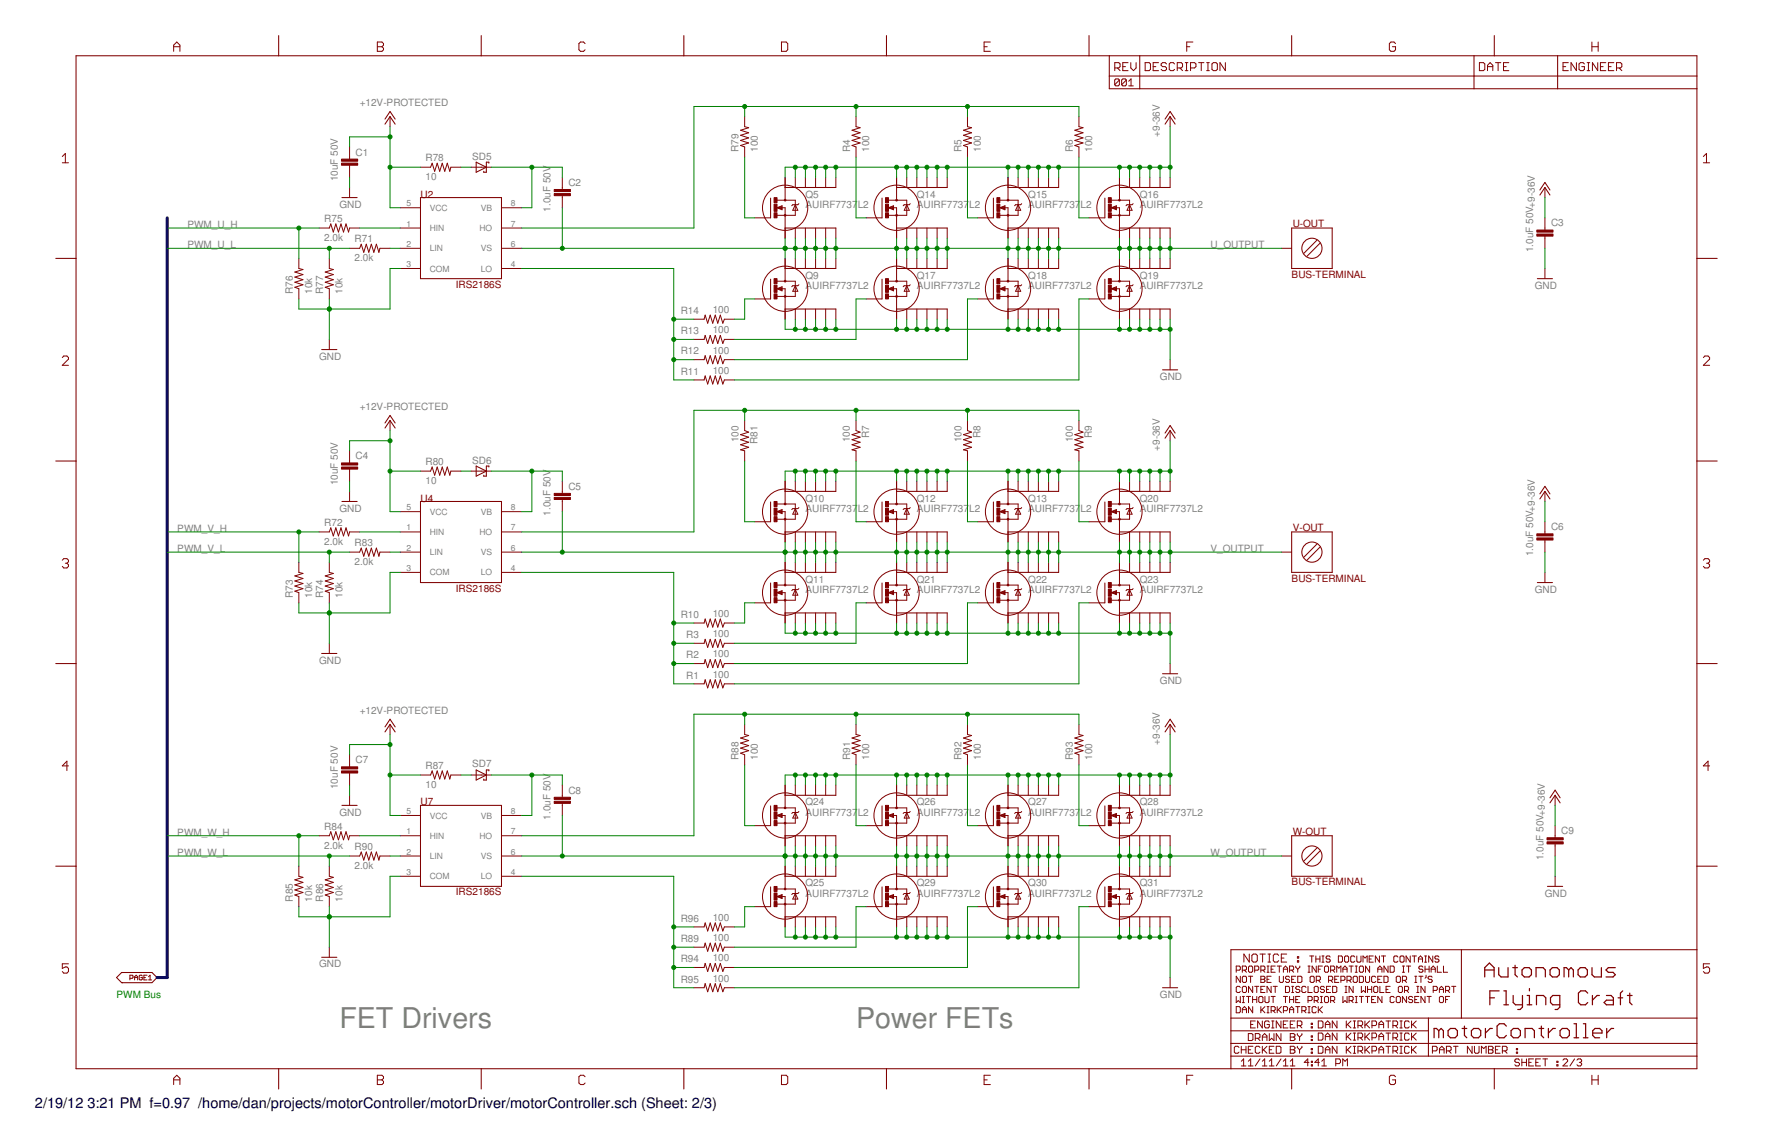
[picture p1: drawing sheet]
<svg xmlns="http://www.w3.org/2000/svg" width="431mm" height="279mm" viewBox="0 0 431 279" stroke-linecap="round" stroke-linejoin="round" font-family="sans-serif">
<defs><g id="words">
<g font-size="7" fill="#808080">
<text x="82.6" y="250.2">FET Drivers</text>
<text x="208.3" y="250.2">Power FETs</text>
</g>
<g font-size="3.5">
<text x="8.5" y="269.5">2/19/12</text>
<text x="21.3" y="269.5">3:21 PM f=0.97 /home/dan/projects/motorController/motorDriver/motorController.sch (Sheet: 2/3)</text>
</g>
<g font-size="2.4" fill="#808080">
<text x="87.5" y="25.9">+12V-PROTECTED</text>
<text x="282.2" y="33.3" transform="rotate(-90 282.2 33.3)">+9-36V</text>
<text x="86.5" y="37.9">C1</text>
<text x="103.5" y="39.2">R78</text>
<text x="114.9" y="38.8">SD5</text>
<text x="179.7" y="37" transform="rotate(-90 179.7 37)">R79</text>
<text x="184.4" y="37" transform="rotate(-90 184.4 37)">100</text>
<text x="206.8" y="37" transform="rotate(-90 206.8 37)">R4</text>
<text x="211.5" y="37" transform="rotate(-90 211.5 37)">100</text>
<text x="233.9" y="37" transform="rotate(-90 233.9 37)">R5</text>
<text x="238.6" y="37" transform="rotate(-90 238.6 37)">100</text>
<text x="261" y="37" transform="rotate(-90 261 37)">R6</text>
<text x="265.7" y="37" transform="rotate(-90 265.7 37)">100</text>
<text x="82.2" y="44.1" transform="rotate(-90 82.2 44.1)">10uF 50V</text>
<text x="103.5" y="43.9">10</text>
<text x="138.3" y="45.2">C2</text>
<text x="82.6" y="50.5">GND</text>
<text x="134" y="51.5" transform="rotate(-90 134 51.5)">1.0uF 50V</text>
<text x="195.9" y="50.5">AUIRF7737</text>
<text x="195.9" y="48.1">Q5</text>
<text x="208.7" y="50.5">L2</text>
<text x="223.1" y="50.5">AUIRF7737</text>
<text x="223.1" y="48.1">Q14</text>
<text x="235.8" y="50.5">L2</text>
<text x="250.2" y="50.5">AUIRF7737</text>
<text x="250.2" y="48.1">Q15</text>
<text x="262.9" y="50.5">L2</text>
<text x="277.3" y="50.5">AUIRF7737L2</text>
<text x="277.3" y="48.1">Q16</text>
<text x="45.6" y="55.5">PWM_U_H</text>
<text x="78.9" y="58.7">2.0k</text>
<text x="78.9" y="54">R75</text>
<text x="86.3" y="58.9">R71</text>
<text x="377.3" y="55.1">C3</text>
<text x="45.6" y="60.4">PWM_U_L</text>
<text x="86.3" y="63.6">2.0k</text>
<text x="294.5" y="60.4">U_OUTPUT</text>
<text x="373" y="61.4" transform="rotate(-90 373 61.4)">1.0uF 50V+9-36V</text>
<text x="71.3" y="71.5" transform="rotate(-90 71.3 71.5)">R76</text>
<text x="75.9" y="71.5" transform="rotate(-90 75.9 71.5)">10k</text>
<text x="78.7" y="71.5" transform="rotate(-90 78.7 71.5)">R77</text>
<text x="83.3" y="71.5" transform="rotate(-90 83.3 71.5)">10k</text>
<text x="195.9" y="70.3">AUIRF7737L2</text>
<text x="195.9" y="67.8">Q9</text>
<text x="223.1" y="70.3">AUIRF7737L2</text>
<text x="223.1" y="67.8">Q17</text>
<text x="250.2" y="70.3">AUIRF7737L2</text>
<text x="250.2" y="67.8">Q18</text>
<text x="277.3" y="70.3">AUIRF7737L2</text>
<text x="277.3" y="67.8">Q19</text>
<text x="373.4" y="70.3">GND</text>
<text x="165.6" y="76.4">R14</text>
<text x="173.4" y="76.2">100</text>
<text x="165.6" y="81.3">R13</text>
<text x="173.4" y="81.1">100</text>
<text x="77.6" y="87.5">GND</text>
<text x="165.6" y="86.2">R12</text>
<text x="173.4" y="86">100</text>
<text x="165.6" y="91.2">R11</text>
<text x="173.4" y="90.9">100</text>
<text x="282.2" y="92.4">GND</text>
<text x="87.5" y="99.8">+12V-PROTECTED</text>
<text x="179.7" y="107.6" transform="rotate(-90 179.7 107.6)">100</text>
<text x="184.3" y="108" transform="rotate(-90 184.3 108)">R81</text>
<text x="206.8" y="107.6" transform="rotate(-90 206.8 107.6)">100</text>
<text x="211.4" y="106.6" transform="rotate(-90 211.4 106.6)">R7</text>
<text x="233.9" y="107.6" transform="rotate(-90 233.9 107.6)">100</text>
<text x="238.5" y="106.6" transform="rotate(-90 238.5 106.6)">R8</text>
<text x="261" y="107.6" transform="rotate(-90 261 107.6)">100</text>
<text x="265.7" y="106.6" transform="rotate(-90 265.7 106.6)">R9</text>
<text x="86.5" y="111.8">C4</text>
<text x="103.5" y="113.2">R80</text>
<text x="114.9" y="112.8">SD6</text>
<text x="282.2" y="109.7" transform="rotate(-90 282.2 109.7)">+9-36V</text>
<text x="82.2" y="118.1" transform="rotate(-90 82.2 118.1)">10uF 50V</text>
<text x="103.5" y="117.8">10</text>
<text x="138.3" y="119.2">C5</text>
<text x="82.6" y="124.5">GND</text>
<text x="134" y="125.5" transform="rotate(-90 134 125.5)">1.0uF 50V</text>
<text x="195.9" y="124.5">AUIRF7737</text>
<text x="195.9" y="122">Q10</text>
<text x="208.7" y="124.5">L2</text>
<text x="223.1" y="124.5">AUIRF7737</text>
<text x="223.1" y="122">Q12</text>
<text x="235.8" y="124.5">L2</text>
<text x="250.2" y="124.5">AUIRF7737</text>
<text x="250.2" y="122">Q13</text>
<text x="262.9" y="124.5">L2</text>
<text x="277.3" y="124.5">AUIRF7737L2</text>
<text x="277.3" y="122">Q20</text>
<text x="43.1" y="129.4">PWM_V_H</text>
<text x="78.9" y="127.9">R72</text>
<text x="377.3" y="129">C6</text>
<text x="43.1" y="134.3">PWM_V_L</text>
<text x="78.9" y="132.6">2.0k</text>
<text x="86.3" y="137.5">2.0k</text>
<text x="86.3" y="132.9">R83</text>
<text x="294.5" y="134.3">V_OUTPUT</text>
<text x="373" y="135.3" transform="rotate(-90 373 135.3)">1.0uF 50V+9-36V</text>
<text x="195.9" y="141.7">Q11</text>
<text x="223.1" y="141.7">Q21</text>
<text x="250.2" y="141.7">Q22</text>
<text x="277.3" y="141.7">Q23</text>
<text x="71.3" y="145.4" transform="rotate(-90 71.3 145.4)">R73</text>
<text x="75.9" y="145.4" transform="rotate(-90 75.9 145.4)">10k</text>
<text x="78.7" y="145.4" transform="rotate(-90 78.7 145.4)">R74</text>
<text x="83.3" y="145.4" transform="rotate(-90 83.3 145.4)">10k</text>
<text x="195.9" y="144.2">AUIRF7737L2</text>
<text x="223.1" y="144.2">AUIRF7737L2</text>
<text x="250.2" y="144.2">AUIRF7737L2</text>
<text x="277.3" y="144.2">AUIRF7737L2</text>
<text x="373.4" y="144.2">GND</text>
<text x="165.6" y="150.3">R10</text>
<text x="167" y="155.2">R3</text>
<text x="173.4" y="155">100</text>
<text x="173.4" y="150.1">100</text>
<text x="77.6" y="161.4">GND</text>
<text x="167" y="160.2">R2</text>
<text x="173.4" y="159.9">100</text>
<text x="167" y="165.1">R1</text>
<text x="173.4" y="164.9">100</text>
<text x="282.2" y="166.4">GND</text>
<text x="87.5" y="173.8">+12V-PROTECTED</text>
<text x="86.5" y="185.7">C7</text>
<text x="179.7" y="184.8" transform="rotate(-90 179.7 184.8)">R88</text>
<text x="184.4" y="184.8" transform="rotate(-90 184.4 184.8)">100</text>
<text x="206.8" y="184.8" transform="rotate(-90 206.8 184.8)">R91</text>
<text x="211.5" y="184.8" transform="rotate(-90 211.5 184.8)">100</text>
<text x="233.9" y="184.8" transform="rotate(-90 233.9 184.8)">R92</text>
<text x="238.6" y="184.8" transform="rotate(-90 238.6 184.8)">100</text>
<text x="261" y="184.8" transform="rotate(-90 261 184.8)">R93</text>
<text x="265.7" y="184.8" transform="rotate(-90 265.7 184.8)">100</text>
<text x="282.2" y="181.2" transform="rotate(-90 282.2 181.2)">+9-36V</text>
<text x="82.2" y="192" transform="rotate(-90 82.2 192)">10uF 50V</text>
<text x="103.5" y="191.7">10</text>
<text x="103.5" y="187.1">R87</text>
<text x="114.9" y="186.7">SD7</text>
<text x="138.3" y="193.1">C8</text>
<text x="195.9" y="195.9">Q24</text>
<text x="223.1" y="195.9">Q26</text>
<text x="250.2" y="195.9">Q27</text>
<text x="277.3" y="195.9">Q28</text>
<text x="43.1" y="203.3">PWM_W_H</text>
<text x="78.9" y="201.9">R84</text>
<text x="82.6" y="198.4">GND</text>
<text x="134" y="199.4" transform="rotate(-90 134 199.4)">1.0uF 50V</text>
<text x="195.9" y="198.4">AUIRF7737</text>
<text x="208.7" y="198.4">L2</text>
<text x="223.1" y="198.4">AUIRF7737</text>
<text x="235.8" y="198.4">L2</text>
<text x="250.2" y="198.4">AUIRF7737</text>
<text x="262.9" y="198.4">L2</text>
<text x="277.3" y="198.4">AUIRF7737L2</text>
<text x="379.8" y="203">C9</text>
<text x="43.1" y="208.3">PWM_W_L</text>
<text x="78.9" y="206.5">2.0k</text>
<text x="86.3" y="206.8">R90</text>
<text x="294.5" y="208.3">W_OUTPUT</text>
<text x="375.5" y="209.2" transform="rotate(-90 375.5 209.2)">1.0uF 50V+9-36V</text>
<text x="86.3" y="211.5">2.0k</text>
<text x="195.9" y="215.7">Q25</text>
<text x="223.1" y="215.7">Q29</text>
<text x="250.2" y="215.7">Q30</text>
<text x="277.3" y="215.7">Q31</text>
<text x="71.3" y="219.3" transform="rotate(-90 71.3 219.3)">R85</text>
<text x="75.9" y="219.3" transform="rotate(-90 75.9 219.3)">10k</text>
<text x="78.7" y="219.3" transform="rotate(-90 78.7 219.3)">R86</text>
<text x="83.3" y="219.3" transform="rotate(-90 83.3 219.3)">10k</text>
<text x="195.9" y="218.1">AUIRF7737L2</text>
<text x="223.1" y="218.1">AUIRF7737L2</text>
<text x="250.2" y="218.1">AUIRF7737L2</text>
<text x="277.3" y="218.1">AUIRF7737L2</text>
<text x="375.9" y="218.1">GND</text>
<text x="165.6" y="224.2">R96</text>
<text x="173.4" y="224">100</text>
<text x="165.6" y="229.2">R89</text>
<text x="173.4" y="228.9">100</text>
<text x="173.4" y="233.9">100</text>
<text x="77.6" y="235.4">GND</text>
<text x="165.6" y="234.1">R94</text>
<text x="165.6" y="239">R95</text>
<text x="173.4" y="238.8">100</text>
<text x="282.2" y="242.8">GND</text>
</g>
<g font-size="2.4" fill="#800000">
<text x="102.3" y="48.1">U2</text>
<text x="314.5" y="55.2">U-OUT</text>
<text x="110.9" y="70">IRS2186S</text>
<text x="314.2" y="67.5">BUS-TERMINAL</text>
<text x="102.3" y="122">U4</text>
<text x="314.5" y="129.2">V-OUT</text>
<text x="110.9" y="143.9">IRS2186S</text>
<text x="314.2" y="141.5">BUS-TERMINAL</text>
<text x="102.3" y="195.9">U7</text>
<text x="314.5" y="203.1">W-OUT</text>
<text x="314.2" y="215.4">BUS-TERMINAL</text>
<text x="110.9" y="217.9">IRS2186S</text>
</g>
<text font-size="2.4" fill="#008000" x="28.4" y="242.8">PWM Bus</text>
<g font-size="2.1" fill="#808080">
<text x="98.9" y="50.2">5</text>
<text x="104.6" y="51.3">VCC</text>
<text x="117" y="51.3">VB</text>
<text x="124.3" y="50.2">8</text>
<text x="98.9" y="55.1">1</text>
<text x="104.6" y="56.2">HIN</text>
<text x="116.6" y="56.2">HO</text>
<text x="124.3" y="55.1">7</text>
<text x="98.9" y="60.1">2</text>
<text x="98.9" y="65">3</text>
<text x="104.6" y="61.1">LIN</text>
<text x="117" y="61.1">VS</text>
<text x="124.3" y="60.1">6</text>
<text x="124.3" y="65">4</text>
<text x="104.6" y="66.1">COM</text>
<text x="117" y="66.1">LO</text>
<text x="98.9" y="124.1">5</text>
<text x="104.6" y="125.2">VCC</text>
<text x="117" y="125.2">VB</text>
<text x="124.3" y="124.1">8</text>
<text x="98.9" y="129.1">1</text>
<text x="104.6" y="130.1">HIN</text>
<text x="116.6" y="130.1">HO</text>
<text x="124.3" y="129.1">7</text>
<text x="98.9" y="134">2</text>
<text x="104.6" y="135.1">LIN</text>
<text x="117" y="135.1">VS</text>
<text x="124.3" y="134">6</text>
<text x="98.9" y="138.9">3</text>
<text x="104.6" y="140">COM</text>
<text x="117" y="140">LO</text>
<text x="124.3" y="138.9">4</text>
<text x="98.9" y="198.1">5</text>
<text x="98.9" y="203">1</text>
<text x="104.6" y="199.1">VCC</text>
<text x="117" y="199.1">VB</text>
<text x="124.3" y="198.1">8</text>
<text x="124.3" y="203">7</text>
<text x="98.9" y="207.9">2</text>
<text x="104.6" y="204.1">HIN</text>
<text x="104.6" y="209">LIN</text>
<text x="116.6" y="204.1">HO</text>
<text x="117" y="209">VS</text>
<text x="124.3" y="207.9">6</text>
<text x="98.9" y="212.8">3</text>
<text x="104.6" y="213.9">COM</text>
<text x="117" y="213.9">LO</text>
<text x="124.3" y="212.8">4</text>
</g>
</g></defs>
<g fill="#800000" stroke="#800000" stroke-width=".24">
<path d="M142 261.6l.3 .4z"/>
<path d="M141.2 261.6h.8z"/>
<path d="M140.8 262l.4-.4z"/>
<path d="M140.8 262v1.5z"/>
<path d="M140.8 263.5l.4 .4z"/>
<path d="M141.2 263.9h.8z"/>
<path d="M142 263.9l.3-.4z"/>
<path d="M91.8 261.6v2.3z"/>
<path d="M91.8 261.6h1.1z"/>
<path d="M92.9 261.6l.4 .4z"/>
<path d="M93.3 262v.3z"/>
<path d="M93.3 262.3l-.4 .4z"/>
<path d="M92.9 262.7l.4 .4z"/>
<path d="M93.3 263.1v.4z"/>
<path d="M93.3 263.5l-.4 .4z"/>
<path d="M91.8 263.9h1.1z"/>
<path d="M91.8 262.7h1.1z"/>
<path d="M42.2 262.3v1.6z"/>
<path d="M42.2 262.3l.8-.7z"/>
<path d="M43 261.6l.8 .7z"/>
<path d="M43.8 262.3v1.6z"/>
<path d="M42.2 262.7h1.6z"/>
<path d="M190.1 261.6v2.3z"/>
<path d="M190.1 263.9h1.2z"/>
<path d="M191.3 263.9l.3-.4z"/>
<path d="M191.6 262v1.5z"/>
<path d="M191.3 261.6l.3 .4z"/>
<path d="M190.1 261.6h1.2z"/>
<path d="M239.4 261.6h1.5z"/>
<path d="M239.4 261.6v2.3z"/>
<path d="M239.4 263.9h1.5z"/>
<path d="M239.4 262.7h.8z"/>
<path d="M288.7 261.6v2.3z"/>
<path d="M288.7 261.6h1.5z"/>
<path d="M288.7 262.7h.8z"/>
<path d="M339.1 261.6l.4 .4z"/>
<path d="M338.4 261.6h.7z"/>
<path d="M338 262l.4-.4z"/>
<path d="M338 262v1.5z"/>
<path d="M338 263.5l.4 .4z"/>
<path d="M338.4 263.9h.7z"/>
<path d="M339.1 263.9l.4-.4z"/>
<path d="M339.5 262.7v.8z"/>
<path d="M338.7 262.7h.8z"/>
<path d="M387.3 261.6v2.3z"/>
<path d="M387.3 262.7h1.5z"/>
<path d="M388.8 261.6v2.3z"/>
<path d="M414.4 38.1l.8-.8z"/>
<path d="M415.2 37.3v2.3z"/>
<path d="M414.4 39.6h1.5z"/>
<path d="M414.4 88.9h1.5z"/>
<path d="M414.4 88.9l1.5-1.5z"/>
<path d="M415.9 87v.4z"/>
<path d="M415.5 86.6l.4 .4z"/>
<path d="M414.8 86.6h.7z"/>
<path d="M414.8 86.6l-.4 .4z"/>
<path d="M414.4 136.3l.4-.4z"/>
<path d="M414.8 135.9h.7z"/>
<path d="M415.5 135.9l.4 .4z"/>
<path d="M415.9 136.3v.4z"/>
<path d="M415.5 137l.4-.3z"/>
<path d="M415.2 137h.3z"/>
<path d="M415.5 137l.4 .4z"/>
<path d="M415.9 137.4v.4z"/>
<path d="M415.9 137.8l-.4 .4z"/>
<path d="M414.8 138.2h.7z"/>
<path d="M414.4 137.8l.4 .4z"/>
<path d="M415.5 185.2v2.3z"/>
<path d="M415.5 185.2l-1.1 1.1z"/>
<path d="M414.4 186.3h1.5z"/>
<path d="M414.4 234.5h1.5z"/>
<path d="M414.4 234.5v1.1z"/>
<path d="M414.4 235.6l.8-.4z"/>
<path d="M415.2 235.2h.3z"/>
<path d="M415.5 235.2l.4 .4z"/>
<path d="M415.9 235.6v.8z"/>
<path d="M415.9 236.4l-.4 .3z"/>
<path d="M414.8 236.7h.7z"/>
<path d="M414.4 236.4l.4 .3z"/>
<path d="M15.9 37.3l-.7 .8z"/>
<path d="M15.9 37.3v2.3z"/>
<path d="M15.2 39.6h1.5z"/>
<path d="M15.2 88.9h1.5z"/>
<path d="M15.2 88.9l1.5-1.5z"/>
<path d="M16.7 87v.4z"/>
<path d="M16.3 86.6l.4 .4z"/>
<path d="M15.5 86.6h.8z"/>
<path d="M15.5 86.6l-.3 .4z"/>
<path d="M15.5 135.9l-.3 .4z"/>
<path d="M15.5 135.9h.8z"/>
<path d="M16.3 135.9l.4 .4z"/>
<path d="M16.7 136.3v.4z"/>
<path d="M16.3 137l.4-.3z"/>
<path d="M15.9 137h.4z"/>
<path d="M16.3 137l.4 .4z"/>
<path d="M16.7 137.4v.4z"/>
<path d="M16.7 137.8l-.4 .4z"/>
<path d="M15.5 138.2h.8z"/>
<path d="M15.2 137.8l.3 .4z"/>
<path d="M16.3 185.2v2.3z"/>
<path d="M16.3 185.2l-1.1 1.1z"/>
<path d="M15.2 186.3h1.5z"/>
<path d="M15.2 234.5h1.5z"/>
<path d="M15.2 234.5v1.1z"/>
<path d="M15.2 235.6l.7-.4z"/>
<path d="M15.9 235.2h.4z"/>
<path d="M16.3 235.2l.4 .4z"/>
<path d="M16.7 235.6v.8z"/>
<path d="M16.7 236.4l-.4 .3z"/>
<path d="M15.5 236.7h.8z"/>
<path d="M15.2 236.4l.3 .3z"/>
<path d="M142 10.2l.3 .4z"/>
<path d="M141.2 10.2h.8z"/>
<path d="M141.2 10.2l-.4 .4z"/>
<path d="M140.8 10.6v1.5z"/>
<path d="M140.8 12.1l.4 .4z"/>
<path d="M141.2 12.5h.8z"/>
<path d="M142 12.5l.3-.4z"/>
<path d="M91.8 10.2v2.3z"/>
<path d="M91.8 10.2h1.1z"/>
<path d="M92.9 10.2l.4 .4z"/>
<path d="M93.3 10.6v.4z"/>
<path d="M93.3 11l-.4 .4z"/>
<path d="M92.9 11.4l.4 .3z"/>
<path d="M93.3 11.7v.4z"/>
<path d="M93.3 12.1l-.4 .4z"/>
<path d="M91.8 12.5h1.1z"/>
<path d="M91.8 11.4h1.1z"/>
<path d="M42.2 11v1.5z"/>
<path d="M42.2 11l.8-.8z"/>
<path d="M43 10.2l.8 .8z"/>
<path d="M43.8 11v1.5z"/>
<path d="M42.2 11.4h1.6z"/>
<path d="M190.1 10.2v2.3z"/>
<path d="M190.1 12.5h1.2z"/>
<path d="M191.3 12.5l.3-.4z"/>
<path d="M191.6 10.6v1.5z"/>
<path d="M191.3 10.2l.3 .4z"/>
<path d="M190.1 10.2h1.2z"/>
<path d="M239.4 10.2h1.5z"/>
<path d="M239.4 10.2v2.3z"/>
<path d="M239.4 12.5h1.5z"/>
<path d="M239.4 11.4h.8z"/>
<path d="M288.7 10.2v2.3z"/>
<path d="M288.7 10.2h1.5z"/>
<path d="M288.7 11.4h.8z"/>
<path d="M339.1 10.2l.4 .4z"/>
<path d="M338.4 10.2h.7z"/>
<path d="M338 10.6l.4-.4z"/>
<path d="M338 10.6v1.5z"/>
<path d="M338 12.1l.4 .4z"/>
<path d="M338.4 12.5h.7z"/>
<path d="M339.1 12.5l.4-.4z"/>
<path d="M339.5 11.4v.7z"/>
<path d="M338.7 11.4h.8z"/>
<path d="M387.3 10.2v2.3z"/>
<path d="M387.3 11.4h1.5z"/>
<path d="M388.8 10.2v2.3z"/>
<path d="M271.2 15.2v2z"/>
<path d="M271.2 15.2h1z"/>
<path d="M272.2 15.2l.3 .4z"/>
<path d="M272.5 15.6v.6z"/>
<path d="M272.5 16.2l-.3 .3z"/>
<path d="M271.2 16.5h1z"/>
<path d="M271.8 16.5l.7 .7z"/>
<path d="M273.2 15.2h1.2z"/>
<path d="M273.2 15.2v2z"/>
<path d="M273.2 17.2h1.2z"/>
<path d="M273.2 16.2h.6z"/>
<path d="M275.1 15.2v1.3z"/>
<path d="M275.1 16.5l.7 .7z"/>
<path d="M276.4 16.5l-.6 .7z"/>
<path d="M276.4 15.2v1.3z"/>
<path d="M278.6 15.2v2z"/>
<path d="M278.6 17.2h1z"/>
<path d="M279.9 16.9l-.3 .3z"/>
<path d="M279.9 15.6v1.3z"/>
<path d="M279.6 15.2l.3 .4z"/>
<path d="M278.6 15.2h1z"/>
<path d="M280.5 15.2h1.4z"/>
<path d="M280.5 15.2v2z"/>
<path d="M280.5 17.2h1.4z"/>
<path d="M280.5 16.2h.7z"/>
<path d="M283.5 15.2l.3 .4z"/>
<path d="M282.8 15.2h.7z"/>
<path d="M282.5 15.6l.3-.4z"/>
<path d="M282.5 15.6v.3z"/>
<path d="M282.5 15.9l.3 .3z"/>
<path d="M282.8 16.2h.7z"/>
<path d="M283.5 16.2l.3 .3z"/>
<path d="M283.8 16.5v.4z"/>
<path d="M283.5 17.2l.3-.3z"/>
<path d="M282.8 17.2h.7z"/>
<path d="M282.5 16.9l.3 .3z"/>
<path d="M285.4 15.2l.3 .4z"/>
<path d="M284.8 15.2h.6z"/>
<path d="M284.8 15.2l-.3 .4z"/>
<path d="M284.5 15.6v1.3z"/>
<path d="M284.5 16.9l.3 .3z"/>
<path d="M284.8 17.2h.6z"/>
<path d="M285.4 17.2l.3-.3z"/>
<path d="M286.4 15.2v2z"/>
<path d="M286.4 15.2h1z"/>
<path d="M287.4 15.2l.3 .4z"/>
<path d="M287.7 15.6v.6z"/>
<path d="M287.7 16.2l-.3 .3z"/>
<path d="M286.4 16.5h1z"/>
<path d="M287 16.5l.7 .7z"/>
<path d="M288.3 17.2h.7z"/>
<path d="M288.7 15.2v2z"/>
<path d="M288.3 15.2h.7z"/>
<path d="M289.6 15.2v2z"/>
<path d="M289.6 15.2h1z"/>
<path d="M290.6 15.2l.4 .4z"/>
<path d="M291 15.6v.6z"/>
<path d="M290.6 16.5l.4-.3z"/>
<path d="M289.6 16.5h1z"/>
<path d="M292.2 15.2v2z"/>
<path d="M291.6 15.2h1.3z"/>
<path d="M293.6 17.2h.6z"/>
<path d="M293.9 15.2v2z"/>
<path d="M293.6 15.2h.6z"/>
<path d="M295.2 15.2h.6z"/>
<path d="M294.8 15.6l.4-.4z"/>
<path d="M294.8 15.6v1.3z"/>
<path d="M294.8 16.9l.4 .3z"/>
<path d="M295.2 17.2h.6z"/>
<path d="M295.8 17.2l.4-.3z"/>
<path d="M296.2 15.6v1.3z"/>
<path d="M295.8 15.2l.4 .4z"/>
<path d="M296.8 15.2v2z"/>
<path d="M296.8 15.2l1.3 2z"/>
<path d="M298.1 15.2v2z"/>
<path d="M359.9 15.2v2z"/>
<path d="M359.9 17.2h1z"/>
<path d="M360.9 17.2l.3-.3z"/>
<path d="M361.2 15.6v1.3z"/>
<path d="M360.9 15.2l.3 .4z"/>
<path d="M359.9 15.2h1z"/>
<path d="M361.9 15.9v1.3z"/>
<path d="M362.5 15.2l-.6 .7z"/>
<path d="M362.5 15.2l.7 .7z"/>
<path d="M363.2 15.9v1.3z"/>
<path d="M361.9 16.2h1.3z"/>
<path d="M364.5 15.2v2z"/>
<path d="M363.8 15.2h1.3z"/>
<path d="M365.8 15.2h1.3z"/>
<path d="M365.8 15.2v2z"/>
<path d="M365.8 17.2h1.3z"/>
<path d="M365.8 16.2h.6z"/>
<path d="M380.3 15.2h1.2z"/>
<path d="M380.3 15.2v2z"/>
<path d="M380.3 17.2h1.2z"/>
<path d="M380.3 16.2h.6z"/>
<path d="M382.2 15.2v2z"/>
<path d="M382.2 15.2l1.3 2z"/>
<path d="M383.5 15.2v2z"/>
<path d="M385.1 15.2l.4 .4z"/>
<path d="M384.5 15.2h.6z"/>
<path d="M384.1 15.6l.4-.4z"/>
<path d="M384.1 15.6v1.3z"/>
<path d="M384.1 16.9l.4 .3z"/>
<path d="M384.5 17.2h.6z"/>
<path d="M385.1 17.2l.4-.3z"/>
<path d="M385.5 16.2v.7z"/>
<path d="M384.8 16.2h.7z"/>
<path d="M386.1 17.2h.7z"/>
<path d="M386.4 15.2v2z"/>
<path d="M386.1 15.2h.7z"/>
<path d="M387.4 15.2v2z"/>
<path d="M387.4 15.2l1.3 2z"/>
<path d="M388.7 15.2v2z"/>
<path d="M389.4 15.2h1.3z"/>
<path d="M389.4 15.2v2z"/>
<path d="M389.4 17.2h1.3z"/>
<path d="M389.4 16.2h.6z"/>
<path d="M391.3 15.2h1.3z"/>
<path d="M391.3 15.2v2z"/>
<path d="M391.3 17.2h1.3z"/>
<path d="M391.3 16.2h.7z"/>
<path d="M393.3 15.2v2z"/>
<path d="M393.3 15.2h.9z"/>
<path d="M394.2 15.2l.4 .4z"/>
<path d="M394.6 15.6v.6z"/>
<path d="M394.6 16.2l-.4 .3z"/>
<path d="M393.3 16.5h.9z"/>
<path d="M393.9 16.5l.7 .7z"/>
<path d="M303.7 251.5v1.6z"/>
<path d="M303.7 253.1h.8z"/>
<path d="M304.5 253.1l.3-.2z"/>
<path d="M304.8 251.7v1.2z"/>
<path d="M304.5 251.5l.3 .2z"/>
<path d="M303.7 251.5h.8z"/>
<path d="M305.4 251.5v1.6z"/>
<path d="M305.4 251.5h.8z"/>
<path d="M306.2 251.5l.3 .2z"/>
<path d="M306.5 251.7v.6z"/>
<path d="M306.5 252.3l-.3 .3z"/>
<path d="M305.4 252.6h.8z"/>
<path d="M306 252.6l.5 .5z"/>
<path d="M307.1 252v1.1z"/>
<path d="M307.7 251.5l-.6 .5z"/>
<path d="M307.7 251.5l.5 .5z"/>
<path d="M308.2 252v1.1z"/>
<path d="M307.1 252.3h1.1z"/>
<path d="M308.8 251.5v1.6z"/>
<path d="M308.8 253.1l.6-.5z"/>
<path d="M309.4 252.6l.5 .5z"/>
<path d="M309.9 251.5v1.6z"/>
<path d="M310.5 251.5v1.6z"/>
<path d="M310.5 251.5l1.1 1.6z"/>
<path d="M311.6 251.5v1.6z"/>
<path d="M313.9 251.5v1.6z"/>
<path d="M313.9 251.5h.8z"/>
<path d="M314.7 251.5l.3 .2z"/>
<path d="M315 251.7v.3z"/>
<path d="M314.7 252.3l.3-.3z"/>
<path d="M314.7 252.3l.3 .3z"/>
<path d="M315 252.6v.3z"/>
<path d="M314.7 253.1l.3-.2z"/>
<path d="M313.9 253.1h.8z"/>
<path d="M313.9 252.3h.8z"/>
<path d="M315.6 251.5v.2z"/>
<path d="M315.6 251.7l.6 .6z"/>
<path d="M316.2 252.3l.5-.6z"/>
<path d="M316.7 251.5v.2z"/>
<path d="M316.2 252.3v.8z"/>
<path d="M319 252h.3z"/>
<path d="M319.3 252v.3z"/>
<path d="M319 252.3h.3z"/>
<path d="M319 252v.3z"/>
<path d="M319 252.9h.3z"/>
<path d="M319.3 252.9v.2z"/>
<path d="M319 253.1h.3z"/>
<path d="M319 252.9v.2z"/>
<path d="M301.1 254.5l.3 .3z"/>
<path d="M300.6 254.5h.5z"/>
<path d="M300.6 254.5l-.3 .3z"/>
<path d="M300.3 254.8v1.2z"/>
<path d="M300.3 256l.3 .2z"/>
<path d="M300.6 256.2h.5z"/>
<path d="M301.1 256.2l.3-.2z"/>
<path d="M302 254.5v1.7z"/>
<path d="M302 255.4h1.1z"/>
<path d="M303.1 254.5v1.7z"/>
<path d="M303.7 254.5h1.1z"/>
<path d="M303.7 254.5v1.7z"/>
<path d="M303.7 256.2h1.1z"/>
<path d="M303.7 255.4h.6z"/>
<path d="M306.2 254.5l.3 .3z"/>
<path d="M305.7 254.5h.5z"/>
<path d="M305.4 254.8l.3-.3z"/>
<path d="M305.4 254.8v1.2z"/>
<path d="M305.4 256l.3 .2z"/>
<path d="M305.7 256.2h.5z"/>
<path d="M306.2 256.2l.3-.2z"/>
<path d="M307.1 254.5v1.7z"/>
<path d="M307.1 255.7l1.1-1.2z"/>
<path d="M307.4 255.4l.8 .8z"/>
<path d="M308.8 254.5h1.1z"/>
<path d="M308.8 254.5v1.7z"/>
<path d="M308.8 256.2h1.1z"/>
<path d="M308.8 255.4h.6z"/>
<path d="M310.5 254.5v1.7z"/>
<path d="M310.5 256.2h.9z"/>
<path d="M311.4 256.2l.2-.2z"/>
<path d="M311.6 254.8v1.2z"/>
<path d="M311.4 254.5l.2 .3z"/>
<path d="M310.5 254.5h.9z"/>
<path d="M313.9 254.5v1.7z"/>
<path d="M313.9 254.5h.8z"/>
<path d="M314.7 254.5l.3 .3z"/>
<path d="M315 254.8v.3z"/>
<path d="M315 255.1l-.3 .3z"/>
<path d="M314.7 255.4l.3 .3z"/>
<path d="M315 255.7v.3z"/>
<path d="M314.7 256.2l.3-.2z"/>
<path d="M313.9 256.2h.8z"/>
<path d="M313.9 255.4h.8z"/>
<path d="M315.6 254.5v.3z"/>
<path d="M315.6 254.8l.6 .6z"/>
<path d="M316.2 255.4l.5-.6z"/>
<path d="M316.7 254.5v.3z"/>
<path d="M316.2 255.4v.8z"/>
<path d="M319 255.1h.3z"/>
<path d="M319.3 255.1v.3z"/>
<path d="M319 255.4h.3z"/>
<path d="M319 255.1v.3z"/>
<path d="M319 256h.3z"/>
<path d="M319.3 256v.2z"/>
<path d="M319 256.2h.3z"/>
<path d="M319 256v.2z"/>
<path d="M304.3 248.4h1.1z"/>
<path d="M304.3 248.4v1.7z"/>
<path d="M304.3 250.1h1.1z"/>
<path d="M304.3 249.2h.5z"/>
<path d="M306 248.4v1.7z"/>
<path d="M306 248.4l1.1 1.7z"/>
<path d="M307.1 248.4v1.7z"/>
<path d="M308.5 248.4l.3 .3z"/>
<path d="M307.9 248.4h.6z"/>
<path d="M307.7 248.7l.2-.3z"/>
<path d="M307.7 248.7v1.1z"/>
<path d="M307.7 249.8l.2 .3z"/>
<path d="M307.9 250.1h.6z"/>
<path d="M308.5 250.1l.3-.3z"/>
<path d="M308.8 249.2v.6z"/>
<path d="M308.2 249.2h.6z"/>
<path d="M309.4 250.1h.5z"/>
<path d="M309.6 248.4v1.7z"/>
<path d="M309.4 248.4h.5z"/>
<path d="M310.5 248.4v1.7z"/>
<path d="M310.5 248.4l1.1 1.7z"/>
<path d="M311.6 248.4v1.7z"/>
<path d="M312.2 248.4h1.1z"/>
<path d="M312.2 248.4v1.7z"/>
<path d="M312.2 250.1h1.1z"/>
<path d="M312.2 249.2h.6z"/>
<path d="M313.9 248.4h1.1z"/>
<path d="M313.9 248.4v1.7z"/>
<path d="M313.9 250.1h1.1z"/>
<path d="M313.9 249.2h.6z"/>
<path d="M315.6 248.4v1.7z"/>
<path d="M315.6 248.4h.9z"/>
<path d="M316.5 248.4l.2 .3z"/>
<path d="M316.7 248.7v.5z"/>
<path d="M316.7 249.2l-.2 .3z"/>
<path d="M315.6 249.5h.9z"/>
<path d="M316.2 249.5l.5 .6z"/>
<path d="M319 248.9h.3z"/>
<path d="M319.3 248.9v.3z"/>
<path d="M319 249.2h.3z"/>
<path d="M319 248.9v.3z"/>
<path d="M319 249.8h.3z"/>
<path d="M319.3 249.8v.3z"/>
<path d="M319 250.1h.3z"/>
<path d="M319 249.8v.3z"/>
<path d="M348.5 254.5v1.7z"/>
<path d="M348.5 254.5h.9z"/>
<path d="M349.4 254.5l.2 .3z"/>
<path d="M349.6 254.8v.6z"/>
<path d="M349.4 255.7l.2-.3z"/>
<path d="M348.5 255.7h.9z"/>
<path d="M350.2 255.1v1.1z"/>
<path d="M350.2 255.1l.6-.6z"/>
<path d="M350.8 254.5l.5 .6z"/>
<path d="M351.3 255.1v1.1z"/>
<path d="M350.2 255.4h1.1z"/>
<path d="M351.9 254.5v1.7z"/>
<path d="M351.9 254.5h.8z"/>
<path d="M352.7 254.5l.3 .3z"/>
<path d="M353 254.8v.6z"/>
<path d="M352.7 255.7l.3-.3z"/>
<path d="M351.9 255.7h.8z"/>
<path d="M352.5 255.7l.5 .5z"/>
<path d="M354.2 254.5v1.7z"/>
<path d="M353.6 254.5h1.1z"/>
<path d="M357 254.5v1.7z"/>
<path d="M357 254.5l1.1 1.7z"/>
<path d="M358.1 254.5v1.7z"/>
<path d="M358.7 254.5v1.5z"/>
<path d="M358.7 256l.3 .2z"/>
<path d="M359 256.2h.6z"/>
<path d="M359.6 256.2l.2-.2z"/>
<path d="M359.8 254.5v1.5z"/>
<path d="M360.4 254.5v1.7z"/>
<path d="M360.4 254.5l.6 .6z"/>
<path d="M361 255.1l.5-.6z"/>
<path d="M361.5 254.5v1.7z"/>
<path d="M362.1 254.5v1.7z"/>
<path d="M362.1 254.5h.9z"/>
<path d="M363 254.5l.2 .3z"/>
<path d="M363.2 254.8v.3z"/>
<path d="M363.2 255.1l-.2 .3z"/>
<path d="M363 255.4l.2 .3z"/>
<path d="M363.2 255.7v.3z"/>
<path d="M363.2 256l-.2 .2z"/>
<path d="M362.1 256.2h.9z"/>
<path d="M362.1 255.4h.9z"/>
<path d="M363.8 254.5h1.1z"/>
<path d="M363.8 254.5v1.7z"/>
<path d="M363.8 256.2h1.1z"/>
<path d="M363.8 255.4h.6z"/>
<path d="M365.5 254.5v1.7z"/>
<path d="M365.5 254.5h.9z"/>
<path d="M366.4 254.5l.2 .3z"/>
<path d="M366.6 254.8v.6z"/>
<path d="M366.6 255.4l-.2 .3z"/>
<path d="M365.5 255.7h.9z"/>
<path d="M366.1 255.7l.5 .5z"/>
<path d="M368.9 255.1h.3z"/>
<path d="M369.2 255.1v.3z"/>
<path d="M368.9 255.4h.3z"/>
<path d="M368.9 255.1v.3z"/>
<path d="M368.9 256h.3z"/>
<path d="M369.2 256v.2z"/>
<path d="M368.9 256.2h.3z"/>
<path d="M368.9 256v.2z"/>
<path d="M302.6 232.1v2z"/>
<path d="M302.6 232.1l1.3 2z"/>
<path d="M303.9 232.1v2z"/>
<path d="M304.9 232.1h.6z"/>
<path d="M304.6 232.4l.3-.3z"/>
<path d="M304.6 232.4v1.3z"/>
<path d="M304.6 233.7l.3 .4z"/>
<path d="M304.9 234.1h.6z"/>
<path d="M305.5 234.1l.4-.4z"/>
<path d="M305.9 232.4v1.3z"/>
<path d="M305.5 232.1l.4 .3z"/>
<path d="M307.2 232.1v2z"/>
<path d="M306.5 232.1h1.3z"/>
<path d="M308.5 234.1h.6z"/>
<path d="M308.8 232.1v2z"/>
<path d="M308.5 232.1h.6z"/>
<path d="M310.7 232.1l.4 .3z"/>
<path d="M310.1 232.1h.6z"/>
<path d="M309.8 232.4l.3-.3z"/>
<path d="M309.8 232.4v1.3z"/>
<path d="M309.8 233.7l.3 .4z"/>
<path d="M310.1 234.1h.6z"/>
<path d="M310.7 234.1l.4-.4z"/>
<path d="M311.7 232.1h1.3z"/>
<path d="M311.7 232.1v2z"/>
<path d="M311.7 234.1h1.3z"/>
<path d="M311.7 233.1h.7z"/>
<path d="M315.6 232.7h.3z"/>
<path d="M315.9 232.7v.4z"/>
<path d="M315.6 233.1h.3z"/>
<path d="M315.6 232.7v.4z"/>
<path d="M315.6 233.7h.3z"/>
<path d="M315.9 233.7v.4z"/>
<path d="M315.6 234.1h.3z"/>
<path d="M315.6 233.7v.4z"/>
<path d="M302.6 257.6l-.6 .6z"/>
<path d="M302.6 257.6v1.7z"/>
<path d="M302 259.3h1.1z"/>
<path d="M303.7 258.2l.6-.6z"/>
<path d="M304.3 257.6v1.7z"/>
<path d="M303.7 259.3h1.1z"/>
<path d="M306.5 257.6l-1.1 1.7z"/>
<path d="M307.1 258.2l.6-.6z"/>
<path d="M307.7 257.6v1.7z"/>
<path d="M307.1 259.3h1.1z"/>
<path d="M308.8 258.2l.6-.6z"/>
<path d="M309.4 257.6v1.7z"/>
<path d="M308.8 259.3h1.1z"/>
<path d="M311.6 257.6l-1.1 1.7z"/>
<path d="M312.2 258.2l.6-.6z"/>
<path d="M312.8 257.6v1.7z"/>
<path d="M312.2 259.3h1.1z"/>
<path d="M314.5 257.6l-.6 .6z"/>
<path d="M314.5 257.6v1.7z"/>
<path d="M313.9 259.3h1.1z"/>
<path d="M318.2 257.6v1.7z"/>
<path d="M318.2 257.6l-.9 .9z"/>
<path d="M317.3 258.5h1.1z"/>
<path d="M319 258.2h.3z"/>
<path d="M319.3 258.2v.3z"/>
<path d="M319 258.5h.3z"/>
<path d="M319 258.2v.3z"/>
<path d="M319 259h.3z"/>
<path d="M319.3 259v.3z"/>
<path d="M319 259.3h.3z"/>
<path d="M319 259v.3z"/>
<path d="M320.7 257.6v1.7z"/>
<path d="M320.7 257.6l-.8 .9z"/>
<path d="M319.9 258.5h1.1z"/>
<path d="M321.6 258.2l.5-.6z"/>
<path d="M322.1 257.6v1.7z"/>
<path d="M321.6 259.3h1.1z"/>
<path d="M325 257.6v1.7z"/>
<path d="M325 257.6h.8z"/>
<path d="M325.8 257.6l.3 .3z"/>
<path d="M326.1 257.9v.6z"/>
<path d="M326.1 258.5l-.3 .3z"/>
<path d="M325 258.8h.8z"/>
<path d="M326.7 257.6v1.7z"/>
<path d="M326.7 257.6l.5 .6z"/>
<path d="M327.2 258.2l.6-.6z"/>
<path d="M327.8 257.6v1.7z"/>
<path d="M369.4 257.6l.3 .3z"/>
<path d="M368.8 257.6h.6z"/>
<path d="M368.8 257.6l-.3 .3z"/>
<path d="M368.5 257.9v.3z"/>
<path d="M368.5 258.2l.3 .3z"/>
<path d="M368.8 258.5h.6z"/>
<path d="M369.4 258.5l.3 .3z"/>
<path d="M369.7 258.8v.2z"/>
<path d="M369.7 259l-.3 .3z"/>
<path d="M368.8 259.3h.6z"/>
<path d="M368.5 259l.3 .3z"/>
<path d="M370.2 257.6v1.7z"/>
<path d="M370.2 258.5h1.2z"/>
<path d="M371.4 257.6v1.7z"/>
<path d="M371.9 257.6h1.2z"/>
<path d="M371.9 257.6v1.7z"/>
<path d="M371.9 259.3h1.2z"/>
<path d="M371.9 258.5h.6z"/>
<path d="M373.6 257.6h1.2z"/>
<path d="M373.6 257.6v1.7z"/>
<path d="M373.6 259.3h1.2z"/>
<path d="M373.6 258.5h.6z"/>
<path d="M375.9 257.6v1.7z"/>
<path d="M375.3 257.6h1.2z"/>
<path d="M378.8 258.2h.2z"/>
<path d="M379 258.2v.3z"/>
<path d="M378.8 258.5h.2z"/>
<path d="M378.8 258.2v.3z"/>
<path d="M378.8 259h.2z"/>
<path d="M379 259v.3z"/>
<path d="M378.8 259.3h.2z"/>
<path d="M378.8 259v.3z"/>
<path d="M380.2 259.3h1.2z"/>
<path d="M380.2 259.3l1.2-1.1z"/>
<path d="M381.4 257.9v.3z"/>
<path d="M381.1 257.6l.3 .3z"/>
<path d="M380.5 257.6h.6z"/>
<path d="M380.5 257.6l-.3 .3z"/>
<path d="M383.1 257.6l-1.2 1.7z"/>
<path d="M383.6 257.9l.3-.3z"/>
<path d="M383.9 257.6h.6z"/>
<path d="M384.5 257.6l.3 .3z"/>
<path d="M384.8 257.9v.3z"/>
<path d="M384.5 258.5l.3-.3z"/>
<path d="M384.2 258.5h.3z"/>
<path d="M384.5 258.5l.3 .3z"/>
<path d="M384.8 258.8v.2z"/>
<path d="M384.8 259l-.3 .3z"/>
<path d="M383.9 259.3h.6z"/>
<path d="M383.6 259l.3 .3z"/>
<path d="M319.1 232.6v1.5z"/>
<path d="M318.6 232.6h1z"/>
<path d="M320.1 232.6v1.5z"/>
<path d="M320.1 233.3h1z"/>
<path d="M321.1 232.6v1.5z"/>
<path d="M321.6 234.1h.5z"/>
<path d="M321.9 232.6v1.5z"/>
<path d="M321.6 232.6h.5z"/>
<path d="M323.4 232.6l.2 .2z"/>
<path d="M322.8 232.6h.6z"/>
<path d="M322.8 232.6l-.2 .2z"/>
<path d="M322.6 232.8v.3z"/>
<path d="M322.6 233.1l.2 .2z"/>
<path d="M322.8 233.3h.6z"/>
<path d="M323.4 233.3l.2 .3z"/>
<path d="M323.6 233.6v.2z"/>
<path d="M323.6 233.8l-.2 .3z"/>
<path d="M322.8 234.1h.6z"/>
<path d="M322.6 233.8l.2 .3z"/>
<path d="M325.6 232.6v1.5z"/>
<path d="M325.6 234.1h.8z"/>
<path d="M326.6 233.8l-.2 .3z"/>
<path d="M326.6 232.8v1z"/>
<path d="M326.4 232.6l.2 .2z"/>
<path d="M325.6 232.6h.8z"/>
<path d="M327.4 232.6h.4z"/>
<path d="M327.1 232.8l.3-.2z"/>
<path d="M327.1 232.8v1z"/>
<path d="M327.1 233.8l.3 .3z"/>
<path d="M327.4 234.1h.4z"/>
<path d="M328.1 233.8l-.3 .3z"/>
<path d="M328.1 232.8v1z"/>
<path d="M327.8 232.6l.3 .2z"/>
<path d="M329.3 232.6l.3 .2z"/>
<path d="M328.8 232.6h.5z"/>
<path d="M328.8 232.6l-.2 .2z"/>
<path d="M328.6 232.8v1z"/>
<path d="M328.6 233.8l.2 .3z"/>
<path d="M328.8 234.1h.5z"/>
<path d="M329.3 234.1l.3-.3z"/>
<path d="M330.1 232.6v1.2z"/>
<path d="M330.1 233.8l.2 .3z"/>
<path d="M330.3 234.1h.6z"/>
<path d="M330.9 234.1l.2-.3z"/>
<path d="M331.1 232.6v1.2z"/>
<path d="M331.6 232.6v1.5z"/>
<path d="M331.6 232.6l.5 .5z"/>
<path d="M332.1 233.1l.5-.5z"/>
<path d="M332.6 232.6v1.5z"/>
<path d="M333.1 232.6h1z"/>
<path d="M333.1 232.6v1.5z"/>
<path d="M333.1 234.1h1z"/>
<path d="M333.1 233.3h.5z"/>
<path d="M334.6 232.6v1.5z"/>
<path d="M334.6 232.6l1 1.5z"/>
<path d="M335.6 232.6v1.5z"/>
<path d="M336.6 232.6v1.5z"/>
<path d="M336.1 232.6h1z"/>
<path d="M339.8 232.6l.3 .2z"/>
<path d="M339.3 232.6h.5z"/>
<path d="M339.3 232.6l-.2 .2z"/>
<path d="M339.1 232.8v1z"/>
<path d="M339.1 233.8l.2 .3z"/>
<path d="M339.3 234.1h.5z"/>
<path d="M339.8 234.1l.3-.3z"/>
<path d="M340.8 232.6h.5z"/>
<path d="M340.8 232.6l-.2 .2z"/>
<path d="M340.6 232.8v1z"/>
<path d="M340.6 233.8l.2 .3z"/>
<path d="M340.8 234.1h.5z"/>
<path d="M341.3 234.1l.3-.3z"/>
<path d="M341.6 232.8v1z"/>
<path d="M341.3 232.6l.3 .2z"/>
<path d="M342.1 232.6v1.5z"/>
<path d="M342.1 232.6l1 1.5z"/>
<path d="M343.1 232.6v1.5z"/>
<path d="M344.1 232.6v1.5z"/>
<path d="M343.6 232.6h1z"/>
<path d="M345.1 233.1v1z"/>
<path d="M345.1 233.1l.5-.5z"/>
<path d="M345.6 232.6l.5 .5z"/>
<path d="M346.1 233.1v1z"/>
<path d="M345.1 233.3h1z"/>
<path d="M346.6 234.1h.5z"/>
<path d="M346.8 232.6v1.5z"/>
<path d="M346.6 232.6h.5z"/>
<path d="M347.6 232.6v1.5z"/>
<path d="M347.6 232.6l1 1.5z"/>
<path d="M348.6 232.6v1.5z"/>
<path d="M349.8 232.6l.3 .2z"/>
<path d="M349.3 232.6h.5z"/>
<path d="M349.3 232.6l-.2 .2z"/>
<path d="M349.1 232.8v.3z"/>
<path d="M349.1 233.1l.2 .2z"/>
<path d="M349.3 233.3h.5z"/>
<path d="M349.8 233.3l.3 .3z"/>
<path d="M350.1 233.6v.2z"/>
<path d="M350.1 233.8l-.3 .3z"/>
<path d="M349.3 234.1h.5z"/>
<path d="M349.1 233.8l.2 .3z"/>
<path d="M300.8 235v1.5z"/>
<path d="M300.8 235h.7z"/>
<path d="M301.5 235l.2 .3z"/>
<path d="M301.7 235.3v.5z"/>
<path d="M301.5 236l.2-.2z"/>
<path d="M300.8 236h.7z"/>
<path d="M302.2 235v1.5z"/>
<path d="M302.2 235h.8z"/>
<path d="M303 235l.2 .3z"/>
<path d="M303.2 235.3v.5z"/>
<path d="M303 236l.2-.2z"/>
<path d="M302.2 236h.8z"/>
<path d="M302.7 236l.5 .5z"/>
<path d="M304 235h.5z"/>
<path d="M304 235l-.3 .3z"/>
<path d="M303.7 235.3v1z"/>
<path d="M303.7 236.3l.3 .2z"/>
<path d="M304 236.5h.5z"/>
<path d="M304.5 236.5l.3-.2z"/>
<path d="M304.8 235.3v1z"/>
<path d="M304.5 235l.3 .3z"/>
<path d="M305.2 235v1.5z"/>
<path d="M305.2 235h.8z"/>
<path d="M306 235l.2 .3z"/>
<path d="M306.2 235.3v.5z"/>
<path d="M306.2 235.8l-.2 .2z"/>
<path d="M305.2 236h.8z"/>
<path d="M306.7 235v1.5z"/>
<path d="M306.7 235h.8z"/>
<path d="M307.5 235l.2 .3z"/>
<path d="M307.7 235.3v.5z"/>
<path d="M307.5 236l.2-.2z"/>
<path d="M306.7 236h.8z"/>
<path d="M307.2 236l.5 .5z"/>
<path d="M308.2 236.5h.5z"/>
<path d="M308.5 235v1.5z"/>
<path d="M308.2 235h.5z"/>
<path d="M309.2 235h1z"/>
<path d="M309.2 235v1.5z"/>
<path d="M309.2 236.5h1z"/>
<path d="M309.2 235.8h.5z"/>
<path d="M311.2 235v1.5z"/>
<path d="M310.7 235h1z"/>
<path d="M312.2 235.5v1z"/>
<path d="M312.2 235.5l.5-.5z"/>
<path d="M312.7 235l.5 .5z"/>
<path d="M313.2 235.5v1z"/>
<path d="M312.2 235.8h1z"/>
<path d="M313.7 235v1.5z"/>
<path d="M313.7 235h.8z"/>
<path d="M314.5 235l.2 .3z"/>
<path d="M314.7 235.3v.5z"/>
<path d="M314.7 235.8l-.2 .2z"/>
<path d="M313.7 236h.8z"/>
<path d="M314.2 236l.5 .5z"/>
<path d="M315.2 235v.3z"/>
<path d="M315.2 235.3l.5 .5z"/>
<path d="M315.7 235.8l.5-.5z"/>
<path d="M316.2 235v.3z"/>
<path d="M315.7 235.8v.7z"/>
<path d="M318.2 236.5h.5z"/>
<path d="M318.5 235v1.5z"/>
<path d="M318.2 235h.5z"/>
<path d="M319.2 235v1.5z"/>
<path d="M319.2 235l1 1.5z"/>
<path d="M320.2 235v1.5z"/>
<path d="M320.7 235v1.5z"/>
<path d="M320.7 235h1z"/>
<path d="M320.7 235.8h.5z"/>
<path d="M322.5 235h.5z"/>
<path d="M322.5 235l-.3 .3z"/>
<path d="M322.2 235.3v1z"/>
<path d="M322.2 236.3l.3 .2z"/>
<path d="M322.5 236.5h.5z"/>
<path d="M323 236.5l.2-.2z"/>
<path d="M323.2 235.3v1z"/>
<path d="M323 235l.2 .3z"/>
<path d="M323.7 235v1.5z"/>
<path d="M323.7 235h.8z"/>
<path d="M324.5 235l.2 .3z"/>
<path d="M324.7 235.3v.5z"/>
<path d="M324.5 236l.2-.2z"/>
<path d="M323.7 236h.8z"/>
<path d="M324.2 236l.5 .5z"/>
<path d="M325.2 235v1.5z"/>
<path d="M325.2 235l.5 .5z"/>
<path d="M325.7 235.5l.5-.5z"/>
<path d="M326.2 235v1.5z"/>
<path d="M326.7 235.5v1z"/>
<path d="M326.7 235.5l.5-.5z"/>
<path d="M327.2 235l.5 .5z"/>
<path d="M327.7 235.5v1z"/>
<path d="M326.7 235.8h1z"/>
<path d="M328.7 235v1.5z"/>
<path d="M328.2 235h1z"/>
<path d="M329.7 236.5h.5z"/>
<path d="M330 235v1.5z"/>
<path d="M329.7 235h.5z"/>
<path d="M331 235h.4z"/>
<path d="M331 235l-.3 .3z"/>
<path d="M330.7 235.3v1z"/>
<path d="M330.7 236.3l.3 .2z"/>
<path d="M331 236.5h.4z"/>
<path d="M331.4 236.5l.3-.2z"/>
<path d="M331.7 235.3v1z"/>
<path d="M331.4 235l.3 .3z"/>
<path d="M332.2 235v1.5z"/>
<path d="M332.2 235l1 1.5z"/>
<path d="M333.2 235v1.5z"/>
<path d="M335.2 235.5v1z"/>
<path d="M335.2 235.5l.5-.5z"/>
<path d="M335.7 235l.5 .5z"/>
<path d="M336.2 235.5v1z"/>
<path d="M335.2 235.8h1z"/>
<path d="M336.7 235v1.5z"/>
<path d="M336.7 235l1 1.5z"/>
<path d="M337.7 235v1.5z"/>
<path d="M338.2 235v1.5z"/>
<path d="M338.2 236.5h.7z"/>
<path d="M338.9 236.5l.3-.2z"/>
<path d="M339.2 235.3v1z"/>
<path d="M338.9 235l.3 .3z"/>
<path d="M338.2 235h.7z"/>
<path d="M341.2 236.5h.5z"/>
<path d="M341.4 235v1.5z"/>
<path d="M341.2 235h.5z"/>
<path d="M342.7 235v1.5z"/>
<path d="M342.2 235h1z"/>
<path d="M345.9 235l.3 .3z"/>
<path d="M345.4 235h.5z"/>
<path d="M345.4 235l-.2 .3z"/>
<path d="M345.2 235.3v.2z"/>
<path d="M345.2 235.5l.2 .3z"/>
<path d="M345.4 235.8h.5z"/>
<path d="M345.9 235.8l.3 .2z"/>
<path d="M346.2 236v.3z"/>
<path d="M346.2 236.3l-.3 .2z"/>
<path d="M345.4 236.5h.5z"/>
<path d="M345.2 236.3l.2 .2z"/>
<path d="M346.7 235v1.5z"/>
<path d="M346.7 235.8h1z"/>
<path d="M347.7 235v1.5z"/>
<path d="M348.2 235.5v1z"/>
<path d="M348.2 235.5l.5-.5z"/>
<path d="M348.7 235l.5 .5z"/>
<path d="M349.2 235.5v1z"/>
<path d="M348.2 235.8h1z"/>
<path d="M349.7 235v1.5z"/>
<path d="M349.7 236.5h1z"/>
<path d="M351.2 235v1.5z"/>
<path d="M351.2 236.5h1z"/>
<path d="M300.8 237.5v1.5z"/>
<path d="M300.8 237.5l.9 1.5z"/>
<path d="M301.7 237.5v1.5z"/>
<path d="M302.5 237.5h.5z"/>
<path d="M302.2 237.7l.3-.2z"/>
<path d="M302.2 237.7v1.1z"/>
<path d="M302.2 238.8l.3 .2z"/>
<path d="M302.5 239h.5z"/>
<path d="M303 239l.2-.2z"/>
<path d="M303.2 237.7v1.1z"/>
<path d="M303 237.5l.2 .2z"/>
<path d="M304.2 237.5v1.5z"/>
<path d="M303.7 237.5h1.1z"/>
<path d="M306.7 237.5v1.5z"/>
<path d="M306.7 237.5h.8z"/>
<path d="M307.5 237.5l.2 .2z"/>
<path d="M307.7 237.7v.3z"/>
<path d="M307.7 238l-.2 .2z"/>
<path d="M307.5 238.2l.2 .3z"/>
<path d="M307.7 238.5v.3z"/>
<path d="M307.7 238.8l-.2 .2z"/>
<path d="M306.7 239h.8z"/>
<path d="M306.7 238.2h.8z"/>
<path d="M308.2 237.5h1z"/>
<path d="M308.2 237.5v1.5z"/>
<path d="M308.2 239h1z"/>
<path d="M308.2 238.2h.5z"/>
<path d="M311.2 237.5v1.3z"/>
<path d="M311.2 238.8l.3 .2z"/>
<path d="M311.5 239h.5z"/>
<path d="M312.2 238.8l-.2 .2z"/>
<path d="M312.2 237.5v1.3z"/>
<path d="M313.5 237.5l.2 .2z"/>
<path d="M313 237.5h.5z"/>
<path d="M312.7 237.7l.3-.2z"/>
<path d="M312.7 237.7v.3z"/>
<path d="M312.7 238l.3 .2z"/>
<path d="M313 238.2h.5z"/>
<path d="M313.5 238.2l.2 .3z"/>
<path d="M313.7 238.5v.3z"/>
<path d="M313.7 238.8l-.2 .2z"/>
<path d="M313 239h.5z"/>
<path d="M312.7 238.8l.3 .2z"/>
<path d="M314.2 237.5h1z"/>
<path d="M314.2 237.5v1.5z"/>
<path d="M314.2 239h1z"/>
<path d="M314.2 238.2h.5z"/>
<path d="M315.7 237.5v1.5z"/>
<path d="M315.7 239h.8z"/>
<path d="M316.5 239l.2-.2z"/>
<path d="M316.7 237.7v1.1z"/>
<path d="M316.5 237.5l.2 .2z"/>
<path d="M315.7 237.5h.8z"/>
<path d="M319 237.5h.5z"/>
<path d="M318.7 237.7l.3-.2z"/>
<path d="M318.7 237.7v1.1z"/>
<path d="M318.7 238.8l.3 .2z"/>
<path d="M319 239h.5z"/>
<path d="M319.5 239l.2-.2z"/>
<path d="M319.7 237.7v1.1z"/>
<path d="M319.5 237.5l.2 .2z"/>
<path d="M320.2 237.5v1.5z"/>
<path d="M320.2 237.5h.8z"/>
<path d="M321 237.5l.2 .2z"/>
<path d="M321.2 237.7v.5z"/>
<path d="M321 238.5l.2-.3z"/>
<path d="M320.2 238.5h.8z"/>
<path d="M320.7 238.5l.5 .5z"/>
<path d="M323.2 237.5v1.5z"/>
<path d="M323.2 237.5h.8z"/>
<path d="M324 237.5l.2 .2z"/>
<path d="M324.2 237.7v.5z"/>
<path d="M324.2 238.2l-.2 .3z"/>
<path d="M323.2 238.5h.8z"/>
<path d="M323.7 238.5l.5 .5z"/>
<path d="M324.7 237.5h1z"/>
<path d="M324.7 237.5v1.5z"/>
<path d="M324.7 239h1z"/>
<path d="M324.7 238.2h.5z"/>
<path d="M326.2 237.5v1.5z"/>
<path d="M326.2 237.5h.8z"/>
<path d="M327 237.5l.2 .2z"/>
<path d="M327.2 237.7v.5z"/>
<path d="M327.2 238.2l-.2 .3z"/>
<path d="M326.2 238.5h.8z"/>
<path d="M327.7 237.5v1.5z"/>
<path d="M327.7 237.5h.8z"/>
<path d="M328.5 237.5l.2 .2z"/>
<path d="M328.7 237.7v.5z"/>
<path d="M328.7 238.2l-.2 .3z"/>
<path d="M327.7 238.5h.8z"/>
<path d="M328.2 238.5l.5 .5z"/>
<path d="M329.5 237.5h.5z"/>
<path d="M329.2 237.7l.3-.2z"/>
<path d="M329.2 237.7v1.1z"/>
<path d="M329.2 238.8l.3 .2z"/>
<path d="M329.5 239h.5z"/>
<path d="M330 239l.2-.2z"/>
<path d="M330.2 237.7v1.1z"/>
<path d="M330 237.5l.2 .2z"/>
<path d="M330.7 237.5v1.5z"/>
<path d="M330.7 239h.7z"/>
<path d="M331.4 239l.3-.2z"/>
<path d="M331.7 237.7v1.1z"/>
<path d="M331.4 237.5l.3 .2z"/>
<path d="M330.7 237.5h.7z"/>
<path d="M332.2 237.5v1.3z"/>
<path d="M332.2 238.8l.3 .2z"/>
<path d="M332.5 239h.4z"/>
<path d="M332.9 239l.3-.2z"/>
<path d="M333.2 237.5v1.3z"/>
<path d="M334.4 237.5l.3 .2z"/>
<path d="M333.9 237.5h.5z"/>
<path d="M333.7 237.7l.2-.2z"/>
<path d="M333.7 237.7v1.1z"/>
<path d="M333.7 238.8l.2 .2z"/>
<path d="M333.9 239h.5z"/>
<path d="M334.4 239l.3-.2z"/>
<path d="M335.2 237.5h1z"/>
<path d="M335.2 237.5v1.5z"/>
<path d="M335.2 239h1z"/>
<path d="M335.2 238.2h.5z"/>
<path d="M336.7 237.5v1.5z"/>
<path d="M336.7 239h.7z"/>
<path d="M337.4 239l.3-.2z"/>
<path d="M337.7 237.7v1.1z"/>
<path d="M337.4 237.5l.3 .2z"/>
<path d="M336.7 237.5h.7z"/>
<path d="M339.9 237.5h.5z"/>
<path d="M339.7 237.7l.2-.2z"/>
<path d="M339.7 237.7v1.1z"/>
<path d="M339.7 238.8l.2 .2z"/>
<path d="M339.9 239h.5z"/>
<path d="M340.4 239l.3-.2z"/>
<path d="M340.7 237.7v1.1z"/>
<path d="M340.4 237.5l.3 .2z"/>
<path d="M341.2 237.5v1.5z"/>
<path d="M341.2 237.5h.7z"/>
<path d="M341.9 237.5l.3 .2z"/>
<path d="M342.2 237.7v.5z"/>
<path d="M342.2 238.2l-.3 .3z"/>
<path d="M341.2 238.5h.7z"/>
<path d="M341.7 238.5l.5 .5z"/>
<path d="M344.2 239h.5z"/>
<path d="M344.4 237.5v1.5z"/>
<path d="M344.2 237.5h.5z"/>
<path d="M345.7 237.5v1.5z"/>
<path d="M345.2 237.5h1z"/>
<path d="M346.9 237.3v.4z"/>
<path d="M346.9 237.7l-.2 .3z"/>
<path d="M348.2 237.5l.2 .2z"/>
<path d="M347.7 237.5h.5z"/>
<path d="M347.4 237.7l.3-.2z"/>
<path d="M347.4 237.7v.3z"/>
<path d="M347.4 238l.3 .2z"/>
<path d="M347.7 238.2h.5z"/>
<path d="M348.2 238.2l.2 .3z"/>
<path d="M348.4 238.5v.3z"/>
<path d="M348.4 238.8l-.2 .2z"/>
<path d="M347.7 239h.5z"/>
<path d="M347.4 238.8l.3 .2z"/>
<path d="M301.5 240l.2 .2z"/>
<path d="M301 240h.5z"/>
<path d="M301 240l-.2 .2z"/>
<path d="M300.8 240.2v1z"/>
<path d="M300.8 241.2l.2 .3z"/>
<path d="M301 241.5h.5z"/>
<path d="M301.5 241.5l.2-.3z"/>
<path d="M302.5 240h.5z"/>
<path d="M302.5 240l-.3 .2z"/>
<path d="M302.2 240.2v1z"/>
<path d="M302.2 241.2l.3 .3z"/>
<path d="M302.5 241.5h.5z"/>
<path d="M303 241.5l.2-.3z"/>
<path d="M303.2 240.2v1z"/>
<path d="M303 240l.2 .2z"/>
<path d="M303.7 240v1.5z"/>
<path d="M303.7 240l1.1 1.5z"/>
<path d="M304.8 240v1.5z"/>
<path d="M305.7 240v1.5z"/>
<path d="M305.2 240h1z"/>
<path d="M306.7 240h1z"/>
<path d="M306.7 240v1.5z"/>
<path d="M306.7 241.5h1z"/>
<path d="M306.7 240.7h.5z"/>
<path d="M308.2 240v1.5z"/>
<path d="M308.2 240l1 1.5z"/>
<path d="M309.2 240v1.5z"/>
<path d="M310.2 240v1.5z"/>
<path d="M309.7 240h1z"/>
<path d="M312.7 240v1.5z"/>
<path d="M312.7 241.5h.8z"/>
<path d="M313.5 241.5l.2-.3z"/>
<path d="M313.7 240.2v1z"/>
<path d="M313.5 240l.2 .2z"/>
<path d="M312.7 240h.8z"/>
<path d="M314.2 241.5h.5z"/>
<path d="M314.5 240v1.5z"/>
<path d="M314.2 240h.5z"/>
<path d="M316 240l.2 .2z"/>
<path d="M315.5 240h.5z"/>
<path d="M315.5 240l-.3 .2z"/>
<path d="M315.2 240.2v.3z"/>
<path d="M315.2 240.5l.3 .2z"/>
<path d="M315.5 240.7h.5z"/>
<path d="M316 240.7l.2 .3z"/>
<path d="M316.2 241v.2z"/>
<path d="M316.2 241.2l-.2 .3z"/>
<path d="M315.5 241.5h.5z"/>
<path d="M315.2 241.2l.3 .3z"/>
<path d="M317.5 240l.2 .2z"/>
<path d="M317 240h.5z"/>
<path d="M317 240l-.3 .2z"/>
<path d="M316.7 240.2v1z"/>
<path d="M316.7 241.2l.3 .3z"/>
<path d="M317 241.5h.5z"/>
<path d="M317.5 241.5l.2-.3z"/>
<path d="M318.2 240v1.5z"/>
<path d="M318.2 241.5h1z"/>
<path d="M320 240h.5z"/>
<path d="M319.7 240.2l.3-.2z"/>
<path d="M319.7 240.2v1z"/>
<path d="M319.7 241.2l.3 .3z"/>
<path d="M320 241.5h.5z"/>
<path d="M320.7 241.2l-.2 .3z"/>
<path d="M320.7 240.2v1z"/>
<path d="M320.5 240l.2 .2z"/>
<path d="M322 240l.2 .2z"/>
<path d="M321.5 240h.5z"/>
<path d="M321.5 240l-.3 .2z"/>
<path d="M321.2 240.2v.3z"/>
<path d="M321.2 240.5l.3 .2z"/>
<path d="M321.5 240.7h.5z"/>
<path d="M322 240.7l.2 .3z"/>
<path d="M322.2 241v.2z"/>
<path d="M322.2 241.2l-.2 .3z"/>
<path d="M321.5 241.5h.5z"/>
<path d="M321.2 241.2l.3 .3z"/>
<path d="M322.7 240h1z"/>
<path d="M322.7 240v1.5z"/>
<path d="M322.7 241.5h1z"/>
<path d="M322.7 240.7h.5z"/>
<path d="M324.2 240v1.5z"/>
<path d="M324.2 241.5h.8z"/>
<path d="M325 241.5l.2-.3z"/>
<path d="M325.2 240.2v1z"/>
<path d="M325 240l.2 .2z"/>
<path d="M324.2 240h.8z"/>
<path d="M327.2 241.5h.5z"/>
<path d="M327.5 240v1.5z"/>
<path d="M327.2 240h.5z"/>
<path d="M328.2 240v1.5z"/>
<path d="M328.2 240l1 1.5z"/>
<path d="M329.2 240v1.5z"/>
<path d="M331.2 240v1.5z"/>
<path d="M331.2 241.5l.5-.5z"/>
<path d="M331.7 241l.5 .5z"/>
<path d="M332.2 240v1.5z"/>
<path d="M332.7 240v1.5z"/>
<path d="M332.7 240.7h1z"/>
<path d="M333.7 240v1.5z"/>
<path d="M334.4 240h.6z"/>
<path d="M334.4 240l-.2 .2z"/>
<path d="M334.2 240.2v1z"/>
<path d="M334.2 241.2l.2 .3z"/>
<path d="M334.4 241.5h.6z"/>
<path d="M335.2 241.2l-.2 .3z"/>
<path d="M335.2 240.2v1z"/>
<path d="M335 240l.2 .2z"/>
<path d="M335.7 240v1.5z"/>
<path d="M335.7 241.5h1z"/>
<path d="M337.2 240h1z"/>
<path d="M337.2 240v1.5z"/>
<path d="M337.2 241.5h1z"/>
<path d="M337.2 240.7h.5z"/>
<path d="M340.4 240h.5z"/>
<path d="M340.4 240l-.2 .2z"/>
<path d="M340.2 240.2v1z"/>
<path d="M340.2 241.2l.2 .3z"/>
<path d="M340.4 241.5h.5z"/>
<path d="M341.2 241.2l-.3 .3z"/>
<path d="M341.2 240.2v1z"/>
<path d="M340.9 240l.3 .2z"/>
<path d="M341.7 240v1.5z"/>
<path d="M341.7 240h.7z"/>
<path d="M342.4 240l.3 .2z"/>
<path d="M342.7 240.2v.5z"/>
<path d="M342.7 240.7l-.3 .3z"/>
<path d="M341.7 241h.7z"/>
<path d="M342.2 241l.5 .5z"/>
<path d="M344.7 241.5h.5z"/>
<path d="M344.9 240v1.5z"/>
<path d="M344.7 240h.5z"/>
<path d="M345.7 240v1.5z"/>
<path d="M345.7 240l1 1.5z"/>
<path d="M346.7 240v1.5z"/>
<path d="M348.7 240v1.5z"/>
<path d="M348.7 240h.7z"/>
<path d="M349.4 240l.3 .2z"/>
<path d="M349.7 240.2v.5z"/>
<path d="M349.7 240.7l-.3 .3z"/>
<path d="M348.7 241h.7z"/>
<path d="M350.2 240.5v1z"/>
<path d="M350.7 240l-.5 .5z"/>
<path d="M350.7 240l.5 .5z"/>
<path d="M351.2 240.5v1z"/>
<path d="M350.2 240.7h1z"/>
<path d="M351.7 240v1.5z"/>
<path d="M351.7 240h.7z"/>
<path d="M352.4 240l.3 .2z"/>
<path d="M352.7 240.2v.5z"/>
<path d="M352.7 240.7l-.3 .3z"/>
<path d="M351.7 241h.7z"/>
<path d="M352.2 241l.5 .5z"/>
<path d="M353.7 240v1.5z"/>
<path d="M353.2 240h1z"/>
<path d="M300.8 242.4v1.5z"/>
<path d="M300.8 243.9l.4-.5z"/>
<path d="M301.2 243.4l.5 .5z"/>
<path d="M301.7 242.4v1.5z"/>
<path d="M302.2 243.9h.5z"/>
<path d="M302.5 242.4v1.5z"/>
<path d="M302.2 242.4h.5z"/>
<path d="M303.7 242.4v1.5z"/>
<path d="M303.2 242.4h1z"/>
<path d="M304.7 242.4v1.5z"/>
<path d="M304.7 243.2h1z"/>
<path d="M305.7 242.4v1.5z"/>
<path d="M306.5 242.4h.5z"/>
<path d="M306.5 242.4l-.3 .3z"/>
<path d="M306.2 242.7v1z"/>
<path d="M306.2 243.7l.3 .2z"/>
<path d="M306.5 243.9h.5z"/>
<path d="M307 243.9l.3-.2z"/>
<path d="M307.3 242.7v1z"/>
<path d="M307 242.4l.3 .3z"/>
<path d="M307.7 242.4v1.3z"/>
<path d="M307.7 243.7l.3 .2z"/>
<path d="M308 243.9h.5z"/>
<path d="M308.5 243.9l.2-.2z"/>
<path d="M308.7 242.4v1.3z"/>
<path d="M309.7 242.4v1.5z"/>
<path d="M309.2 242.4h1z"/>
<path d="M312.7 242.4v1.5z"/>
<path d="M312.2 242.4h1z"/>
<path d="M313.7 242.4v1.5z"/>
<path d="M313.7 243.2h1z"/>
<path d="M314.7 242.4v1.5z"/>
<path d="M315.2 242.4h1z"/>
<path d="M315.2 242.4v1.5z"/>
<path d="M315.2 243.9h1z"/>
<path d="M315.2 243.2h.5z"/>
<path d="M318.2 242.4v1.5z"/>
<path d="M318.2 242.4h.8z"/>
<path d="M319 242.4l.2 .3z"/>
<path d="M319.2 242.7v.5z"/>
<path d="M319.2 243.2l-.2 .2z"/>
<path d="M318.2 243.4h.8z"/>
<path d="M319.7 242.4v1.5z"/>
<path d="M319.7 242.4h.8z"/>
<path d="M320.5 242.4l.2 .3z"/>
<path d="M320.7 242.7v.5z"/>
<path d="M320.7 243.2l-.2 .2z"/>
<path d="M319.7 243.4h.8z"/>
<path d="M320.2 243.4l.5 .5z"/>
<path d="M321.2 243.9h.5z"/>
<path d="M321.5 242.4v1.5z"/>
<path d="M321.2 242.4h.5z"/>
<path d="M322.5 242.4h.5z"/>
<path d="M322.5 242.4l-.3 .3z"/>
<path d="M322.2 242.7v1z"/>
<path d="M322.2 243.7l.3 .2z"/>
<path d="M322.5 243.9h.5z"/>
<path d="M323 243.9l.2-.2z"/>
<path d="M323.2 242.7v1z"/>
<path d="M323 242.4l.2 .3z"/>
<path d="M323.7 242.4v1.5z"/>
<path d="M323.7 242.4h.8z"/>
<path d="M324.5 242.4l.2 .3z"/>
<path d="M324.7 242.7v.5z"/>
<path d="M324.7 243.2l-.2 .2z"/>
<path d="M323.7 243.4h.8z"/>
<path d="M324.2 243.4l.5 .5z"/>
<path d="M326.7 242.4v1.5z"/>
<path d="M326.7 243.9l.5-.5z"/>
<path d="M327.2 243.4l.5 .5z"/>
<path d="M327.7 242.4v1.5z"/>
<path d="M328.2 242.4v1.5z"/>
<path d="M328.2 242.4h.8z"/>
<path d="M329 242.4l.2 .3z"/>
<path d="M329.2 242.7v.5z"/>
<path d="M329.2 243.2l-.2 .2z"/>
<path d="M328.2 243.4h.8z"/>
<path d="M328.7 243.4l.5 .5z"/>
<path d="M329.7 243.9h.5z"/>
<path d="M330 242.4v1.5z"/>
<path d="M329.7 242.4h.5z"/>
<path d="M331.2 242.4v1.5z"/>
<path d="M330.7 242.4h1z"/>
<path d="M332.7 242.4v1.5z"/>
<path d="M332.2 242.4h1z"/>
<path d="M333.7 242.4h1z"/>
<path d="M333.7 242.4v1.5z"/>
<path d="M333.7 243.9h1z"/>
<path d="M333.7 243.2h.5z"/>
<path d="M335.2 242.4v1.5z"/>
<path d="M335.2 242.4l1 1.5z"/>
<path d="M336.2 242.4v1.5z"/>
<path d="M338.9 242.4l.3 .3z"/>
<path d="M338.4 242.4h.5z"/>
<path d="M338.4 242.4l-.2 .3z"/>
<path d="M338.2 242.7v1z"/>
<path d="M338.2 243.7l.2 .2z"/>
<path d="M338.4 243.9h.5z"/>
<path d="M338.9 243.9l.3-.2z"/>
<path d="M339.9 242.4h.5z"/>
<path d="M339.9 242.4l-.2 .3z"/>
<path d="M339.7 242.7v1z"/>
<path d="M339.7 243.7l.2 .2z"/>
<path d="M339.9 243.9h.5z"/>
<path d="M340.4 243.9l.3-.2z"/>
<path d="M340.7 242.7v1z"/>
<path d="M340.4 242.4l.3 .3z"/>
<path d="M341.2 242.4v1.5z"/>
<path d="M341.2 242.4l1 1.5z"/>
<path d="M342.2 242.4v1.5z"/>
<path d="M343.4 242.4l.3 .3z"/>
<path d="M342.9 242.4h.5z"/>
<path d="M342.9 242.4l-.2 .3z"/>
<path d="M342.7 242.7v.2z"/>
<path d="M342.7 242.9l.2 .3z"/>
<path d="M342.9 243.2h.5z"/>
<path d="M343.4 243.2l.3 .2z"/>
<path d="M343.7 243.4v.3z"/>
<path d="M343.7 243.7l-.3 .2z"/>
<path d="M342.9 243.9h.5z"/>
<path d="M342.7 243.7l.2 .2z"/>
<path d="M344.2 242.4h1z"/>
<path d="M344.2 242.4v1.5z"/>
<path d="M344.2 243.9h1z"/>
<path d="M344.2 243.2h.5z"/>
<path d="M345.7 242.4v1.5z"/>
<path d="M345.7 242.4l1 1.5z"/>
<path d="M346.7 242.4v1.5z"/>
<path d="M347.7 242.4v1.5z"/>
<path d="M347.2 242.4h1z"/>
<path d="M350.4 242.4h.5z"/>
<path d="M350.4 242.4l-.2 .3z"/>
<path d="M350.2 242.7v1z"/>
<path d="M350.2 243.7l.2 .2z"/>
<path d="M350.4 243.9h.5z"/>
<path d="M350.9 243.9l.3-.2z"/>
<path d="M351.2 242.7v1z"/>
<path d="M350.9 242.4l.3 .3z"/>
<path d="M351.7 242.4v1.5z"/>
<path d="M351.7 242.4h1z"/>
<path d="M351.7 243.2h.5z"/>
<path d="M300.8 244.9v1.5z"/>
<path d="M300.8 246.4h.7z"/>
<path d="M301.5 246.4l.2-.3z"/>
<path d="M301.7 245.1v1z"/>
<path d="M301.5 244.9l.2 .2z"/>
<path d="M300.8 244.9h.7z"/>
<path d="M302.2 245.4v1z"/>
<path d="M302.7 244.9l-.5 .5z"/>
<path d="M302.7 244.9l.5 .5z"/>
<path d="M303.2 245.4v1z"/>
<path d="M302.2 245.6h1z"/>
<path d="M303.7 244.9v1.5z"/>
<path d="M303.7 244.9l1.1 1.5z"/>
<path d="M304.8 244.9v1.5z"/>
<path d="M306.7 244.9v1.5z"/>
<path d="M306.7 245.9l1-1z"/>
<path d="M307 245.6l.7 .8z"/>
<path d="M308.2 246.4h.5z"/>
<path d="M308.5 244.9v1.5z"/>
<path d="M308.2 244.9h.5z"/>
<path d="M309.2 244.9v1.5z"/>
<path d="M309.2 244.9h.8z"/>
<path d="M310 244.9l.2 .2z"/>
<path d="M310.2 245.1v.5z"/>
<path d="M310.2 245.6l-.2 .3z"/>
<path d="M309.2 245.9h.8z"/>
<path d="M309.7 245.9l.5 .5z"/>
<path d="M310.7 244.9v1.5z"/>
<path d="M310.7 245.9l1-1z"/>
<path d="M311 245.6l.7 .8z"/>
<path d="M312.2 244.9v1.5z"/>
<path d="M312.2 244.9h.8z"/>
<path d="M313 244.9l.2 .2z"/>
<path d="M313.2 245.1v.5z"/>
<path d="M313.2 245.6l-.2 .3z"/>
<path d="M312.2 245.9h.8z"/>
<path d="M313.7 245.4v1z"/>
<path d="M313.7 245.4l.5-.5z"/>
<path d="M314.2 244.9l.5 .5z"/>
<path d="M314.7 245.4v1z"/>
<path d="M313.7 245.6h1z"/>
<path d="M315.7 244.9v1.5z"/>
<path d="M315.2 244.9h1z"/>
<path d="M316.7 244.9v1.5z"/>
<path d="M316.7 244.9h.8z"/>
<path d="M317.5 244.9l.2 .2z"/>
<path d="M317.7 245.1v.5z"/>
<path d="M317.7 245.6l-.2 .3z"/>
<path d="M316.7 245.9h.8z"/>
<path d="M317.2 245.9l.5 .5z"/>
<path d="M318.2 246.4h.5z"/>
<path d="M318.5 244.9v1.5z"/>
<path d="M318.2 244.9h.5z"/>
<path d="M320 244.9l.2 .2z"/>
<path d="M319.5 244.9h.5z"/>
<path d="M319.5 244.9l-.3 .2z"/>
<path d="M319.2 245.1v1z"/>
<path d="M319.2 246.1l.3 .3z"/>
<path d="M319.5 246.4h.5z"/>
<path d="M320 246.4l.2-.3z"/>
<path d="M320.7 244.9v1.5z"/>
<path d="M320.7 245.9l1-1z"/>
<path d="M321 245.6l.7 .8z"/>
<path d="M271.2 19.5v1.1z"/>
<path d="M271.2 19.5l.3-.3z"/>
<path d="M271.5 19.2h.5z"/>
<path d="M272 19.2l.3 .3z"/>
<path d="M272.3 19.5v1.1z"/>
<path d="M272 20.9l.3-.3z"/>
<path d="M271.5 20.9h.5z"/>
<path d="M271.2 20.6l.3 .3z"/>
<path d="M271.2 20.6l1.1-1.1z"/>
<path d="M272.9 19.5v1.1z"/>
<path d="M272.9 19.5l.3-.3z"/>
<path d="M273.2 19.2h.5z"/>
<path d="M273.7 19.2l.3 .3z"/>
<path d="M274 19.5v1.1z"/>
<path d="M274 20.6l-.3 .3z"/>
<path d="M273.2 20.9h.5z"/>
<path d="M272.9 20.6l.3 .3z"/>
<path d="M272.9 20.6l1.1-1.1z"/>
<path d="M274.6 19.8l.6-.6z"/>
<path d="M275.2 19.2v1.7z"/>
<path d="M274.6 20.9h1.1z"/>
<path d="M320.7 248.4v1.7z"/>
<path d="M320.7 250.1h.9z"/>
<path d="M321.6 250.1l.3-.3z"/>
<path d="M321.9 248.7v1.1z"/>
<path d="M321.6 248.4l.3 .3z"/>
<path d="M320.7 248.4h.9z"/>
<path d="M322.4 248.9v1.2z"/>
<path d="M322.4 248.9l.6-.5z"/>
<path d="M323 248.4l.5 .5z"/>
<path d="M323.5 248.9v1.2z"/>
<path d="M322.4 249.2h1.1z"/>
<path d="M324.1 248.4v1.7z"/>
<path d="M324.1 248.4l1.2 1.7z"/>
<path d="M325.3 248.4v1.7z"/>
<path d="M327.5 248.4v1.7z"/>
<path d="M327.5 249.5l1.2-1.1z"/>
<path d="M327.8 249.2l.9 .9z"/>
<path d="M329.2 250.1h.6z"/>
<path d="M329.5 248.4v1.7z"/>
<path d="M329.2 248.4h.6z"/>
<path d="M330.4 248.4v1.7z"/>
<path d="M330.4 248.4h.8z"/>
<path d="M331.2 248.4l.3 .3z"/>
<path d="M331.5 248.7v.5z"/>
<path d="M331.2 249.5l.3-.3z"/>
<path d="M330.4 249.5h.8z"/>
<path d="M330.9 249.5l.6 .6z"/>
<path d="M332.1 248.4v1.7z"/>
<path d="M332.1 249.5l1.1-1.1z"/>
<path d="M332.4 249.2l.8 .9z"/>
<path d="M333.8 248.4v1.7z"/>
<path d="M333.8 248.4h.8z"/>
<path d="M334.6 248.4l.3 .3z"/>
<path d="M334.9 248.7v.5z"/>
<path d="M334.9 249.2l-.3 .3z"/>
<path d="M333.8 249.5h.8z"/>
<path d="M335.5 248.9v1.2z"/>
<path d="M335.5 248.9l.5-.5z"/>
<path d="M336 248.4l.6 .5z"/>
<path d="M336.6 248.9v1.2z"/>
<path d="M335.5 249.2h1.1z"/>
<path d="M337.7 248.4v1.7z"/>
<path d="M337.2 248.4h1.1z"/>
<path d="M338.9 248.4v1.7z"/>
<path d="M338.9 248.4h.8z"/>
<path d="M339.7 248.4l.3 .3z"/>
<path d="M340 248.7v.5z"/>
<path d="M339.7 249.5l.3-.3z"/>
<path d="M338.9 249.5h.8z"/>
<path d="M339.4 249.5l.6 .6z"/>
<path d="M340.6 250.1h.5z"/>
<path d="M340.9 248.4v1.7z"/>
<path d="M340.6 248.4h.5z"/>
<path d="M342.6 248.4l.3 .3z"/>
<path d="M342 248.4h.6z"/>
<path d="M342 248.4l-.3 .3z"/>
<path d="M341.7 248.7v1.1z"/>
<path d="M341.7 249.8l.3 .3z"/>
<path d="M342 250.1h.6z"/>
<path d="M342.6 250.1l.3-.3z"/>
<path d="M343.4 248.4v1.7z"/>
<path d="M343.4 249.5l1.1-1.1z"/>
<path d="M343.7 249.2l.8 .9z"/>
<path d="M320.7 251.3v1.7z"/>
<path d="M320.7 253h.9z"/>
<path d="M321.9 252.7l-.3 .3z"/>
<path d="M321.9 251.6v1.1z"/>
<path d="M321.6 251.3l.3 .3z"/>
<path d="M320.7 251.3h.9z"/>
<path d="M322.4 251.9v1.1z"/>
<path d="M323 251.3l-.6 .6z"/>
<path d="M323 251.3l.5 .6z"/>
<path d="M323.5 251.9v1.1z"/>
<path d="M322.4 252.2h1.1z"/>
<path d="M324.1 251.3v1.7z"/>
<path d="M324.1 251.3l1.2 1.7z"/>
<path d="M325.3 251.3v1.7z"/>
<path d="M327.5 251.3v1.7z"/>
<path d="M327.5 252.5l1.2-1.2z"/>
<path d="M327.8 252.2l.9 .8z"/>
<path d="M329.2 253h.6z"/>
<path d="M329.5 251.3v1.7z"/>
<path d="M329.2 251.3h.6z"/>
<path d="M330.4 251.3v1.7z"/>
<path d="M330.4 251.3h.8z"/>
<path d="M331.2 251.3l.3 .3z"/>
<path d="M331.5 251.6v.6z"/>
<path d="M331.5 252.2l-.3 .3z"/>
<path d="M330.4 252.5h.8z"/>
<path d="M330.9 252.5l.6 .5z"/>
<path d="M332.1 251.3v1.7z"/>
<path d="M333.2 251.3l-1.1 1.2z"/>
<path d="M332.4 252.2l.8 .8z"/>
<path d="M333.8 251.3v1.7z"/>
<path d="M333.8 251.3h.8z"/>
<path d="M334.6 251.3l.3 .3z"/>
<path d="M334.9 251.6v.6z"/>
<path d="M334.9 252.2l-.3 .3z"/>
<path d="M333.8 252.5h.8z"/>
<path d="M335.5 251.9v1.1z"/>
<path d="M335.5 251.9l.5-.6z"/>
<path d="M336 251.3l.6 .6z"/>
<path d="M336.6 251.9v1.1z"/>
<path d="M335.5 252.2h1.1z"/>
<path d="M337.7 251.3v1.7z"/>
<path d="M337.2 251.3h1.1z"/>
<path d="M338.9 251.3v1.7z"/>
<path d="M338.9 251.3h.8z"/>
<path d="M339.7 251.3l.3 .3z"/>
<path d="M340 251.6v.6z"/>
<path d="M340 252.2l-.3 .3z"/>
<path d="M338.9 252.5h.8z"/>
<path d="M339.4 252.5l.6 .5z"/>
<path d="M340.6 253h.5z"/>
<path d="M340.9 251.3v1.7z"/>
<path d="M340.6 251.3h.5z"/>
<path d="M342.6 251.3l.3 .3z"/>
<path d="M342 251.3h.6z"/>
<path d="M342 251.3l-.3 .3z"/>
<path d="M341.7 251.6v1.1z"/>
<path d="M341.7 252.7l.3 .3z"/>
<path d="M342 253h.6z"/>
<path d="M342.6 253l.3-.3z"/>
<path d="M343.4 251.3v1.7z"/>
<path d="M343.4 252.5l1.1-1.2z"/>
<path d="M343.7 252.2l.8 .8z"/>
<path d="M320.7 254.5v1.7z"/>
<path d="M320.7 256.2h.9z"/>
<path d="M321.6 256.2l.3-.2z"/>
<path d="M321.9 254.8v1.2z"/>
<path d="M321.6 254.5l.3 .3z"/>
<path d="M320.7 254.5h.9z"/>
<path d="M322.4 255.1v1.1z"/>
<path d="M322.4 255.1l.6-.6z"/>
<path d="M323 254.5l.5 .6z"/>
<path d="M323.5 255.1v1.1z"/>
<path d="M322.4 255.4h1.1z"/>
<path d="M324.1 254.5v1.7z"/>
<path d="M324.1 254.5l1.2 1.7z"/>
<path d="M325.3 254.5v1.7z"/>
<path d="M327.5 254.5v1.7z"/>
<path d="M327.5 255.7l1.2-1.2z"/>
<path d="M327.8 255.4l.9 .8z"/>
<path d="M329.2 256.2h.6z"/>
<path d="M329.5 254.5v1.7z"/>
<path d="M329.2 254.5h.6z"/>
<path d="M330.4 254.5v1.7z"/>
<path d="M330.4 254.5h.8z"/>
<path d="M331.2 254.5l.3 .3z"/>
<path d="M331.5 254.8v.6z"/>
<path d="M331.2 255.7l.3-.3z"/>
<path d="M330.4 255.7h.8z"/>
<path d="M330.9 255.7l.6 .5z"/>
<path d="M332.1 254.5v1.7z"/>
<path d="M332.1 255.7l1.1-1.2z"/>
<path d="M332.4 255.4l.8 .8z"/>
<path d="M333.8 254.5v1.7z"/>
<path d="M333.8 254.5h.8z"/>
<path d="M334.6 254.5l.3 .3z"/>
<path d="M334.9 254.8v.6z"/>
<path d="M334.9 255.4l-.3 .3z"/>
<path d="M333.8 255.7h.8z"/>
<path d="M335.5 255.1v1.1z"/>
<path d="M335.5 255.1l.5-.6z"/>
<path d="M336 254.5l.6 .6z"/>
<path d="M336.6 255.1v1.1z"/>
<path d="M335.5 255.4h1.1z"/>
<path d="M337.7 254.5v1.7z"/>
<path d="M337.2 254.5h1.1z"/>
<path d="M338.9 254.5v1.7z"/>
<path d="M338.9 254.5h.8z"/>
<path d="M339.7 254.5l.3 .3z"/>
<path d="M340 254.8v.6z"/>
<path d="M339.7 255.7l.3-.3z"/>
<path d="M338.9 255.7h.8z"/>
<path d="M339.4 255.7l.6 .5z"/>
<path d="M340.6 256.2h.5z"/>
<path d="M340.9 254.5v1.7z"/>
<path d="M340.6 254.5h.5z"/>
<path d="M342.6 254.5l.3 .3z"/>
<path d="M342 254.5h.6z"/>
<path d="M342 254.5l-.3 .3z"/>
<path d="M341.7 254.8v1.2z"/>
<path d="M341.7 256l.3 .2z"/>
<path d="M342 256.2h.6z"/>
<path d="M342.6 256.2l.3-.2z"/>
<path d="M343.4 254.5v1.7z"/>
<path d="M343.4 255.7l1.1-1.2z"/>
<path d="M343.7 255.4l.8 .8z"/>
<path d="M122 50.5h4.9z"/>
<path d="M122 55.5h4.9z"/>
<path d="M122 60.4h4.9z"/>
<path d="M122 65.3h4.9z"/>
<path d="M97.4 50.5h4.9z"/>
<path d="M97.4 55.5h4.9z"/>
<path d="M97.4 60.4h4.9z"/>
<path d="M97.4 65.3h4.9z"/>
<path d="M94.9 28.4v2.4z"/>
<path d="M85 45.6v2.5z"/>
<path d="M80.1 82.6v2.4z"/>
<path d="M284.7 87.5v2.5z"/>
<path d="M85 35.7v2.5z"/>
<path d="M85 40.7v2.5z"/>
<path d="M85 38.2v.5z"/>
<path d="M85 40.2v.5z"/>
<path d="M136.8 43.2v2.4z"/>
<path d="M136.8 48.1v2.4z"/>
<path d="M136.8 45.6v.5z"/>
<path d="M136.8 47.6v.5z"/>
<path d="M375.9 53v2.5z"/>
<path d="M375.9 57.9v2.5z"/>
<path d="M375.9 55.5v.5z"/>
<path d="M375.9 57.4v.5z"/>
<path d="M85 55.5h2.5z"/>
<path d="M77.6 55.5h2.5z"/>
<path d="M80.5 54.5l-.4 1z"/>
<path d="M80.5 54.5l.6 2z"/>
<path d="M81.7 54.5l-.6 2z"/>
<path d="M81.7 54.5l.6 2z"/>
<path d="M83 54.5l-.7 2z"/>
<path d="M83 54.5l.6 2z"/>
<path d="M84.2 54.5l-.6 2z"/>
<path d="M84.2 54.5l.6 2z"/>
<path d="M85 55.5l-.2 1z"/>
<path d="M72.7 62.9v2.4z"/>
<path d="M72.7 70.3v2.4z"/>
<path d="M71.7 69.9l1 .4z"/>
<path d="M71.7 69.9l2-.6z"/>
<path d="M71.7 68.7l2 .6z"/>
<path d="M71.7 68.7l2-.7z"/>
<path d="M71.7 67.4l2 .6z"/>
<path d="M71.7 67.4l2-.6z"/>
<path d="M71.7 66.2l2 .6z"/>
<path d="M71.7 66.2l2-.6z"/>
<path d="M72.7 65.3l1 .3z"/>
<path d="M80.1 62.9v2.4z"/>
<path d="M80.1 70.3v2.4z"/>
<path d="M79.1 69.9l1 .4z"/>
<path d="M79.1 69.9l2-.6z"/>
<path d="M79.1 68.7l2 .6z"/>
<path d="M79.1 68.7l2-.7z"/>
<path d="M79.1 67.4l2 .6z"/>
<path d="M79.1 67.4l2-.6z"/>
<path d="M79.1 66.2l2 .6z"/>
<path d="M79.1 66.2l2-.6z"/>
<path d="M80.1 65.3l1 .3z"/>
<path d="M109.7 40.7h2.4z"/>
<path d="M102.3 40.7h2.5z"/>
<path d="M105.1 39.7l-.3 1z"/>
<path d="M105.1 39.7l.6 2z"/>
<path d="M106.4 39.7l-.7 2z"/>
<path d="M106.4 39.7l.6 2z"/>
<path d="M107.6 39.7l-.6 2z"/>
<path d="M107.6 39.7l.6 2z"/>
<path d="M108.8 39.7l-.6 2z"/>
<path d="M108.8 39.7l.6 2z"/>
<path d="M109.7 40.7l-.3 1z"/>
<path d="M181.2 28.4v2.4z"/>
<path d="M181.2 35.7v2.5z"/>
<path d="M180.2 35.4l1 .3z"/>
<path d="M180.2 35.4l1.9-.6z"/>
<path d="M180.2 34.2l1.9 .6z"/>
<path d="M180.2 34.2l1.9-.7z"/>
<path d="M180.2 32.9l1.9 .6z"/>
<path d="M180.2 32.9l1.9-.6z"/>
<path d="M180.2 31.7l1.9 .6z"/>
<path d="M180.2 31.7l1.9-.6z"/>
<path d="M181.2 30.8l.9 .3z"/>
<path d="M114.6 40.7h2.5z"/>
<path d="M117.1 40.7h2.4z"/>
<path d="M92.4 60.4h2.5z"/>
<path d="M85 60.4h2.5z"/>
<path d="M87.9 59.4l-.4 1z"/>
<path d="M87.9 59.4l.6 2z"/>
<path d="M89.1 59.4l-.6 2z"/>
<path d="M89.1 59.4l.6 2z"/>
<path d="M90.3 59.4l-.6 2z"/>
<path d="M90.3 59.4l.7 2z"/>
<path d="M91.6 59.4l-.6 2z"/>
<path d="M91.6 59.4l.6 2z"/>
<path d="M92.4 60.4l-.2 1z"/>
<path d="M31.6 237.3v1.1z"/>
<path d="M31.6 237.3h.6z"/>
<path d="M32.2 237.3l.2 .1z"/>
<path d="M32.4 237.4v.4z"/>
<path d="M32.4 237.8l-.2 .2z"/>
<path d="M31.6 238h.6z"/>
<path d="M32.7 237.6v.8z"/>
<path d="M33.1 237.3l-.4 .3z"/>
<path d="M33.1 237.3l.4 .3z"/>
<path d="M33.5 237.6v.8z"/>
<path d="M32.7 237.8h.8z"/>
<path d="M34.4 237.3l.2 .1z"/>
<path d="M34.1 237.3h.3z"/>
<path d="M34.1 237.3l-.2 .1z"/>
<path d="M33.9 237.4v.8z"/>
<path d="M33.9 238.2l.2 .2z"/>
<path d="M34.1 238.4h.3z"/>
<path d="M34.4 238.4l.2-.2z"/>
<path d="M34.6 237.8v.4z"/>
<path d="M34.2 237.8h.4z"/>
<path d="M35 237.3h.8z"/>
<path d="M35 237.3v1.1z"/>
<path d="M35 238.4h.8z"/>
<path d="M35 237.8h.4z"/>
<path d="M36.1 237.6l.4-.3z"/>
<path d="M36.5 237.3v1.1z"/>
<path d="M36.1 238.4h.8z"/>
<path d="M122 124.5h4.9z"/>
<path d="M122 129.4h4.9z"/>
<path d="M122 134.3h4.9z"/>
<path d="M122 139.3h4.9z"/>
<path d="M97.4 124.5h4.9z"/>
<path d="M97.4 129.4h4.9z"/>
<path d="M97.4 134.3h4.9z"/>
<path d="M97.4 139.3h4.9z"/>
<path d="M94.9 102.3v2.5z"/>
<path d="M85 119.5v2.5z"/>
<path d="M80.1 156.5v2.5z"/>
<path d="M85 109.7v2.5z"/>
<path d="M85 114.6v2.5z"/>
<path d="M85 112.2v.4z"/>
<path d="M85 114.1v.5z"/>
<path d="M136.8 117.1v2.4z"/>
<path d="M136.8 122v2.5z"/>
<path d="M136.8 119.5v.5z"/>
<path d="M136.8 121.5v.5z"/>
<path d="M375.9 126.9v2.5z"/>
<path d="M375.9 131.9v2.4z"/>
<path d="M375.9 129.4v.5z"/>
<path d="M375.9 131.4v.5z"/>
<path d="M85 129.4h2.5z"/>
<path d="M77.6 129.4h2.5z"/>
<path d="M80.5 128.4l-.4 1z"/>
<path d="M80.5 128.4l.6 2z"/>
<path d="M81.7 128.4l-.6 2z"/>
<path d="M81.7 128.4l.6 2z"/>
<path d="M83 128.4l-.7 2z"/>
<path d="M83 128.4l.6 2z"/>
<path d="M84.2 128.4l-.6 2z"/>
<path d="M84.2 128.4l.6 2z"/>
<path d="M85 129.4l-.2 1z"/>
<path d="M72.7 136.8v2.5z"/>
<path d="M72.7 144.2v2.5z"/>
<path d="M71.7 143.8l1 .4z"/>
<path d="M71.7 143.8l2-.6z"/>
<path d="M71.7 142.6l2 .6z"/>
<path d="M71.7 142.6l2-.6z"/>
<path d="M71.7 141.3l2 .7z"/>
<path d="M71.7 141.3l2-.6z"/>
<path d="M71.7 140.1l2 .6z"/>
<path d="M71.7 140.1l2-.6z"/>
<path d="M72.7 139.3l1 .2z"/>
<path d="M80.1 136.8v2.5z"/>
<path d="M80.1 144.2v2.5z"/>
<path d="M79.1 143.8l1 .4z"/>
<path d="M79.1 143.8l2-.6z"/>
<path d="M79.1 142.6l2 .6z"/>
<path d="M79.1 142.6l2-.6z"/>
<path d="M79.1 141.3l2 .7z"/>
<path d="M79.1 141.3l2-.6z"/>
<path d="M79.1 140.1l2 .6z"/>
<path d="M79.1 140.1l2-.6z"/>
<path d="M80.1 139.3l1 .2z"/>
<path d="M109.7 114.6h2.4z"/>
<path d="M102.3 114.6h2.5z"/>
<path d="M105.1 113.6l-.3 1z"/>
<path d="M105.1 113.6l.6 2z"/>
<path d="M106.4 113.6l-.7 2z"/>
<path d="M106.4 113.6l.6 2z"/>
<path d="M107.6 113.6l-.6 2z"/>
<path d="M107.6 113.6l.6 2z"/>
<path d="M108.8 113.6l-.6 2z"/>
<path d="M108.8 113.6l.6 2z"/>
<path d="M109.7 114.6l-.3 1z"/>
<path d="M181.2 109.7v2.5z"/>
<path d="M181.2 102.3v2.5z"/>
<path d="M181.2 104.8l.9 .3z"/>
<path d="M180.2 105.7l1.9-.6z"/>
<path d="M180.2 105.7l1.9 .7z"/>
<path d="M180.2 107l1.9-.6z"/>
<path d="M180.2 107l1.9 .6z"/>
<path d="M180.2 108.2l1.9-.6z"/>
<path d="M180.2 108.2l1.9 .6z"/>
<path d="M180.2 109.4l1.9-.6z"/>
<path d="M180.2 109.4l1 .3z"/>
<path d="M114.6 114.6h2.5z"/>
<path d="M117.1 114.6h2.4z"/>
<path d="M92.4 134.3h2.5z"/>
<path d="M85 134.3h2.5z"/>
<path d="M87.9 133.3l-.4 1z"/>
<path d="M87.9 133.3l.6 2z"/>
<path d="M89.1 133.3l-.6 2z"/>
<path d="M89.1 133.3l.6 2z"/>
<path d="M90.3 133.3l-.6 2z"/>
<path d="M90.3 133.3l.7 2z"/>
<path d="M91.6 133.3l-.6 2z"/>
<path d="M91.6 133.3l.6 2z"/>
<path d="M92.4 134.3l-.2 1z"/>
<path d="M122 198.4h4.9z"/>
<path d="M122 203.3h4.9z"/>
<path d="M122 208.3h4.9z"/>
<path d="M122 213.2h4.9z"/>
<path d="M97.4 198.4h4.9z"/>
<path d="M97.4 203.3h4.9z"/>
<path d="M97.4 208.3h4.9z"/>
<path d="M97.4 213.2h4.9z"/>
<path d="M94.9 176.2v2.5z"/>
<path d="M85 193.5v2.4z"/>
<path d="M80.1 230.4v2.5z"/>
<path d="M85 183.6v2.5z"/>
<path d="M85 188.5v2.5z"/>
<path d="M85 186.1v.5z"/>
<path d="M85 188v.5z"/>
<path d="M136.8 191v2.5z"/>
<path d="M136.8 195.9v2.5z"/>
<path d="M136.8 193.5v.5z"/>
<path d="M136.8 195.4v.5z"/>
<path d="M378.3 200.9v2.4z"/>
<path d="M378.3 205.8v2.5z"/>
<path d="M378.3 203.3v.5z"/>
<path d="M378.3 205.3v.5z"/>
<path d="M85 203.3h2.5z"/>
<path d="M77.6 203.3h2.5z"/>
<path d="M80.5 202.3l-.4 1z"/>
<path d="M80.5 202.3l.6 2z"/>
<path d="M81.7 202.3l-.6 2z"/>
<path d="M81.7 202.3l.6 2z"/>
<path d="M83 202.3l-.7 2z"/>
<path d="M83 202.3l.6 2z"/>
<path d="M84.2 202.3l-.6 2z"/>
<path d="M84.2 202.3l.6 2z"/>
<path d="M85 203.3l-.2 1z"/>
<path d="M72.7 210.7v2.5z"/>
<path d="M72.7 218.1v2.5z"/>
<path d="M71.7 217.7l1 .4z"/>
<path d="M71.7 217.7l2-.6z"/>
<path d="M71.7 216.5l2 .6z"/>
<path d="M71.7 216.5l2-.6z"/>
<path d="M71.7 215.3l2 .6z"/>
<path d="M71.7 215.3l2-.6z"/>
<path d="M71.7 214.1l2 .6z"/>
<path d="M71.7 214.1l2-.7z"/>
<path d="M72.7 213.2l1 .2z"/>
<path d="M80.1 210.7v2.5z"/>
<path d="M80.1 218.1v2.5z"/>
<path d="M79.1 217.7l1 .4z"/>
<path d="M79.1 217.7l2-.6z"/>
<path d="M79.1 216.5l2 .6z"/>
<path d="M79.1 216.5l2-.6z"/>
<path d="M79.1 215.3l2 .6z"/>
<path d="M79.1 215.3l2-.6z"/>
<path d="M79.1 214.1l2 .6z"/>
<path d="M79.1 214.1l2-.7z"/>
<path d="M80.1 213.2l1 .2z"/>
<path d="M109.7 188.5h2.4z"/>
<path d="M102.3 188.5h2.5z"/>
<path d="M105.1 187.6l-.3 .9z"/>
<path d="M105.1 187.6l.6 1.9z"/>
<path d="M106.4 187.6l-.7 1.9z"/>
<path d="M106.4 187.6l.6 1.9z"/>
<path d="M107.6 187.6l-.6 1.9z"/>
<path d="M107.6 187.6l.6 1.9z"/>
<path d="M108.8 187.6l-.6 1.9z"/>
<path d="M108.8 187.6l.6 1.9z"/>
<path d="M109.7 188.5l-.3 1z"/>
<path d="M181.2 176.2v2.5z"/>
<path d="M181.2 183.6v2.5z"/>
<path d="M180.2 183.2l1 .4z"/>
<path d="M180.2 183.2l1.9-.6z"/>
<path d="M180.2 182l1.9 .6z"/>
<path d="M180.2 182l1.9-.6z"/>
<path d="M180.2 180.8l1.9 .6z"/>
<path d="M180.2 180.8l1.9-.6z"/>
<path d="M180.2 179.6l1.9 .6z"/>
<path d="M180.2 179.6l1.9-.7z"/>
<path d="M181.2 178.7l.9 .2z"/>
<path d="M114.6 188.5h2.5z"/>
<path d="M117.1 188.5h2.4z"/>
<path d="M168.8 230.4h2.5z"/>
<path d="M176.2 230.4h2.5z"/>
<path d="M176.2 230.4l-.4 1z"/>
<path d="M175.2 229.4l.6 2z"/>
<path d="M175.2 229.4l-.6 2z"/>
<path d="M174 229.4l.6 2z"/>
<path d="M174 229.4l-.6 2z"/>
<path d="M172.8 229.4l.6 2z"/>
<path d="M172.8 229.4l-.6 2z"/>
<path d="M171.6 229.4l.6 2z"/>
<path d="M171.6 229.4l-.3 1z"/>
<path d="M92.4 208.3h2.5z"/>
<path d="M85 208.3h2.5z"/>
<path d="M87.9 207.3l-.4 1z"/>
<path d="M87.9 207.3l.6 2z"/>
<path d="M89.1 207.3l-.6 2z"/>
<path d="M89.1 207.3l.6 2z"/>
<path d="M90.3 207.3l-.6 2z"/>
<path d="M90.3 207.3l.7 2z"/>
<path d="M91.6 207.3l-.6 2z"/>
<path d="M91.6 207.3l.6 2z"/>
<path d="M92.4 208.3l-.2 1z"/>
<path d="M183.6 53h2.5z"/>
<path d="M191 43.2v2.4z"/>
<path d="M186.1 53h1.4z"/>
<path d="M189.1 48.7h1.9z"/>
<path d="M191 50.5v1.9z"/>
<path d="M189 52.4h2z"/>
<path d="M191 48.7h2.5z"/>
<path d="M193.5 48.7v1.1z"/>
<path d="M193.5 49.8v2.6z"/>
<path d="M191 52.4h2.5z"/>
<path d="M193.5 49.8l-.6 1.4z"/>
<path d="M192.9 51.2h1.2z"/>
<path d="M193.5 49.8l.6 1.4z"/>
<path d="M192.9 49.8h.6z"/>
<path d="M193.5 49.8h.6z"/>
<path d="M194.1 49.8l.2-.2z"/>
<path d="M192.9 49.8l-.3 .3z"/>
<path d="M189 50.5l1.3 .5z"/>
<path d="M190.3 50.1v.9z"/>
<path d="M189 50.5l1.3-.4z"/>
<path d="M190.2 50.5h.8z"/>
<path d="M191 55.5v2.4z"/>
<path d="M191 52.4v3.1z"/>
<path d="M191 45.6v3.1z"/>
<path d="M200.9 43.2v2.4z"/>
<path d="M203.3 43.2v2.4z"/>
<path d="M193.5 43.2v2.4z"/>
<path d="M195.9 43.2v2.4z"/>
<path d="M198.4 43.2v2.4z"/>
<path d="M203.3 55.5v2.4z"/>
<path d="M193.5 55.5v2.4z"/>
<path d="M195.9 55.5v2.4z"/>
<path d="M198.4 55.5v2.4z"/>
<path d="M200.9 55.5v2.4z"/>
<path d="M183.6 72.7h2.5z"/>
<path d="M191 62.9v2.4z"/>
<path d="M186.1 72.7h1.4z"/>
<path d="M189.1 68.4h1.9z"/>
<path d="M191 70.3v1.8z"/>
<path d="M189 72.1h2z"/>
<path d="M191 68.4h2.5z"/>
<path d="M193.5 68.4v1.1z"/>
<path d="M193.5 69.5v2.6z"/>
<path d="M191 72.1h2.5z"/>
<path d="M193.5 69.5l-.6 1.4z"/>
<path d="M192.9 70.9h1.2z"/>
<path d="M193.5 69.5l.6 1.4z"/>
<path d="M192.9 69.5h.6z"/>
<path d="M193.5 69.5h.6z"/>
<path d="M194.1 69.5l.2-.2z"/>
<path d="M192.9 69.5l-.3 .3z"/>
<path d="M189 70.3l1.3 .5z"/>
<path d="M190.3 69.8v1z"/>
<path d="M189 70.3l1.3-.5z"/>
<path d="M190.2 70.3h.8z"/>
<path d="M191 75.2v2.5z"/>
<path d="M191 72.1v3.1z"/>
<path d="M191 65.3v3.1z"/>
<path d="M200.9 62.9v2.4z"/>
<path d="M203.3 62.9v2.4z"/>
<path d="M193.5 62.9v2.4z"/>
<path d="M195.9 62.9v2.4z"/>
<path d="M198.4 62.9v2.4z"/>
<path d="M203.3 75.2v2.5z"/>
<path d="M193.5 75.2v2.5z"/>
<path d="M195.9 75.2v2.5z"/>
<path d="M198.4 75.2v2.5z"/>
<path d="M200.9 75.2v2.5z"/>
<path d="M375.9 65.3v2.5z"/>
<path d="M210.7 53h2.5z"/>
<path d="M218.1 43.2v2.4z"/>
<path d="M213.2 53h1.4z"/>
<path d="M216.2 48.7h1.9z"/>
<path d="M218.1 50.5v1.9z"/>
<path d="M216.2 52.4h1.9z"/>
<path d="M218.1 48.7h2.5z"/>
<path d="M220.6 48.7v1.1z"/>
<path d="M220.6 49.8v2.6z"/>
<path d="M218.1 52.4h2.5z"/>
<path d="M220.6 49.8l-.6 1.4z"/>
<path d="M220 51.2h1.2z"/>
<path d="M220.6 49.8l.6 1.4z"/>
<path d="M220 49.8h.6z"/>
<path d="M220.6 49.8h.6z"/>
<path d="M221.4 49.6l-.2 .2z"/>
<path d="M220 49.8l-.3 .3z"/>
<path d="M216.2 50.5l1.2 .5z"/>
<path d="M217.4 50.1v.9z"/>
<path d="M216.2 50.5l1.2-.4z"/>
<path d="M217.3 50.5h.8z"/>
<path d="M218.1 55.5v2.4z"/>
<path d="M218.1 52.4v3.1z"/>
<path d="M218.1 45.6v3.1z"/>
<path d="M228 43.2v2.4z"/>
<path d="M230.4 43.2v2.4z"/>
<path d="M220.6 43.2v2.4z"/>
<path d="M223.1 43.2v2.4z"/>
<path d="M225.5 43.2v2.4z"/>
<path d="M230.4 55.5v2.4z"/>
<path d="M220.6 55.5v2.4z"/>
<path d="M223.1 55.5v2.4z"/>
<path d="M225.5 55.5v2.4z"/>
<path d="M228 55.5v2.4z"/>
<path d="M237.8 53h2.5z"/>
<path d="M245.2 43.2v2.4z"/>
<path d="M240.3 53h1.4z"/>
<path d="M243.3 48.7h1.9z"/>
<path d="M245.2 50.5v1.9z"/>
<path d="M243.3 52.4h1.9z"/>
<path d="M245.2 48.7h2.5z"/>
<path d="M247.7 48.7v1.1z"/>
<path d="M247.7 49.8v2.6z"/>
<path d="M245.2 52.4h2.5z"/>
<path d="M247.7 49.8l-.6 1.4z"/>
<path d="M247.1 51.2h1.2z"/>
<path d="M247.7 49.8l.6 1.4z"/>
<path d="M247.1 49.8h.6z"/>
<path d="M247.7 49.8h.6z"/>
<path d="M248.6 49.6l-.3 .2z"/>
<path d="M247.1 49.8l-.3 .3z"/>
<path d="M243.3 50.5l1.2 .5z"/>
<path d="M244.5 50.1v.9z"/>
<path d="M243.3 50.5l1.2-.4z"/>
<path d="M244.4 50.5h.8z"/>
<path d="M245.2 55.5v2.4z"/>
<path d="M245.2 52.4v3.1z"/>
<path d="M245.2 45.6v3.1z"/>
<path d="M255.1 43.2v2.4z"/>
<path d="M257.6 43.2v2.4z"/>
<path d="M247.7 43.2v2.4z"/>
<path d="M250.2 43.2v2.4z"/>
<path d="M252.6 43.2v2.4z"/>
<path d="M257.6 55.5v2.4z"/>
<path d="M247.7 55.5v2.4z"/>
<path d="M250.2 55.5v2.4z"/>
<path d="M252.6 55.5v2.4z"/>
<path d="M255.1 55.5v2.4z"/>
<path d="M264.9 53h2.5z"/>
<path d="M272.3 43.2v2.4z"/>
<path d="M267.4 53h1.4z"/>
<path d="M270.4 48.7h1.9z"/>
<path d="M272.3 50.5v1.9z"/>
<path d="M270.4 52.4h1.9z"/>
<path d="M272.3 48.7h2.5z"/>
<path d="M274.8 48.7v1.1z"/>
<path d="M274.8 49.8v2.6z"/>
<path d="M272.3 52.4h2.5z"/>
<path d="M274.8 49.8l-.6 1.4z"/>
<path d="M274.2 51.2h1.2z"/>
<path d="M274.8 49.8l.6 1.4z"/>
<path d="M274.2 49.8h.6z"/>
<path d="M274.8 49.8h.6z"/>
<path d="M275.4 49.8l.3-.2z"/>
<path d="M274.2 49.8l-.3 .3z"/>
<path d="M270.4 50.5l1.2 .5z"/>
<path d="M271.6 50.1v.9z"/>
<path d="M270.4 50.5l1.2-.4z"/>
<path d="M271.5 50.5h.8z"/>
<path d="M272.3 55.5v2.4z"/>
<path d="M272.3 52.4v3.1z"/>
<path d="M272.3 45.6v3.1z"/>
<path d="M282.2 43.2v2.4z"/>
<path d="M284.7 43.2v2.4z"/>
<path d="M274.8 43.2v2.4z"/>
<path d="M277.3 43.2v2.4z"/>
<path d="M279.7 43.2v2.4z"/>
<path d="M284.7 55.5v2.4z"/>
<path d="M274.8 55.5v2.4z"/>
<path d="M277.3 55.5v2.4z"/>
<path d="M279.7 55.5v2.4z"/>
<path d="M282.2 55.5v2.4z"/>
<path d="M210.7 72.7h2.5z"/>
<path d="M218.1 62.9v2.4z"/>
<path d="M213.2 72.7h1.4z"/>
<path d="M216.2 68.4h1.9z"/>
<path d="M218.1 70.3v1.8z"/>
<path d="M216.2 72.1h1.9z"/>
<path d="M218.1 68.4h2.5z"/>
<path d="M220.6 68.4v1.1z"/>
<path d="M220.6 69.5v2.6z"/>
<path d="M218.1 72.1h2.5z"/>
<path d="M220.6 69.5l-.6 1.4z"/>
<path d="M220 70.9h1.2z"/>
<path d="M220.6 69.5l.6 1.4z"/>
<path d="M220 69.5h.6z"/>
<path d="M220.6 69.5h.6z"/>
<path d="M221.2 69.5l.2-.2z"/>
<path d="M220 69.5l-.3 .3z"/>
<path d="M216.2 70.3l1.2 .5z"/>
<path d="M217.4 69.8v1z"/>
<path d="M216.2 70.3l1.2-.5z"/>
<path d="M217.3 70.3h.8z"/>
<path d="M218.1 75.2v2.5z"/>
<path d="M218.1 72.1v3.1z"/>
<path d="M218.1 65.3v3.1z"/>
<path d="M228 62.9v2.4z"/>
<path d="M230.4 62.9v2.4z"/>
<path d="M220.6 62.9v2.4z"/>
<path d="M223.1 62.9v2.4z"/>
<path d="M225.5 62.9v2.4z"/>
<path d="M230.4 75.2v2.5z"/>
<path d="M220.6 75.2v2.5z"/>
<path d="M223.1 75.2v2.5z"/>
<path d="M225.5 75.2v2.5z"/>
<path d="M228 75.2v2.5z"/>
<path d="M237.8 72.7h2.5z"/>
<path d="M245.2 62.9v2.4z"/>
<path d="M240.3 72.7h1.4z"/>
<path d="M243.3 68.4h1.9z"/>
<path d="M245.2 70.3v1.8z"/>
<path d="M243.3 72.1h1.9z"/>
<path d="M245.2 68.4h2.5z"/>
<path d="M247.7 68.4v1.1z"/>
<path d="M247.7 69.5v2.6z"/>
<path d="M245.2 72.1h2.5z"/>
<path d="M247.7 69.5l-.6 1.4z"/>
<path d="M247.1 70.9h1.2z"/>
<path d="M247.7 69.5l.6 1.4z"/>
<path d="M247.1 69.5h.6z"/>
<path d="M247.7 69.5h.6z"/>
<path d="M248.3 69.5l.3-.2z"/>
<path d="M247.1 69.5l-.3 .3z"/>
<path d="M243.3 70.3l1.2 .5z"/>
<path d="M244.5 69.8v1z"/>
<path d="M243.3 70.3l1.2-.5z"/>
<path d="M244.4 70.3h.8z"/>
<path d="M245.2 75.2v2.5z"/>
<path d="M245.2 72.1v3.1z"/>
<path d="M245.2 65.3v3.1z"/>
<path d="M255.1 62.9v2.4z"/>
<path d="M257.6 62.9v2.4z"/>
<path d="M247.7 62.9v2.4z"/>
<path d="M250.2 62.9v2.4z"/>
<path d="M252.6 62.9v2.4z"/>
<path d="M257.6 75.2v2.5z"/>
<path d="M247.7 75.2v2.5z"/>
<path d="M250.2 75.2v2.5z"/>
<path d="M252.6 75.2v2.5z"/>
<path d="M255.1 75.2v2.5z"/>
<path d="M264.9 72.7h2.5z"/>
<path d="M272.3 62.9v2.4z"/>
<path d="M267.4 72.7h1.4z"/>
<path d="M270.4 68.4h1.9z"/>
<path d="M272.3 70.3v1.8z"/>
<path d="M270.4 72.1h1.9z"/>
<path d="M272.3 68.4h2.5z"/>
<path d="M274.8 68.4v1.1z"/>
<path d="M274.8 69.5v2.6z"/>
<path d="M272.3 72.1h2.5z"/>
<path d="M274.8 69.5l-.6 1.4z"/>
<path d="M274.2 70.9h1.2z"/>
<path d="M274.8 69.5l.6 1.4z"/>
<path d="M274.2 69.5h.6z"/>
<path d="M274.8 69.5h.6z"/>
<path d="M275.4 69.5l.3-.2z"/>
<path d="M273.9 69.8l.3-.3z"/>
<path d="M270.4 70.3l1.2 .5z"/>
<path d="M271.6 69.8v1z"/>
<path d="M270.4 70.3l1.2-.5z"/>
<path d="M271.5 70.3h.8z"/>
<path d="M272.3 75.2v2.5z"/>
<path d="M272.3 72.1v3.1z"/>
<path d="M272.3 65.3v3.1z"/>
<path d="M282.2 62.9v2.4z"/>
<path d="M284.7 62.9v2.4z"/>
<path d="M274.8 62.9v2.4z"/>
<path d="M277.3 62.9v2.4z"/>
<path d="M279.7 62.9v2.4z"/>
<path d="M284.7 75.2v2.5z"/>
<path d="M274.8 75.2v2.5z"/>
<path d="M277.3 75.2v2.5z"/>
<path d="M279.7 75.2v2.5z"/>
<path d="M282.2 75.2v2.5z"/>
<path d="M284.7 161.4v2.5z"/>
<path d="M183.6 126.9h2.5z"/>
<path d="M191 117.1v2.4z"/>
<path d="M186.1 126.9h1.4z"/>
<path d="M189.1 122.6h1.9z"/>
<path d="M191 124.5v1.8z"/>
<path d="M189 126.3h2z"/>
<path d="M191 122.6h2.5z"/>
<path d="M193.5 122.6v1.1z"/>
<path d="M193.5 123.7v2.6z"/>
<path d="M191 126.3h2.5z"/>
<path d="M193.5 123.7l-.6 1.4z"/>
<path d="M192.9 125.1h1.2z"/>
<path d="M193.5 123.7l.6 1.4z"/>
<path d="M192.9 123.7h.6z"/>
<path d="M193.5 123.7h.6z"/>
<path d="M194.1 123.7l.2-.2z"/>
<path d="M192.6 124l.3-.3z"/>
<path d="M189 124.5l1.3 .5z"/>
<path d="M190.3 124v1z"/>
<path d="M189 124.5l1.3-.5z"/>
<path d="M190.2 124.5h.8z"/>
<path d="M191 129.4v2.5z"/>
<path d="M191 126.3v3.1z"/>
<path d="M191 119.5v3.1z"/>
<path d="M200.9 117.1v2.4z"/>
<path d="M203.3 117.1v2.4z"/>
<path d="M193.5 117.1v2.4z"/>
<path d="M195.9 117.1v2.4z"/>
<path d="M198.4 117.1v2.4z"/>
<path d="M203.3 129.4v2.5z"/>
<path d="M193.5 129.4v2.5z"/>
<path d="M195.9 129.4v2.5z"/>
<path d="M198.4 129.4v2.5z"/>
<path d="M200.9 129.4v2.5z"/>
<path d="M183.6 146.7h2.5z"/>
<path d="M191 136.8v2.5z"/>
<path d="M186.1 146.7h1.4z"/>
<path d="M189.1 142.3h1.9z"/>
<path d="M191 144.2v1.8z"/>
<path d="M189 146h2z"/>
<path d="M191 142.3h2.5z"/>
<path d="M193.5 142.3v1.1z"/>
<path d="M193.5 143.4v2.6z"/>
<path d="M191 146h2.5z"/>
<path d="M193.5 143.4l-.6 1.4z"/>
<path d="M192.9 144.8h1.2z"/>
<path d="M193.5 143.4l.6 1.4z"/>
<path d="M192.9 143.4h.6z"/>
<path d="M193.5 143.4h.6z"/>
<path d="M194.1 143.4l.2-.2z"/>
<path d="M192.9 143.4l-.3 .3z"/>
<path d="M189 144.2l1.3 .5z"/>
<path d="M190.3 143.7v1z"/>
<path d="M189 144.2l1.3-.5z"/>
<path d="M190.2 144.2h.8z"/>
<path d="M191 149.1v2.5z"/>
<path d="M191 146v3.1z"/>
<path d="M191 139.3v3z"/>
<path d="M200.9 136.8v2.5z"/>
<path d="M203.3 136.8v2.5z"/>
<path d="M193.5 136.8v2.5z"/>
<path d="M195.9 136.8v2.5z"/>
<path d="M198.4 136.8v2.5z"/>
<path d="M203.3 149.1v2.5z"/>
<path d="M193.5 149.1v2.5z"/>
<path d="M195.9 149.1v2.5z"/>
<path d="M198.4 149.1v2.5z"/>
<path d="M200.9 149.1v2.5z"/>
<path d="M210.7 126.9h2.5z"/>
<path d="M218.1 117.1v2.4z"/>
<path d="M213.2 126.9h1.4z"/>
<path d="M216.2 122.6h1.9z"/>
<path d="M218.1 124.5v1.8z"/>
<path d="M216.2 126.3h1.9z"/>
<path d="M218.1 122.6h2.5z"/>
<path d="M220.6 122.6v1.1z"/>
<path d="M220.6 123.7v2.6z"/>
<path d="M218.1 126.3h2.5z"/>
<path d="M220.6 123.7l-.6 1.4z"/>
<path d="M220 125.1h1.2z"/>
<path d="M220.6 123.7l.6 1.4z"/>
<path d="M220 123.7h.6z"/>
<path d="M220.6 123.7h.6z"/>
<path d="M221.4 123.5l-.2 .2z"/>
<path d="M219.7 124l.3-.3z"/>
<path d="M216.2 124.5l1.2 .5z"/>
<path d="M217.4 124v1z"/>
<path d="M216.2 124.5l1.2-.5z"/>
<path d="M217.3 124.5h.8z"/>
<path d="M218.1 129.4v2.5z"/>
<path d="M218.1 126.3v3.1z"/>
<path d="M218.1 119.5v3.1z"/>
<path d="M228 117.1v2.4z"/>
<path d="M230.4 117.1v2.4z"/>
<path d="M220.6 117.1v2.4z"/>
<path d="M223.1 117.1v2.4z"/>
<path d="M225.5 117.1v2.4z"/>
<path d="M230.4 129.4v2.5z"/>
<path d="M220.6 129.4v2.5z"/>
<path d="M223.1 129.4v2.5z"/>
<path d="M225.5 129.4v2.5z"/>
<path d="M228 129.4v2.5z"/>
<path d="M237.8 126.9h2.5z"/>
<path d="M245.2 117.1v2.4z"/>
<path d="M240.3 126.9h1.4z"/>
<path d="M243.3 122.6h1.9z"/>
<path d="M245.2 124.5v1.8z"/>
<path d="M243.3 126.3h1.9z"/>
<path d="M245.2 122.6h2.5z"/>
<path d="M247.7 122.6v1.1z"/>
<path d="M247.7 123.7v2.6z"/>
<path d="M245.2 126.3h2.5z"/>
<path d="M247.7 123.7l-.6 1.4z"/>
<path d="M247.1 125.1h1.2z"/>
<path d="M247.7 123.7l.6 1.4z"/>
<path d="M247.1 123.7h.6z"/>
<path d="M247.7 123.7h.6z"/>
<path d="M248.6 123.5l-.3 .2z"/>
<path d="M247.1 123.7l-.3 .3z"/>
<path d="M243.3 124.5l1.2 .5z"/>
<path d="M244.5 124v1z"/>
<path d="M243.3 124.5l1.2-.5z"/>
<path d="M244.4 124.5h.8z"/>
<path d="M245.2 129.4v2.5z"/>
<path d="M245.2 126.3v3.1z"/>
<path d="M245.2 119.5v3.1z"/>
<path d="M255.1 117.1v2.4z"/>
<path d="M257.6 117.1v2.4z"/>
<path d="M247.7 117.1v2.4z"/>
<path d="M250.2 117.1v2.4z"/>
<path d="M252.6 117.1v2.4z"/>
<path d="M257.6 129.4v2.5z"/>
<path d="M247.7 129.4v2.5z"/>
<path d="M250.2 129.4v2.5z"/>
<path d="M252.6 129.4v2.5z"/>
<path d="M255.1 129.4v2.5z"/>
<path d="M264.9 126.9h2.5z"/>
<path d="M272.3 117.1v2.4z"/>
<path d="M267.4 126.9h1.4z"/>
<path d="M270.4 122.6h1.9z"/>
<path d="M272.3 124.5v1.8z"/>
<path d="M270.4 126.3h1.9z"/>
<path d="M272.3 122.6h2.5z"/>
<path d="M274.8 122.6v1.1z"/>
<path d="M274.8 123.7v2.6z"/>
<path d="M272.3 126.3h2.5z"/>
<path d="M274.8 123.7l-.6 1.4z"/>
<path d="M274.2 125.1h1.2z"/>
<path d="M274.8 123.7l.6 1.4z"/>
<path d="M274.2 123.7h.6z"/>
<path d="M274.8 123.7h.6z"/>
<path d="M275.4 123.7l.3-.2z"/>
<path d="M273.9 124l.3-.3z"/>
<path d="M270.4 124.5l1.2 .5z"/>
<path d="M271.6 124v1z"/>
<path d="M270.4 124.5l1.2-.5z"/>
<path d="M271.5 124.5h.8z"/>
<path d="M272.3 129.4v2.5z"/>
<path d="M272.3 126.3v3.1z"/>
<path d="M272.3 119.5v3.1z"/>
<path d="M282.2 117.1v2.4z"/>
<path d="M284.7 117.1v2.4z"/>
<path d="M274.8 117.1v2.4z"/>
<path d="M277.3 117.1v2.4z"/>
<path d="M279.7 117.1v2.4z"/>
<path d="M284.7 129.4v2.5z"/>
<path d="M274.8 129.4v2.5z"/>
<path d="M277.3 129.4v2.5z"/>
<path d="M279.7 129.4v2.5z"/>
<path d="M282.2 129.4v2.5z"/>
<path d="M210.7 146.7h2.5z"/>
<path d="M218.1 136.8v2.5z"/>
<path d="M213.2 146.7h1.4z"/>
<path d="M216.2 142.3h1.9z"/>
<path d="M218.1 144.2v1.8z"/>
<path d="M216.2 146h1.9z"/>
<path d="M218.1 142.3h2.5z"/>
<path d="M220.6 142.3v1.1z"/>
<path d="M220.6 143.4v2.6z"/>
<path d="M218.1 146h2.5z"/>
<path d="M220.6 143.4l-.6 1.4z"/>
<path d="M220 144.8h1.2z"/>
<path d="M220.6 143.4l.6 1.4z"/>
<path d="M220 143.4h.6z"/>
<path d="M220.6 143.4h.6z"/>
<path d="M221.2 143.4l.2-.2z"/>
<path d="M220 143.4l-.3 .3z"/>
<path d="M216.2 144.2l1.2 .5z"/>
<path d="M217.4 143.7v1z"/>
<path d="M216.2 144.2l1.2-.5z"/>
<path d="M217.3 144.2h.8z"/>
<path d="M218.1 149.1v2.5z"/>
<path d="M218.1 146v3.1z"/>
<path d="M218.1 139.3v3z"/>
<path d="M228 136.8v2.5z"/>
<path d="M230.4 136.8v2.5z"/>
<path d="M220.6 136.8v2.5z"/>
<path d="M223.1 136.8v2.5z"/>
<path d="M225.5 136.8v2.5z"/>
<path d="M230.4 149.1v2.5z"/>
<path d="M220.6 149.1v2.5z"/>
<path d="M223.1 149.1v2.5z"/>
<path d="M225.5 149.1v2.5z"/>
<path d="M228 149.1v2.5z"/>
<path d="M237.8 146.7h2.5z"/>
<path d="M245.2 136.8v2.5z"/>
<path d="M240.3 146.7h1.4z"/>
<path d="M243.3 142.3h1.9z"/>
<path d="M245.2 144.2v1.8z"/>
<path d="M243.3 146h1.9z"/>
<path d="M245.2 142.3h2.5z"/>
<path d="M247.7 142.3v1.1z"/>
<path d="M247.7 143.4v2.6z"/>
<path d="M245.2 146h2.5z"/>
<path d="M247.7 143.4l-.6 1.4z"/>
<path d="M247.1 144.8h1.2z"/>
<path d="M247.7 143.4l.6 1.4z"/>
<path d="M247.1 143.4h.6z"/>
<path d="M247.7 143.4h.6z"/>
<path d="M248.3 143.4l.3-.2z"/>
<path d="M247.1 143.4l-.3 .3z"/>
<path d="M243.3 144.2l1.2 .5z"/>
<path d="M244.5 143.7v1z"/>
<path d="M243.3 144.2l1.2-.5z"/>
<path d="M244.4 144.2h.8z"/>
<path d="M245.2 149.1v2.5z"/>
<path d="M245.2 146v3.1z"/>
<path d="M245.2 139.3v3z"/>
<path d="M255.1 136.8v2.5z"/>
<path d="M257.6 136.8v2.5z"/>
<path d="M247.7 136.8v2.5z"/>
<path d="M250.2 136.8v2.5z"/>
<path d="M252.6 136.8v2.5z"/>
<path d="M257.6 149.1v2.5z"/>
<path d="M247.7 149.1v2.5z"/>
<path d="M250.2 149.1v2.5z"/>
<path d="M252.6 149.1v2.5z"/>
<path d="M255.1 149.1v2.5z"/>
<path d="M264.9 146.7h2.5z"/>
<path d="M272.3 136.8v2.5z"/>
<path d="M267.4 146.7h1.4z"/>
<path d="M270.4 142.3h1.9z"/>
<path d="M272.3 144.2v1.8z"/>
<path d="M270.4 146h1.9z"/>
<path d="M272.3 142.3h2.5z"/>
<path d="M274.8 142.3v1.1z"/>
<path d="M274.8 143.4v2.6z"/>
<path d="M272.3 146h2.5z"/>
<path d="M274.8 143.4l-.6 1.4z"/>
<path d="M274.2 144.8h1.2z"/>
<path d="M274.8 143.4l.6 1.4z"/>
<path d="M274.2 143.4h.6z"/>
<path d="M274.8 143.4h.6z"/>
<path d="M275.4 143.4l.3-.2z"/>
<path d="M273.9 143.7l.3-.3z"/>
<path d="M270.4 144.2l1.2 .5z"/>
<path d="M271.6 143.7v1z"/>
<path d="M270.4 144.2l1.2-.5z"/>
<path d="M271.5 144.2h.8z"/>
<path d="M272.3 149.1v2.5z"/>
<path d="M272.3 146v3.1z"/>
<path d="M272.3 139.3v3z"/>
<path d="M282.2 136.8v2.5z"/>
<path d="M284.7 136.8v2.5z"/>
<path d="M274.8 136.8v2.5z"/>
<path d="M277.3 136.8v2.5z"/>
<path d="M279.7 136.8v2.5z"/>
<path d="M284.7 149.1v2.5z"/>
<path d="M274.8 149.1v2.5z"/>
<path d="M277.3 149.1v2.5z"/>
<path d="M279.7 149.1v2.5z"/>
<path d="M282.2 149.1v2.5z"/>
<path d="M284.7 237.8v2.5z"/>
<path d="M183.6 200.9h2.5z"/>
<path d="M191 191v2.5z"/>
<path d="M186.1 200.9h1.4z"/>
<path d="M189.1 196.6h1.9z"/>
<path d="M191 198.4v1.9z"/>
<path d="M189 200.3h2z"/>
<path d="M191 196.6h2.5z"/>
<path d="M193.5 196.6v1.1z"/>
<path d="M193.5 197.7v2.6z"/>
<path d="M191 200.3h2.5z"/>
<path d="M193.5 197.7l-.6 1.3z"/>
<path d="M192.9 199h1.2z"/>
<path d="M193.5 197.7l.6 1.3z"/>
<path d="M192.9 197.7h.6z"/>
<path d="M193.5 197.7h.6z"/>
<path d="M194.1 197.7l.2-.3z"/>
<path d="M192.6 197.9l.3-.2z"/>
<path d="M189 198.4l1.3 .5z"/>
<path d="M190.3 197.9v1z"/>
<path d="M189 198.4l1.3-.5z"/>
<path d="M190.2 198.4h.8z"/>
<path d="M191 203.3v2.5z"/>
<path d="M191 200.3v3z"/>
<path d="M191 193.5v3.1z"/>
<path d="M200.9 191v2.5z"/>
<path d="M203.3 191v2.5z"/>
<path d="M193.5 191v2.5z"/>
<path d="M195.9 191v2.5z"/>
<path d="M198.4 191v2.5z"/>
<path d="M203.3 203.3v2.5z"/>
<path d="M193.5 203.3v2.5z"/>
<path d="M195.9 203.3v2.5z"/>
<path d="M198.4 203.3v2.5z"/>
<path d="M200.9 203.3v2.5z"/>
<path d="M183.6 220.6h2.5z"/>
<path d="M191 210.7v2.5z"/>
<path d="M186.1 220.6h1.4z"/>
<path d="M189.1 216.3h1.9z"/>
<path d="M191 218.1v1.9z"/>
<path d="M189 220h2z"/>
<path d="M191 216.3h2.5z"/>
<path d="M193.5 216.3v1.1z"/>
<path d="M193.5 217.4v2.6z"/>
<path d="M191 220h2.5z"/>
<path d="M193.5 217.4l-.6 1.3z"/>
<path d="M192.9 218.7h1.2z"/>
<path d="M193.5 217.4l.6 1.3z"/>
<path d="M192.9 217.4h.6z"/>
<path d="M193.5 217.4h.6z"/>
<path d="M194.1 217.4l.2-.3z"/>
<path d="M192.9 217.4l-.3 .2z"/>
<path d="M189 218.1l1.3 .5z"/>
<path d="M190.3 217.6v1z"/>
<path d="M189 218.1l1.3-.5z"/>
<path d="M190.2 218.1h.8z"/>
<path d="M191 223.1v2.4z"/>
<path d="M191 220v3.1z"/>
<path d="M191 213.2v3.1z"/>
<path d="M200.9 210.7v2.5z"/>
<path d="M203.3 210.7v2.5z"/>
<path d="M193.5 210.7v2.5z"/>
<path d="M195.9 210.7v2.5z"/>
<path d="M198.4 210.7v2.5z"/>
<path d="M203.3 223.1v2.4z"/>
<path d="M193.5 223.1v2.4z"/>
<path d="M195.9 223.1v2.4z"/>
<path d="M198.4 223.1v2.4z"/>
<path d="M200.9 223.1v2.4z"/>
<path d="M210.7 200.9h2.5z"/>
<path d="M218.1 191v2.5z"/>
<path d="M213.2 200.9h1.4z"/>
<path d="M216.2 196.6h1.9z"/>
<path d="M218.1 198.4v1.9z"/>
<path d="M216.2 200.3h1.9z"/>
<path d="M218.1 196.6h2.5z"/>
<path d="M220.6 196.6v1.1z"/>
<path d="M220.6 197.7v2.6z"/>
<path d="M218.1 200.3h2.5z"/>
<path d="M220.6 197.7l-.6 1.3z"/>
<path d="M220 199h1.2z"/>
<path d="M220.6 197.7l.6 1.3z"/>
<path d="M220 197.7h.6z"/>
<path d="M220.6 197.7h.6z"/>
<path d="M221.4 197.4l-.2 .3z"/>
<path d="M219.7 197.9l.3-.2z"/>
<path d="M216.2 198.4l1.2 .5z"/>
<path d="M217.4 197.9v1z"/>
<path d="M216.2 198.4l1.2-.5z"/>
<path d="M217.3 198.4h.8z"/>
<path d="M218.1 203.3v2.5z"/>
<path d="M218.1 200.3v3z"/>
<path d="M218.1 193.5v3.1z"/>
<path d="M228 191v2.5z"/>
<path d="M230.4 191v2.5z"/>
<path d="M220.6 191v2.5z"/>
<path d="M223.1 191v2.5z"/>
<path d="M225.5 191v2.5z"/>
<path d="M230.4 203.3v2.5z"/>
<path d="M220.6 203.3v2.5z"/>
<path d="M223.1 203.3v2.5z"/>
<path d="M225.5 203.3v2.5z"/>
<path d="M228 203.3v2.5z"/>
<path d="M237.8 200.9h2.5z"/>
<path d="M245.2 191v2.5z"/>
<path d="M240.3 200.9h1.4z"/>
<path d="M243.3 196.6h1.9z"/>
<path d="M245.2 198.4v1.9z"/>
<path d="M243.3 200.3h1.9z"/>
<path d="M245.2 196.6h2.5z"/>
<path d="M247.7 196.6v1.1z"/>
<path d="M247.7 197.7v2.6z"/>
<path d="M245.2 200.3h2.5z"/>
<path d="M247.7 197.7l-.6 1.3z"/>
<path d="M247.1 199h1.2z"/>
<path d="M247.7 197.7l.6 1.3z"/>
<path d="M247.1 197.7h.6z"/>
<path d="M247.7 197.7h.6z"/>
<path d="M248.6 197.4l-.3 .3z"/>
<path d="M247.1 197.7l-.3 .2z"/>
<path d="M243.3 198.4l1.2 .5z"/>
<path d="M244.5 197.9v1z"/>
<path d="M243.3 198.4l1.2-.5z"/>
<path d="M244.4 198.4h.8z"/>
<path d="M245.2 203.3v2.5z"/>
<path d="M245.2 200.3v3z"/>
<path d="M245.2 193.5v3.1z"/>
<path d="M255.1 191v2.5z"/>
<path d="M257.6 191v2.5z"/>
<path d="M247.7 191v2.5z"/>
<path d="M250.2 191v2.5z"/>
<path d="M252.6 191v2.5z"/>
<path d="M257.6 203.3v2.5z"/>
<path d="M247.7 203.3v2.5z"/>
<path d="M250.2 203.3v2.5z"/>
<path d="M252.6 203.3v2.5z"/>
<path d="M255.1 203.3v2.5z"/>
<path d="M264.9 200.9h2.5z"/>
<path d="M272.3 191v2.5z"/>
<path d="M267.4 200.9h1.4z"/>
<path d="M270.4 196.6h1.9z"/>
<path d="M272.3 198.4v1.9z"/>
<path d="M270.4 200.3h1.9z"/>
<path d="M272.3 196.6h2.5z"/>
<path d="M274.8 196.6v1.1z"/>
<path d="M274.8 197.7v2.6z"/>
<path d="M272.3 200.3h2.5z"/>
<path d="M274.8 197.7l-.6 1.3z"/>
<path d="M274.2 199h1.2z"/>
<path d="M274.8 197.7l.6 1.3z"/>
<path d="M274.2 197.7h.6z"/>
<path d="M274.8 197.7h.6z"/>
<path d="M275.4 197.7l.3-.3z"/>
<path d="M273.9 197.9l.3-.2z"/>
<path d="M270.4 198.4l1.2 .5z"/>
<path d="M271.6 197.9v1z"/>
<path d="M270.4 198.4l1.2-.5z"/>
<path d="M271.5 198.4h.8z"/>
<path d="M272.3 203.3v2.5z"/>
<path d="M272.3 200.3v3z"/>
<path d="M272.3 193.5v3.1z"/>
<path d="M282.2 191v2.5z"/>
<path d="M284.7 191v2.5z"/>
<path d="M274.8 191v2.5z"/>
<path d="M277.3 191v2.5z"/>
<path d="M279.7 191v2.5z"/>
<path d="M284.7 203.3v2.5z"/>
<path d="M274.8 203.3v2.5z"/>
<path d="M277.3 203.3v2.5z"/>
<path d="M279.7 203.3v2.5z"/>
<path d="M282.2 203.3v2.5z"/>
<path d="M210.7 220.6h2.5z"/>
<path d="M218.1 210.7v2.5z"/>
<path d="M213.2 220.6h1.4z"/>
<path d="M216.2 216.3h1.9z"/>
<path d="M218.1 218.1v1.9z"/>
<path d="M216.2 220h1.9z"/>
<path d="M218.1 216.3h2.5z"/>
<path d="M220.6 216.3v1.1z"/>
<path d="M220.6 217.4v2.6z"/>
<path d="M218.1 220h2.5z"/>
<path d="M220.6 217.4l-.6 1.3z"/>
<path d="M220 218.7h1.2z"/>
<path d="M220.6 217.4l.6 1.3z"/>
<path d="M220 217.4h.6z"/>
<path d="M220.6 217.4h.6z"/>
<path d="M221.4 217.1l-.2 .3z"/>
<path d="M220 217.4l-.3 .2z"/>
<path d="M216.2 218.1l1.2 .5z"/>
<path d="M217.4 217.6v1z"/>
<path d="M216.2 218.1l1.2-.5z"/>
<path d="M217.3 218.1h.8z"/>
<path d="M218.1 223.1v2.4z"/>
<path d="M218.1 220v3.1z"/>
<path d="M218.1 213.2v3.1z"/>
<path d="M228 210.7v2.5z"/>
<path d="M230.4 210.7v2.5z"/>
<path d="M220.6 210.7v2.5z"/>
<path d="M223.1 210.7v2.5z"/>
<path d="M225.5 210.7v2.5z"/>
<path d="M230.4 223.1v2.4z"/>
<path d="M220.6 223.1v2.4z"/>
<path d="M223.1 223.1v2.4z"/>
<path d="M225.5 223.1v2.4z"/>
<path d="M228 223.1v2.4z"/>
<path d="M237.8 220.6h2.5z"/>
<path d="M245.2 210.7v2.5z"/>
<path d="M240.3 220.6h1.4z"/>
<path d="M243.3 216.3h1.9z"/>
<path d="M245.2 218.1v1.9z"/>
<path d="M243.3 220h1.9z"/>
<path d="M245.2 216.3h2.5z"/>
<path d="M247.7 216.3v1.1z"/>
<path d="M247.7 217.4v2.6z"/>
<path d="M245.2 220h2.5z"/>
<path d="M247.7 217.4l-.6 1.3z"/>
<path d="M247.1 218.7h1.2z"/>
<path d="M247.7 217.4l.6 1.3z"/>
<path d="M247.1 217.4h.6z"/>
<path d="M247.7 217.4h.6z"/>
<path d="M248.6 217.1l-.3 .3z"/>
<path d="M247.1 217.4l-.3 .2z"/>
<path d="M243.3 218.1l1.2 .5z"/>
<path d="M244.5 217.6v1z"/>
<path d="M243.3 218.1l1.2-.5z"/>
<path d="M244.4 218.1h.8z"/>
<path d="M245.2 223.1v2.4z"/>
<path d="M245.2 220v3.1z"/>
<path d="M245.2 213.2v3.1z"/>
<path d="M255.1 210.7v2.5z"/>
<path d="M257.6 210.7v2.5z"/>
<path d="M247.7 210.7v2.5z"/>
<path d="M250.2 210.7v2.5z"/>
<path d="M252.6 210.7v2.5z"/>
<path d="M257.6 223.1v2.4z"/>
<path d="M247.7 223.1v2.4z"/>
<path d="M250.2 223.1v2.4z"/>
<path d="M252.6 223.1v2.4z"/>
<path d="M255.1 223.1v2.4z"/>
<path d="M264.9 220.6h2.5z"/>
<path d="M272.3 210.7v2.5z"/>
<path d="M267.4 220.6h1.4z"/>
<path d="M270.4 216.3h1.9z"/>
<path d="M272.3 218.1v1.9z"/>
<path d="M270.4 220h1.9z"/>
<path d="M272.3 216.3h2.5z"/>
<path d="M274.8 216.3v1.1z"/>
<path d="M274.8 217.4v2.6z"/>
<path d="M272.3 220h2.5z"/>
<path d="M274.8 217.4l-.6 1.3z"/>
<path d="M274.2 218.7h1.2z"/>
<path d="M274.8 217.4l.6 1.3z"/>
<path d="M274.2 217.4h.6z"/>
<path d="M274.8 217.4h.6z"/>
<path d="M275.7 217.1l-.3 .3z"/>
<path d="M273.9 217.6l.3-.2z"/>
<path d="M270.4 218.1l1.2 .5z"/>
<path d="M271.6 217.6v1z"/>
<path d="M270.4 218.1l1.2-.5z"/>
<path d="M271.5 218.1h.8z"/>
<path d="M272.3 223.1v2.4z"/>
<path d="M272.3 220v3.1z"/>
<path d="M272.3 213.2v3.1z"/>
<path d="M282.2 210.7v2.5z"/>
<path d="M284.7 210.7v2.5z"/>
<path d="M274.8 210.7v2.5z"/>
<path d="M277.3 210.7v2.5z"/>
<path d="M279.7 210.7v2.5z"/>
<path d="M284.7 223.1v2.4z"/>
<path d="M274.8 223.1v2.4z"/>
<path d="M277.3 223.1v2.4z"/>
<path d="M279.7 223.1v2.4z"/>
<path d="M282.2 223.1v2.4z"/>
<path d="M375.9 139.3v2.4z"/>
<path d="M378.3 213.2v2.4z"/>
<path d="M208.3 176.2v2.5z"/>
<path d="M208.3 183.6v2.5z"/>
<path d="M207.3 183.2l1 .4z"/>
<path d="M207.3 183.2l2-.6z"/>
<path d="M207.3 182l2 .6z"/>
<path d="M207.3 182l2-.6z"/>
<path d="M207.3 180.8l2 .6z"/>
<path d="M207.3 180.8l2-.6z"/>
<path d="M207.3 179.6l2 .6z"/>
<path d="M207.3 179.6l2-.7z"/>
<path d="M208.3 178.7l1 .2z"/>
<path d="M235.4 176.2v2.5z"/>
<path d="M235.4 183.6v2.5z"/>
<path d="M234.4 183.2l1 .4z"/>
<path d="M234.4 183.2l2-.6z"/>
<path d="M234.4 182l2 .6z"/>
<path d="M234.4 182l2-.6z"/>
<path d="M234.4 180.8l2 .6z"/>
<path d="M234.4 180.8l2-.6z"/>
<path d="M234.4 179.6l2 .6z"/>
<path d="M234.4 179.6l2-.7z"/>
<path d="M235.4 178.7l1 .2z"/>
<path d="M262.5 176.2v2.5z"/>
<path d="M262.5 183.6v2.5z"/>
<path d="M261.5 183.2l1 .4z"/>
<path d="M261.5 183.2l2-.6z"/>
<path d="M261.5 182l2 .6z"/>
<path d="M261.5 182l2-.6z"/>
<path d="M261.5 180.8l2 .6z"/>
<path d="M261.5 180.8l2-.6z"/>
<path d="M261.5 179.6l2 .6z"/>
<path d="M261.5 179.6l2-.7z"/>
<path d="M262.5 178.7l1 .2z"/>
<path d="M168.8 235.4h2.5z"/>
<path d="M176.2 235.4h2.5z"/>
<path d="M176.2 235.4l-.4 .9z"/>
<path d="M175.2 234.4l.6 1.9z"/>
<path d="M175.2 234.4l-.6 1.9z"/>
<path d="M174 234.4l.6 1.9z"/>
<path d="M174 234.4l-.6 1.9z"/>
<path d="M172.8 234.4l.6 1.9z"/>
<path d="M172.8 234.4l-.6 1.9z"/>
<path d="M171.6 234.4l.6 1.9z"/>
<path d="M171.6 234.4l-.3 1z"/>
<path d="M168.8 240.3h2.5z"/>
<path d="M176.2 240.3h2.5z"/>
<path d="M176.2 240.3l-.4 1z"/>
<path d="M175.2 239.3l.6 2z"/>
<path d="M175.2 239.3l-.6 2z"/>
<path d="M174 239.3l.6 2z"/>
<path d="M174 239.3l-.6 2z"/>
<path d="M172.8 239.3l.6 2z"/>
<path d="M172.8 239.3l-.6 2z"/>
<path d="M171.6 239.3l.6 2z"/>
<path d="M171.6 239.3l-.3 1z"/>
<path d="M168.8 225.5h2.5z"/>
<path d="M176.2 225.5h2.5z"/>
<path d="M176.2 225.5l-.4 1z"/>
<path d="M175.2 224.5l.6 2z"/>
<path d="M175.2 224.5l-.6 2z"/>
<path d="M174 224.5l.6 2z"/>
<path d="M174 224.5l-.6 2z"/>
<path d="M172.8 224.5l.6 2z"/>
<path d="M172.8 224.5l-.6 2z"/>
<path d="M171.6 224.5l.6 2z"/>
<path d="M171.6 224.5l-.3 1z"/>
<path d="M208.3 28.4v2.4z"/>
<path d="M208.3 35.7v2.5z"/>
<path d="M207.3 35.4l1 .3z"/>
<path d="M207.3 35.4l2-.6z"/>
<path d="M207.3 34.2l2 .6z"/>
<path d="M207.3 34.2l2-.7z"/>
<path d="M207.3 32.9l2 .6z"/>
<path d="M207.3 32.9l2-.6z"/>
<path d="M207.3 31.7l2 .6z"/>
<path d="M207.3 31.7l2-.6z"/>
<path d="M208.3 30.8l1 .3z"/>
<path d="M235.4 28.4v2.4z"/>
<path d="M235.4 35.7v2.5z"/>
<path d="M234.4 35.4l1 .3z"/>
<path d="M234.4 35.4l2-.6z"/>
<path d="M234.4 34.2l2 .6z"/>
<path d="M234.4 34.2l2-.7z"/>
<path d="M234.4 32.9l2 .6z"/>
<path d="M234.4 32.9l2-.6z"/>
<path d="M234.4 31.7l2 .6z"/>
<path d="M234.4 31.7l2-.6z"/>
<path d="M235.4 30.8l1 .3z"/>
<path d="M262.5 28.4v2.4z"/>
<path d="M262.5 35.7v2.5z"/>
<path d="M261.5 35.4l1 .3z"/>
<path d="M261.5 35.4l2-.6z"/>
<path d="M261.5 34.2l2 .6z"/>
<path d="M261.5 34.2l2-.7z"/>
<path d="M261.5 32.9l2 .6z"/>
<path d="M261.5 32.9l2-.6z"/>
<path d="M261.5 31.7l2 .6z"/>
<path d="M261.5 31.7l2-.6z"/>
<path d="M262.5 30.8l1 .3z"/>
<path d="M208.3 109.7v2.5z"/>
<path d="M208.3 102.3v2.5z"/>
<path d="M208.3 104.8l1 .3z"/>
<path d="M207.3 105.7l2-.6z"/>
<path d="M207.3 105.7l2 .7z"/>
<path d="M207.3 107l2-.6z"/>
<path d="M207.3 107l2 .6z"/>
<path d="M207.3 108.2l2-.6z"/>
<path d="M207.3 108.2l2 .6z"/>
<path d="M207.3 109.4l2-.6z"/>
<path d="M207.3 109.4l1 .3z"/>
<path d="M262.5 109.7v2.5z"/>
<path d="M262.5 102.3v2.5z"/>
<path d="M262.5 104.8l1 .3z"/>
<path d="M261.5 105.7l2-.6z"/>
<path d="M261.5 105.7l2 .7z"/>
<path d="M261.5 107l2-.6z"/>
<path d="M261.5 107l2 .6z"/>
<path d="M261.5 108.2l2-.6z"/>
<path d="M261.5 108.2l2 .6z"/>
<path d="M261.5 109.4l2-.6z"/>
<path d="M261.5 109.4l1 .3z"/>
<path d="M168.8 166.4h2.5z"/>
<path d="M176.2 166.4h2.5z"/>
<path d="M176.2 166.4l-.4 1z"/>
<path d="M175.2 165.4l.6 2z"/>
<path d="M175.2 165.4l-.6 2z"/>
<path d="M174 165.4l.6 2z"/>
<path d="M174 165.4l-.6 2z"/>
<path d="M172.8 165.4l.6 2z"/>
<path d="M172.8 165.4l-.6 2z"/>
<path d="M171.6 165.4l.6 2z"/>
<path d="M171.6 165.4l-.3 1z"/>
<path d="M168.8 161.4h2.5z"/>
<path d="M176.2 161.4h2.5z"/>
<path d="M176.2 161.4l-.4 1z"/>
<path d="M175.2 160.5l.6 1.9z"/>
<path d="M175.2 160.5l-.6 1.9z"/>
<path d="M174 160.5l.6 1.9z"/>
<path d="M174 160.5l-.6 1.9z"/>
<path d="M172.8 160.5l.6 1.9z"/>
<path d="M172.8 160.5l-.6 1.9z"/>
<path d="M171.6 160.5l.6 1.9z"/>
<path d="M171.6 160.5l-.3 .9z"/>
<path d="M168.8 156.5h2.5z"/>
<path d="M176.2 156.5h2.5z"/>
<path d="M176.2 156.5l-.4 1z"/>
<path d="M175.2 155.5l.6 2z"/>
<path d="M175.2 155.5l-.6 2z"/>
<path d="M174 155.5l.6 2z"/>
<path d="M174 155.5l-.6 2z"/>
<path d="M172.8 155.5l.6 2z"/>
<path d="M172.8 155.5l-.6 2z"/>
<path d="M171.6 155.5l.6 2z"/>
<path d="M171.6 155.5l-.3 1z"/>
<path d="M168.8 151.6h2.5z"/>
<path d="M176.2 151.6h2.5z"/>
<path d="M176.2 151.6l-.4 1z"/>
<path d="M175.2 150.6l.6 2z"/>
<path d="M175.2 150.6l-.6 2z"/>
<path d="M174 150.6l.6 2z"/>
<path d="M174 150.6l-.6 2z"/>
<path d="M172.8 150.6l.6 2z"/>
<path d="M172.8 150.6l-.6 2z"/>
<path d="M171.6 150.6l.6 2z"/>
<path d="M171.6 150.6l-.3 1z"/>
<path d="M168.8 92.4h2.5z"/>
<path d="M176.2 92.4h2.5z"/>
<path d="M176.2 92.4l-.4 1z"/>
<path d="M175.2 91.5l.6 1.9z"/>
<path d="M175.2 91.5l-.6 1.9z"/>
<path d="M174 91.5l.6 1.9z"/>
<path d="M174 91.5l-.6 1.9z"/>
<path d="M172.8 91.5l.6 1.9z"/>
<path d="M172.8 91.5l-.6 1.9z"/>
<path d="M171.6 91.5l.6 1.9z"/>
<path d="M171.6 91.5l-.3 .9z"/>
<path d="M168.8 87.5h2.5z"/>
<path d="M176.2 87.5h2.5z"/>
<path d="M176.2 87.5l-.4 1z"/>
<path d="M175.2 86.5l.6 2z"/>
<path d="M175.2 86.5l-.6 2z"/>
<path d="M174 86.5l.6 2z"/>
<path d="M174 86.5l-.6 2z"/>
<path d="M172.8 86.5l.6 2z"/>
<path d="M172.8 86.5l-.6 2z"/>
<path d="M171.6 86.5l.6 2z"/>
<path d="M171.6 86.5l-.3 1z"/>
<path d="M168.8 82.6h2.5z"/>
<path d="M176.2 82.6h2.5z"/>
<path d="M176.2 82.6l-.4 1z"/>
<path d="M175.2 81.6l.6 2z"/>
<path d="M175.2 81.6l-.6 2z"/>
<path d="M174 81.6l.6 2z"/>
<path d="M174 81.6l-.6 2z"/>
<path d="M172.8 81.6l.6 2z"/>
<path d="M172.8 81.6l-.6 2z"/>
<path d="M171.6 81.6l.6 2z"/>
<path d="M171.6 81.6l-.3 1z"/>
<path d="M168.8 77.7h2.5z"/>
<path d="M176.2 77.7h2.5z"/>
<path d="M176.2 77.7l-.4 .9z"/>
<path d="M175.2 76.7l.6 1.9z"/>
<path d="M175.2 76.7l-.6 1.9z"/>
<path d="M174 76.7l.6 1.9z"/>
<path d="M174 76.7l-.6 1.9z"/>
<path d="M172.8 76.7l.6 1.9z"/>
<path d="M172.8 76.7l-.6 1.9z"/>
<path d="M171.6 76.7l.6 1.9z"/>
<path d="M171.6 76.7l-.3 1z"/>
<path d="M284.7 28.4v2.4z"/>
<path d="M284.7 104.8v2.4z"/>
<path d="M284.7 176.2v2.5z"/>
<path d="M378.3 193.5v2.4z"/>
<path d="M375.9 119.5v2.5z"/>
<path d="M375.9 45.6v2.5z"/>
<path d="M235.4 109.7v2.5z"/>
<path d="M235.4 102.3v2.5z"/>
<path d="M235.4 104.8l1 .3z"/>
<path d="M234.4 105.7l2-.6z"/>
<path d="M234.4 105.7l2 .7z"/>
<path d="M234.4 107l2-.6z"/>
<path d="M234.4 107l2 .6z"/>
<path d="M234.4 108.2l2-.6z"/>
<path d="M234.4 108.2l2 .6z"/>
<path d="M234.4 109.4l2-.6z"/>
<path d="M234.4 109.4l1 .3z"/>
<path d="M311.8 60.4h2.4z"/>
<path d="M311.8 134.3h2.4z"/>
<path d="M311.8 208.3h2.4z"/>
</g>
<g fill="#800000" stroke="#800000" stroke-width=".25">
<path d="M18.5 260h49.3z"/>
<path d="M67.8 260h49.3z"/>
<path d="M117.1 260h49.3z"/>
<path d="M166.4 260h49.3z"/>
<path d="M215.7 260h49.2z"/>
<path d="M264.9 260h34.6z"/>
<path d="M314.2 260h49.3z"/>
<path d="M363.5 260h49.3z"/>
<path d="M412.8 210.7v20.4z"/>
<path d="M412.8 161.4v49.3z"/>
<path d="M412.8 112.2v49.2z"/>
<path d="M412.8 62.9v49.3z"/>
<path d="M412.8 21.6v41.3z"/>
<path d="M412.8 18.5v3.1z"/>
<path d="M412.8 13.6v4.9z"/>
<path d="M67.8 260v4.9z"/>
<path d="M117.1 260v4.9z"/>
<path d="M166.4 260v4.9z"/>
<path d="M215.7 260v4.9z"/>
<path d="M264.9 260v4.9z"/>
<path d="M314.2 260v4.9z"/>
<path d="M363.5 260v4.9z"/>
<path d="M412.8 210.7h5z"/>
<path d="M412.8 161.4h5z"/>
<path d="M412.8 112.2h5z"/>
<path d="M412.8 62.9h5z"/>
<path d="M18.5 210.7v49.3z"/>
<path d="M18.5 161.4v49.3z"/>
<path d="M18.5 112.2v49.2z"/>
<path d="M18.5 62.9v49.3z"/>
<path d="M18.5 13.6v49.3z"/>
<path d="M13.6 210.7h4.9z"/>
<path d="M13.6 161.4h4.9z"/>
<path d="M13.6 112.2h4.9z"/>
<path d="M13.6 62.9h4.9z"/>
<path d="M18.5 13.6h49.3z"/>
<path d="M67.8 13.6h49.3z"/>
<path d="M117.1 13.6h49.3z"/>
<path d="M166.4 13.6h49.3z"/>
<path d="M215.7 13.6h49.2z"/>
<path d="M264.9 13.6h5z"/>
<path d="M269.9 13.6h7.4z"/>
<path d="M277.3 13.6h36.9z"/>
<path d="M314.2 13.6h44.4z"/>
<path d="M358.6 13.6h4.9z"/>
<path d="M363.5 13.6h15.4z"/>
<path d="M378.9 13.6h33.9z"/>
<path d="M67.8 8.7v4.9z"/>
<path d="M117.1 8.7v4.9z"/>
<path d="M166.4 8.7v4.9z"/>
<path d="M215.7 8.7v4.9z"/>
<path d="M264.9 8.7v4.9z"/>
<path d="M314.2 8.7v4.9z"/>
<path d="M363.5 8.7v4.9z"/>
<path d="M378.9 13.6v4.9z"/>
<path d="M378.9 18.5h33.9z"/>
<path d="M358.6 18.5h20.3z"/>
<path d="M277.3 18.5h81.3z"/>
<path d="M269.9 18.5h7.4z"/>
<path d="M269.9 18.5v3.1z"/>
<path d="M269.9 21.6h7.4z"/>
<path d="M277.3 21.6h81.3z"/>
<path d="M358.6 21.6h20.3z"/>
<path d="M378.9 21.6h33.9z"/>
<path d="M277.3 18.5v3.1z"/>
<path d="M358.6 18.5v3.1z"/>
<path d="M378.9 18.5v3.1z"/>
<path d="M269.9 13.6v4.9z"/>
<path d="M277.3 13.6v4.9z"/>
<path d="M358.6 13.6v4.9z"/>
<path d="M299.5 231.1v16.6z"/>
<path d="M299.5 247.7h48z"/>
<path d="M355.5 231.1v16.6z"/>
<path d="M299.5 231.1h56z"/>
<path d="M355.5 231.1h57.3z"/>
<path d="M412.8 231.1v16.6z"/>
<path d="M355.5 247.7h57.3z"/>
<path d="M347.5 247.7h8z"/>
<path d="M299.5 247.7v3.1z"/>
<path d="M299.5 250.8h48z"/>
<path d="M347.5 247.7v3.1z"/>
<path d="M299.5 250.8v3z"/>
<path d="M299.5 253.8h48z"/>
<path d="M347.5 250.8v3z"/>
<path d="M299.5 253.8v3.1z"/>
<path d="M299.5 256.9h48z"/>
<path d="M347.5 253.8v3.1z"/>
<path d="M412.8 247.7v6.1z"/>
<path d="M347.5 253.8h65.3z"/>
<path d="M347.5 256.9h65.3z"/>
<path d="M412.8 253.8v3.1z"/>
<path d="M299.5 256.9v3.1z"/>
<path d="M299.5 260h14.7z"/>
<path d="M412.8 256.9v3.1z"/>
<path d="M102.3 48.1h19.7z"/>
<path d="M122 48.1v19.7z"/>
<path d="M102.3 67.8h19.7z"/>
<path d="M102.3 48.1v19.7z"/>
<path d="M94.9 28.4l1.2 1.8z"/>
<path d="M94.9 28.4l-1.2 1.8z"/>
<path d="M94.9 27.1l1.2 1.9z"/>
<path d="M94.9 27.1l-1.2 1.9z"/>
<path d="M83.2 48.1h3.7z"/>
<path d="M78.3 85h3.7z"/>
<path d="M282.8 90h3.7z"/>
<path d="M115.8 41.9l2.5-1.2z"/>
<path d="M115.8 39.5l2.5 1.2z"/>
<path d="M118.3 39.5h.6z"/>
<path d="M118.3 39.5v1.2z"/>
<path d="M115.8 39.5v2.4z"/>
<path d="M118.3 40.7v1.2z"/>
<path d="M118.9 39.5v.2z"/>
<path d="M117.7 41.9h.6z"/>
<path d="M117.7 41.7v.2z"/>
<path d="M38.2 237.8l-1.2 1.3z"/>
<path d="M29.8 239.1h7.2z"/>
<path d="M29.8 236.6h7.2z"/>
<path d="M37 236.6l1.2 1.2z"/>
<path d="M28.4 237.8l1.2 1.3z"/>
<path d="M28.4 237.8l1.2-1.2z"/>
<path d="M29.6 239.1h.2z"/>
<path d="M29.6 236.6h.2z"/>
<path d="M102.3 122h19.7z"/>
<path d="M122 122v19.7z"/>
<path d="M102.3 141.7h19.7z"/>
<path d="M102.3 122v19.7z"/>
<path d="M94.9 102.3l1.2 1.8z"/>
<path d="M94.9 102.3l-1.2 1.8z"/>
<path d="M94.9 101.1l1.2 1.8z"/>
<path d="M94.9 101.1l-1.2 1.8z"/>
<path d="M83.2 122h3.7z"/>
<path d="M78.3 159h3.7z"/>
<path d="M115.8 115.8l2.5-1.2z"/>
<path d="M115.8 113.4l2.5 1.2z"/>
<path d="M118.3 113.4h.6z"/>
<path d="M118.3 113.4v1.2z"/>
<path d="M115.8 113.4v2.4z"/>
<path d="M118.3 114.6v1.2z"/>
<path d="M118.9 113.4v.2z"/>
<path d="M117.7 115.8h.6z"/>
<path d="M117.7 115.6v.2z"/>
<path d="M102.3 195.9h19.7z"/>
<path d="M122 195.9v19.7z"/>
<path d="M102.3 215.6h19.7z"/>
<path d="M102.3 195.9v19.7z"/>
<path d="M94.9 176.2l1.2 1.9z"/>
<path d="M94.9 176.2l-1.2 1.9z"/>
<path d="M94.9 175l1.2 1.8z"/>
<path d="M94.9 175l-1.2 1.8z"/>
<path d="M83.2 195.9h3.7z"/>
<path d="M78.3 232.9h3.7z"/>
<path d="M115.8 189.8l2.5-1.3z"/>
<path d="M115.8 187.3l2.5 1.2z"/>
<path d="M118.3 187.3h.6z"/>
<path d="M118.3 187.3v1.2z"/>
<path d="M115.8 187.3v2.5z"/>
<path d="M118.3 188.5v1.3z"/>
<path d="M118.9 187.3v.3z"/>
<path d="M117.7 189.8h.6z"/>
<path d="M117.7 189.5v.3z"/>
<path d="M187.5 48.2v4.8z"/>
<path d="M191 55.5h12.3z"/>
<path d="M191 45.6h12.3z"/>
<path d="M187.5 67.9v4.8z"/>
<path d="M191 75.2h12.3z"/>
<path d="M191 65.3h12.3z"/>
<path d="M374 67.8h3.7z"/>
<path d="M214.6 48.2v4.8z"/>
<path d="M218.1 55.5h12.3z"/>
<path d="M218.1 45.6h12.3z"/>
<path d="M241.7 48.2v4.8z"/>
<path d="M245.2 55.5h12.4z"/>
<path d="M245.2 45.6h12.4z"/>
<path d="M268.8 48.2v4.8z"/>
<path d="M272.3 55.5h12.4z"/>
<path d="M272.3 45.6h12.4z"/>
<path d="M214.6 67.9v4.8z"/>
<path d="M218.1 75.2h12.3z"/>
<path d="M218.1 65.3h12.3z"/>
<path d="M241.7 67.9v4.8z"/>
<path d="M245.2 75.2h12.4z"/>
<path d="M245.2 65.3h12.4z"/>
<path d="M268.8 67.9v4.8z"/>
<path d="M272.3 75.2h12.4z"/>
<path d="M272.3 65.3h12.4z"/>
<path d="M282.8 163.9h3.7z"/>
<path d="M187.5 122.1v4.8z"/>
<path d="M191 129.4h12.3z"/>
<path d="M191 119.5h12.3z"/>
<path d="M187.5 141.8v4.9z"/>
<path d="M191 149.1h12.3z"/>
<path d="M191 139.3h12.3z"/>
<path d="M214.6 122.1v4.8z"/>
<path d="M218.1 129.4h12.3z"/>
<path d="M218.1 119.5h12.3z"/>
<path d="M241.7 122.1v4.8z"/>
<path d="M245.2 129.4h12.4z"/>
<path d="M245.2 119.5h12.4z"/>
<path d="M268.8 122.1v4.8z"/>
<path d="M272.3 129.4h12.4z"/>
<path d="M272.3 119.5h12.4z"/>
<path d="M214.6 141.8v4.9z"/>
<path d="M218.1 149.1h12.3z"/>
<path d="M218.1 139.3h12.3z"/>
<path d="M241.7 141.8v4.9z"/>
<path d="M245.2 149.1h12.4z"/>
<path d="M245.2 139.3h12.4z"/>
<path d="M268.8 141.8v4.9z"/>
<path d="M272.3 149.1h12.4z"/>
<path d="M272.3 139.3h12.4z"/>
<path d="M282.8 240.3h3.7z"/>
<path d="M187.5 196.1v4.8z"/>
<path d="M191 203.3h12.3z"/>
<path d="M191 193.5h12.3z"/>
<path d="M187.5 215.8v4.8z"/>
<path d="M191 223.1h12.3z"/>
<path d="M191 213.2h12.3z"/>
<path d="M214.6 196.1v4.8z"/>
<path d="M218.1 203.3h12.3z"/>
<path d="M218.1 193.5h12.3z"/>
<path d="M241.7 196.1v4.8z"/>
<path d="M245.2 203.3h12.4z"/>
<path d="M245.2 193.5h12.4z"/>
<path d="M268.8 196.1v4.8z"/>
<path d="M272.3 203.3h12.4z"/>
<path d="M272.3 193.5h12.4z"/>
<path d="M214.6 215.8v4.8z"/>
<path d="M218.1 223.1h12.3z"/>
<path d="M218.1 213.2h12.3z"/>
<path d="M241.7 215.8v4.8z"/>
<path d="M245.2 223.1h12.4z"/>
<path d="M245.2 213.2h12.4z"/>
<path d="M268.8 215.8v4.8z"/>
<path d="M272.3 223.1h12.4z"/>
<path d="M272.3 213.2h12.4z"/>
<path d="M374 141.7h3.7z"/>
<path d="M376.5 215.6h3.7z"/>
<path d="M284.7 28.4l1.2 1.8z"/>
<path d="M284.7 28.4l-1.3 1.8z"/>
<path d="M284.7 27.1l1.2 1.9z"/>
<path d="M284.7 27.1l-1.3 1.9z"/>
<path d="M284.7 104.8l1.2 1.8z"/>
<path d="M284.7 104.8l-1.3 1.8z"/>
<path d="M284.7 103.5l1.2 1.9z"/>
<path d="M284.7 103.5l-1.3 1.9z"/>
<path d="M284.7 176.2l1.2 1.9z"/>
<path d="M284.7 176.2l-1.3 1.9z"/>
<path d="M284.7 175l1.2 1.8z"/>
<path d="M284.7 175l-1.3 1.8z"/>
<path d="M378.3 193.5l1.3 1.8z"/>
<path d="M378.3 193.5l-1.2 1.8z"/>
<path d="M378.3 192.2l1.3 1.9z"/>
<path d="M378.3 192.2l-1.2 1.9z"/>
<path d="M375.9 119.5l1.2 1.9z"/>
<path d="M375.9 119.5l-1.3 1.9z"/>
<path d="M375.9 118.3l1.2 1.9z"/>
<path d="M375.9 118.3l-1.3 1.9z"/>
<path d="M375.9 45.6l1.2 1.9z"/>
<path d="M375.9 45.6l-1.3 1.9z"/>
<path d="M375.9 44.4l1.2 1.8z"/>
<path d="M375.9 44.4l-1.3 1.8z"/>
<path d="M314.2 55.5h9.9z"/>
<path d="M324.1 55.5v9.8z"/>
<path d="M314.2 65.3h9.9z"/>
<path d="M314.2 55.5v9.8z"/>
<path d="M320.4 58.4l-3.2 3.2z"/>
<path d="M321.1 59.2l-3.2 3.2z"/>
<path d="M314.2 129.4h9.9z"/>
<path d="M324.1 129.4v9.9z"/>
<path d="M314.2 139.3h9.9z"/>
<path d="M314.2 129.4v9.9z"/>
<path d="M320.4 132.4l-3.2 3.2z"/>
<path d="M321.1 133.1l-3.2 3.2z"/>
<path d="M314.2 203.3h9.9z"/>
<path d="M324.1 203.3v9.9z"/>
<path d="M314.2 213.2h9.9z"/>
<path d="M314.2 203.3v9.9z"/>
<path d="M317.2 209.5l3.2-3.2z"/>
<path d="M321.1 207l-3.2 3.2z"/>
</g>
<g fill="#800000" stroke="#800000" stroke-width=".3">
<path d="M348.9 250.2v2.3z"/>
<path d="M348.9 250.2h.6z"/>
<path d="M349.5 250.2l.5 .6z"/>
<path d="M350 250.8v1.7z"/>
<path d="M350 250.8l.6-.6z"/>
<path d="M350.6 250.2l.5 .6z"/>
<path d="M351.1 250.8v1.7z"/>
<path d="M352.9 252.5h1.1z"/>
<path d="M354.6 251.9l-.6 .6z"/>
<path d="M354.6 250.8v1.1z"/>
<path d="M354 250.2l.6 .6z"/>
<path d="M352.9 250.2h1.1z"/>
<path d="M352.3 250.8l.6-.6z"/>
<path d="M352.3 250.8v1.1z"/>
<path d="M352.3 251.9l.6 .6z"/>
<path d="M356.3 249.6v2.3z"/>
<path d="M356.3 251.9l.5 .6z"/>
<path d="M355.7 250.2h1.1z"/>
<path d="M358.5 252.5h1.2z"/>
<path d="M360.2 251.9l-.5 .6z"/>
<path d="M360.2 250.8v1.1z"/>
<path d="M359.7 250.2l.5 .6z"/>
<path d="M358.5 250.2h1.2z"/>
<path d="M358 250.8l.5-.6z"/>
<path d="M358 250.8v1.1z"/>
<path d="M358 251.9l.5 .6z"/>
<path d="M361.4 250.2v2.3z"/>
<path d="M361.4 251.3l1.1-1.1z"/>
<path d="M362.5 250.2h.6z"/>
<path d="M365.9 249.1l.6 .5z"/>
<path d="M364.8 249.1h1.1z"/>
<path d="M364.8 249.1l-.6 .5z"/>
<path d="M364.2 249.6v2.3z"/>
<path d="M364.2 251.9l.6 .6z"/>
<path d="M364.8 252.5h1.1z"/>
<path d="M365.9 252.5l.6-.6z"/>
<path d="M368.2 252.5h1.1z"/>
<path d="M369.3 252.5l.6-.6z"/>
<path d="M369.9 250.8v1.1z"/>
<path d="M369.3 250.2l.6 .6z"/>
<path d="M368.2 250.2h1.1z"/>
<path d="M367.6 250.8l.6-.6z"/>
<path d="M367.6 250.8v1.1z"/>
<path d="M367.6 251.9l.6 .6z"/>
<path d="M371 250.2v2.3z"/>
<path d="M371 250.2h1.7z"/>
<path d="M372.7 250.2l.6 .6z"/>
<path d="M373.3 250.8v1.7z"/>
<path d="M375 249.6v2.3z"/>
<path d="M375 251.9l.6 .6z"/>
<path d="M374.4 250.2h1.2z"/>
<path d="M376.7 250.2v2.3z"/>
<path d="M376.7 251.3l1.1-1.1z"/>
<path d="M377.8 250.2h.6z"/>
<path d="M380.1 252.5h1.1z"/>
<path d="M381.2 252.5l.6-.6z"/>
<path d="M381.8 250.8v1.1z"/>
<path d="M381.2 250.2l.6 .6z"/>
<path d="M380.1 250.2h1.1z"/>
<path d="M380.1 250.2l-.6 .6z"/>
<path d="M379.5 250.8v1.1z"/>
<path d="M379.5 251.9l.6 .6z"/>
<path d="M382.9 249.1h.6z"/>
<path d="M383.5 249.1v3.4z"/>
<path d="M382.9 252.5h1.2z"/>
<path d="M385.2 249.1h.6z"/>
<path d="M385.8 249.1v3.4z"/>
<path d="M385.2 252.5h1.1z"/>
<path d="M388 252.5h1.2z"/>
<path d="M387.5 251.9l.5 .6z"/>
<path d="M387.5 250.8v1.1z"/>
<path d="M387.5 250.8l.5-.6z"/>
<path d="M388 250.2h1.2z"/>
<path d="M389.2 250.2l.5 .6z"/>
<path d="M389.7 250.8v.5z"/>
<path d="M387.5 251.3h2.2z"/>
<path d="M390.9 250.2v2.3z"/>
<path d="M392 250.2l-1.1 1.1z"/>
<path d="M392 250.2h.6z"/>
<path d="M361.2 235.4v2.3z"/>
<path d="M361.2 235.4l1.1-1.1z"/>
<path d="M362.3 234.3l1.2 1.1z"/>
<path d="M363.5 235.4v2.3z"/>
<path d="M361.2 236h2.3z"/>
<path d="M364.6 235.4v1.7z"/>
<path d="M364.6 237.1l.6 .6z"/>
<path d="M365.2 237.7h1.7z"/>
<path d="M366.9 235.4v2.3z"/>
<path d="M368.6 234.8v2.3z"/>
<path d="M368.6 237.1l.6 .6z"/>
<path d="M368 235.4h1.2z"/>
<path d="M370.9 237.7h1.1z"/>
<path d="M372 237.7l.6-.6z"/>
<path d="M372.6 236v1.1z"/>
<path d="M372 235.4l.6 .6z"/>
<path d="M370.9 235.4h1.1z"/>
<path d="M370.9 235.4l-.6 .6z"/>
<path d="M370.3 236v1.1z"/>
<path d="M370.3 237.1l.6 .6z"/>
<path d="M373.7 235.4v2.3z"/>
<path d="M373.7 235.4h1.7z"/>
<path d="M375.4 235.4l.6 .6z"/>
<path d="M376 236v1.7z"/>
<path d="M377.7 237.7h1.1z"/>
<path d="M378.8 237.7l.6-.6z"/>
<path d="M379.4 236v1.1z"/>
<path d="M378.8 235.4l.6 .6z"/>
<path d="M377.7 235.4h1.1z"/>
<path d="M377.7 235.4l-.6 .6z"/>
<path d="M377.1 236v1.1z"/>
<path d="M377.1 237.1l.6 .6z"/>
<path d="M380.5 235.4v2.3z"/>
<path d="M380.5 235.4h.6z"/>
<path d="M381.1 235.4l.5 .6z"/>
<path d="M381.6 236v1.7z"/>
<path d="M381.6 236l.6-.6z"/>
<path d="M382.2 235.4l.6 .6z"/>
<path d="M382.8 236v1.7z"/>
<path d="M384.5 237.7h1.1z"/>
<path d="M385.6 237.7l.6-.6z"/>
<path d="M386.2 236v1.1z"/>
<path d="M385.6 235.4l.6 .6z"/>
<path d="M384.5 235.4h1.1z"/>
<path d="M384.5 235.4l-.6 .6z"/>
<path d="M383.9 236v1.1z"/>
<path d="M383.9 237.1l.6 .6z"/>
<path d="M387.3 235.4v1.7z"/>
<path d="M387.3 237.1l.6 .6z"/>
<path d="M387.9 237.7h1.7z"/>
<path d="M389.6 235.4v2.3z"/>
<path d="M390.7 237.7h1.7z"/>
<path d="M392.4 237.7l.6-.6z"/>
<path d="M392.4 236.6l.6 .5z"/>
<path d="M391.3 236.6h1.1z"/>
<path d="M390.7 236l.6 .6z"/>
<path d="M391.3 235.4l-.6 .6z"/>
<path d="M391.3 235.4h1.7z"/>
<path d="M362.5 241.1v3.3z"/>
<path d="M362.5 241.1h2.2z"/>
<path d="M362.5 242.8h1.1z"/>
<path d="M365.9 241.1h.5z"/>
<path d="M366.4 241.1v3.3z"/>
<path d="M365.9 244.4h1.1z"/>
<path d="M368.1 242.2v1.7z"/>
<path d="M368.1 243.9l.6 .5z"/>
<path d="M368.7 244.4h1.7z"/>
<path d="M370.4 242.2v2.8z"/>
<path d="M370.4 245l-.6 .6z"/>
<path d="M369.2 245.6h.6z"/>
<path d="M371.5 242.2h.6z"/>
<path d="M372.1 242.2v2.2z"/>
<path d="M371.5 244.4h1.2z"/>
<path d="M372.1 240.5v.6z"/>
<path d="M373.8 242.2v2.2z"/>
<path d="M373.8 242.2h1.7z"/>
<path d="M375.5 242.2l.6 .6z"/>
<path d="M376.1 242.8v1.6z"/>
<path d="M378.3 245.6h.6z"/>
<path d="M378.9 245.6l.6-.6z"/>
<path d="M379.5 242.2v2.8z"/>
<path d="M377.8 242.2h1.7z"/>
<path d="M377.8 242.2l-.6 .6z"/>
<path d="M377.2 242.8v1.1z"/>
<path d="M377.2 243.9l.6 .5z"/>
<path d="M377.8 244.4h1.7z"/>
<path d="M385.7 241.1l.6 .5z"/>
<path d="M384.6 241.1h1.1z"/>
<path d="M384 241.6l.6-.5z"/>
<path d="M384 241.6v2.3z"/>
<path d="M384 243.9l.6 .5z"/>
<path d="M384.6 244.4h1.1z"/>
<path d="M385.7 244.4l.6-.5z"/>
<path d="M387.4 242.2v2.2z"/>
<path d="M387.4 243.3l1.2-1.1z"/>
<path d="M388.6 242.2h.5z"/>
<path d="M390.8 242.2h1.1z"/>
<path d="M391.9 242.2l.6 .6z"/>
<path d="M392.5 242.8v1.6z"/>
<path d="M390.8 244.4h1.7z"/>
<path d="M390.2 243.9l.6 .5z"/>
<path d="M390.2 243.9l.6-.6z"/>
<path d="M390.8 243.3h1.7z"/>
<path d="M394.2 241.6v2.8z"/>
<path d="M394.2 241.6l.6-.5z"/>
<path d="M393.7 242.8h1.1z"/>
<path d="M396.5 241.6v2.3z"/>
<path d="M396.5 243.9l.6 .5z"/>
<path d="M395.9 242.2h1.2z"/>
<path d="M189.3 50.5l.9-.2z"/>
<path d="M189.3 50.5l.9 .3z"/>
<path d="M190.2 50.5v.3z"/>
<path d="M189.9 50.5h.3z"/>
<path d="M189.3 70.3l.9-.3z"/>
<path d="M189.3 70.3l.9 .2z"/>
<path d="M190.2 70.3v.2z"/>
<path d="M189.9 70.3h.3z"/>
<path d="M216.4 50.5l.9-.2z"/>
<path d="M216.4 50.5l.9 .3z"/>
<path d="M217.3 50.5v.3z"/>
<path d="M217 50.5h.3z"/>
<path d="M243.5 50.5l.9-.2z"/>
<path d="M243.5 50.5l.9 .3z"/>
<path d="M244.4 50.5v.3z"/>
<path d="M244.1 50.5h.3z"/>
<path d="M270.6 50.5l.9-.2z"/>
<path d="M270.6 50.5l.9 .3z"/>
<path d="M271.5 50.5v.3z"/>
<path d="M271.2 50.5h.3z"/>
<path d="M216.4 70.3l.9-.3z"/>
<path d="M216.4 70.3l.9 .2z"/>
<path d="M217.3 70.3v.2z"/>
<path d="M217 70.3h.3z"/>
<path d="M243.5 70.3l.9-.3z"/>
<path d="M243.5 70.3l.9 .2z"/>
<path d="M244.4 70.3v.2z"/>
<path d="M244.1 70.3h.3z"/>
<path d="M270.6 70.3l.9-.3z"/>
<path d="M270.6 70.3l.9 .2z"/>
<path d="M271.5 70.3v.2z"/>
<path d="M271.2 70.3h.3z"/>
<path d="M189.3 124.5l.9-.3z"/>
<path d="M189.3 124.5l.9 .2z"/>
<path d="M190.2 124.5v.2z"/>
<path d="M189.9 124.5h.3z"/>
<path d="M189.3 144.2l.9-.3z"/>
<path d="M189.3 144.2l.9 .2z"/>
<path d="M190.2 144.2v.2z"/>
<path d="M189.9 144.2h.3z"/>
<path d="M216.4 124.5l.9-.3z"/>
<path d="M216.4 124.5l.9 .2z"/>
<path d="M217.3 124.5v.2z"/>
<path d="M217 124.5h.3z"/>
<path d="M243.5 124.5l.9-.3z"/>
<path d="M243.5 124.5l.9 .2z"/>
<path d="M244.4 124.5v.2z"/>
<path d="M244.1 124.5h.3z"/>
<path d="M270.6 124.5l.9-.3z"/>
<path d="M270.6 124.5l.9 .2z"/>
<path d="M271.5 124.5v.2z"/>
<path d="M271.2 124.5h.3z"/>
<path d="M216.4 144.2l.9-.3z"/>
<path d="M216.4 144.2l.9 .2z"/>
<path d="M217.3 144.2v.2z"/>
<path d="M217 144.2h.3z"/>
<path d="M243.5 144.2l.9-.3z"/>
<path d="M243.5 144.2l.9 .2z"/>
<path d="M244.4 144.2v.2z"/>
<path d="M244.1 144.2h.3z"/>
<path d="M270.6 144.2l.9-.3z"/>
<path d="M270.6 144.2l.9 .2z"/>
<path d="M271.5 144.2v.2z"/>
<path d="M271.2 144.2h.3z"/>
<path d="M189.3 198.4l.9-.2z"/>
<path d="M189.3 198.4l.9 .2z"/>
<path d="M190.2 198.4v.2z"/>
<path d="M189.9 198.4h.3z"/>
<path d="M189.3 218.1l.9-.2z"/>
<path d="M189.3 218.1l.9 .3z"/>
<path d="M190.2 218.1v.3z"/>
<path d="M189.9 218.1h.3z"/>
<path d="M216.4 198.4l.9-.2z"/>
<path d="M216.4 198.4l.9 .2z"/>
<path d="M217.3 198.4v.2z"/>
<path d="M217 198.4h.3z"/>
<path d="M243.5 198.4l.9-.2z"/>
<path d="M243.5 198.4l.9 .2z"/>
<path d="M244.4 198.4v.2z"/>
<path d="M244.1 198.4h.3z"/>
<path d="M270.6 198.4l.9-.2z"/>
<path d="M270.6 198.4l.9 .2z"/>
<path d="M271.5 198.4v.2z"/>
<path d="M271.2 198.4h.3z"/>
<path d="M216.4 218.1l.9-.2z"/>
<path d="M216.4 218.1l.9 .3z"/>
<path d="M217.3 218.1v.3z"/>
<path d="M217 218.1h.3z"/>
<path d="M243.5 218.1l.9-.2z"/>
<path d="M243.5 218.1l.9 .3z"/>
<path d="M244.4 218.1v.3z"/>
<path d="M244.1 218.1h.3z"/>
<path d="M270.6 218.1l.9-.2z"/>
<path d="M270.6 218.1l.9 .3z"/>
<path d="M271.5 218.1v.3z"/>
<path d="M271.2 218.1h.3z"/>
</g>
<g fill="#800000" stroke="#800000" stroke-width=".24">
<path d="M83.1 39.7h3.9v.5h-3.9z"/>
<path d="M83.1 38.7h3.9v.5h-3.9z"/>
<path d="M134.8 47.1h4v.5h-4z"/>
<path d="M134.8 46.1h4v.5h-4z"/>
<path d="M373.9 56.9h3.9v.5h-3.9z"/>
<path d="M373.9 56h3.9v.5h-3.9z"/>
<path d="M83.1 113.6h3.9v.5h-3.9z"/>
<path d="M83.1 112.6h3.9v.5h-3.9z"/>
<path d="M134.8 121h4v.5h-4z"/>
<path d="M134.8 120h4v.5h-4z"/>
<path d="M373.9 130.9h3.9v.5h-3.9z"/>
<path d="M373.9 129.9h3.9v.5h-3.9z"/>
<path d="M83.1 187.6h3.9v.5h-3.9z"/>
<path d="M83.1 186.6h3.9v.5h-3.9z"/>
<path d="M134.8 194.9h4v.5h-4z"/>
<path d="M134.8 194h4v.5h-4z"/>
<path d="M376.4 204.8h3.9v.5h-3.9z"/>
<path d="M376.4 203.8h3.9v.5h-3.9z"/>
<path d="M188.3 51.8h.7v1.2h-.7z"/>
<path d="M188.3 48.1h.7v1.2h-.7z"/>
<path d="M188.3 49.7h.7v1.7h-.7z"/>
<path d="M188.3 71.5h.7v1.2h-.7z"/>
<path d="M188.3 67.8h.7v1.2h-.7z"/>
<path d="M188.3 69.4h.7v1.7h-.7z"/>
<path d="M215.4 51.8h.8v1.2h-.8z"/>
<path d="M215.4 48.1h.8v1.2h-.8z"/>
<path d="M215.4 49.7h.8v1.7h-.8z"/>
<path d="M242.5 51.8h.7v1.2h-.7z"/>
<path d="M242.5 48.1h.7v1.2h-.7z"/>
<path d="M242.5 49.7h.7v1.7h-.7z"/>
<path d="M269.6 51.8h.8v1.2h-.8z"/>
<path d="M269.6 48.1h.8v1.2h-.8z"/>
<path d="M269.6 49.7h.8v1.7h-.8z"/>
<path d="M215.4 71.5h.8v1.2h-.8z"/>
<path d="M215.4 67.8h.8v1.2h-.8z"/>
<path d="M215.4 69.4h.8v1.7h-.8z"/>
<path d="M242.5 71.5h.7v1.2h-.7z"/>
<path d="M242.5 67.8h.7v1.2h-.7z"/>
<path d="M242.5 69.4h.7v1.7h-.7z"/>
<path d="M269.6 71.5h.8v1.2h-.8z"/>
<path d="M269.6 67.8h.8v1.2h-.8z"/>
<path d="M269.6 69.4h.8v1.7h-.8z"/>
<path d="M188.3 125.7h.7v1.2h-.7z"/>
<path d="M188.3 122h.7v1.2h-.7z"/>
<path d="M188.3 123.6h.7v1.7h-.7z"/>
<path d="M188.3 145.4h.7v1.2h-.7z"/>
<path d="M188.3 141.7h.7v1.3h-.7z"/>
<path d="M188.3 143.3h.7v1.8h-.7z"/>
<path d="M215.4 125.7h.8v1.2h-.8z"/>
<path d="M215.4 122h.8v1.2h-.8z"/>
<path d="M215.4 123.6h.8v1.7h-.8z"/>
<path d="M242.5 125.7h.7v1.2h-.7z"/>
<path d="M242.5 122h.7v1.2h-.7z"/>
<path d="M242.5 123.6h.7v1.7h-.7z"/>
<path d="M269.6 125.7h.8v1.2h-.8z"/>
<path d="M269.6 122h.8v1.2h-.8z"/>
<path d="M269.6 123.6h.8v1.7h-.8z"/>
<path d="M215.4 145.4h.8v1.2h-.8z"/>
<path d="M215.4 141.7h.8v1.3h-.8z"/>
<path d="M215.4 143.3h.8v1.8h-.8z"/>
<path d="M242.5 145.4h.7v1.2h-.7z"/>
<path d="M242.5 141.7h.7v1.3h-.7z"/>
<path d="M242.5 143.3h.7v1.8h-.7z"/>
<path d="M269.6 145.4h.8v1.2h-.8z"/>
<path d="M269.6 141.7h.8v1.3h-.8z"/>
<path d="M269.6 143.3h.8v1.8h-.8z"/>
<path d="M188.3 199.6h.7v1.3h-.7z"/>
<path d="M188.3 195.9h.7v1.3h-.7z"/>
<path d="M188.3 197.5h.7v1.8h-.7z"/>
<path d="M188.3 219.3h.7v1.3h-.7z"/>
<path d="M188.3 215.7h.7v1.2h-.7z"/>
<path d="M188.3 217.3h.7v1.7h-.7z"/>
<path d="M215.4 199.6h.8v1.3h-.8z"/>
<path d="M215.4 195.9h.8v1.3h-.8z"/>
<path d="M215.4 197.5h.8v1.8h-.8z"/>
<path d="M242.5 199.6h.7v1.3h-.7z"/>
<path d="M242.5 195.9h.7v1.3h-.7z"/>
<path d="M242.5 197.5h.7v1.8h-.7z"/>
<path d="M269.6 199.6h.8v1.3h-.8z"/>
<path d="M269.6 195.9h.8v1.3h-.8z"/>
<path d="M269.6 197.5h.8v1.8h-.8z"/>
<path d="M215.4 219.3h.8v1.3h-.8z"/>
<path d="M215.4 215.7h.8v1.2h-.8z"/>
<path d="M215.4 217.3h.8v1.7h-.8z"/>
<path d="M242.5 219.3h.7v1.3h-.7z"/>
<path d="M242.5 215.7h.7v1.2h-.7z"/>
<path d="M242.5 217.3h.7v1.7h-.7z"/>
<path d="M269.6 219.3h.8v1.3h-.8z"/>
<path d="M269.6 215.7h.8v1.2h-.8z"/>
<path d="M269.6 217.3h.8v1.7h-.8z"/>
</g>
<g fill="none" stroke="#800000" stroke-width=".4">
<circle cx="191" cy="52.4" r=".13"/>
<circle cx="191" cy="48.7" r=".13"/>
<circle cx="218.1" cy="52.4" r=".13"/>
<circle cx="218.1" cy="48.7" r=".13"/>
<circle cx="245.2" cy="52.4" r=".13"/>
<circle cx="245.2" cy="48.7" r=".13"/>
<circle cx="272.3" cy="48.7" r=".13"/>
<circle cx="272.3" cy="52.4" r=".13"/>
<circle cx="191" cy="68.4" r=".13"/>
<circle cx="191" cy="72.1" r=".13"/>
<circle cx="218.1" cy="72.1" r=".13"/>
<circle cx="218.1" cy="68.4" r=".13"/>
<circle cx="245.2" cy="72.1" r=".13"/>
<circle cx="245.2" cy="68.4" r=".13"/>
<circle cx="272.3" cy="68.4" r=".13"/>
<circle cx="272.3" cy="72.1" r=".13"/>
<circle cx="191" cy="126.3" r=".13"/>
<circle cx="191" cy="122.6" r=".13"/>
<circle cx="218.1" cy="126.3" r=".13"/>
<circle cx="218.1" cy="122.6" r=".13"/>
<circle cx="245.2" cy="126.3" r=".13"/>
<circle cx="245.2" cy="122.6" r=".13"/>
<circle cx="272.3" cy="126.3" r=".13"/>
<circle cx="272.3" cy="122.6" r=".13"/>
<circle cx="191" cy="142.3" r=".13"/>
<circle cx="191" cy="146" r=".13"/>
<circle cx="218.1" cy="146" r=".13"/>
<circle cx="218.1" cy="142.3" r=".13"/>
<circle cx="245.2" cy="146" r=".13"/>
<circle cx="245.2" cy="142.3" r=".13"/>
<circle cx="272.3" cy="146" r=".13"/>
<circle cx="272.3" cy="142.3" r=".13"/>
<circle cx="191" cy="196.6" r=".13"/>
<circle cx="218.1" cy="196.6" r=".13"/>
<circle cx="245.2" cy="196.6" r=".13"/>
<circle cx="272.3" cy="196.6" r=".13"/>
<circle cx="191" cy="220" r=".13"/>
<circle cx="191" cy="216.3" r=".13"/>
<circle cx="191" cy="200.3" r=".13"/>
<circle cx="218.1" cy="216.3" r=".13"/>
<circle cx="218.1" cy="220" r=".13"/>
<circle cx="218.1" cy="200.3" r=".13"/>
<circle cx="245.2" cy="220" r=".13"/>
<circle cx="245.2" cy="216.3" r=".13"/>
<circle cx="245.2" cy="200.3" r=".13"/>
<circle cx="272.3" cy="220" r=".13"/>
<circle cx="272.3" cy="216.3" r=".13"/>
<circle cx="272.3" cy="200.3" r=".13"/>
</g>
<g fill="none" stroke="#800000" stroke-width=".24">
<circle cx="191" cy="50.5" r="5.5"/>
<circle cx="218.1" cy="50.5" r="5.5"/>
<circle cx="245.2" cy="50.5" r="5.5"/>
<circle cx="272.3" cy="50.5" r="5.5"/>
<circle cx="191" cy="70.3" r="5.5"/>
<circle cx="218.1" cy="70.3" r="5.5"/>
<circle cx="245.2" cy="70.3" r="5.5"/>
<circle cx="272.3" cy="70.3" r="5.5"/>
<circle cx="191" cy="124.5" r="5.5"/>
<circle cx="218.1" cy="124.5" r="5.5"/>
<circle cx="245.2" cy="124.5" r="5.5"/>
<circle cx="272.3" cy="124.5" r="5.5"/>
<circle cx="191" cy="144.2" r="5.5"/>
<circle cx="218.1" cy="144.2" r="5.5"/>
<circle cx="245.2" cy="144.2" r="5.5"/>
<circle cx="272.3" cy="144.2" r="5.5"/>
<circle cx="191" cy="198.4" r="5.5"/>
<circle cx="218.1" cy="198.4" r="5.5"/>
<circle cx="245.2" cy="198.4" r="5.5"/>
<circle cx="272.3" cy="198.4" r="5.5"/>
<circle cx="191" cy="218.1" r="5.5"/>
<circle cx="218.1" cy="218.1" r="5.5"/>
<circle cx="245.2" cy="218.1" r="5.5"/>
<circle cx="272.3" cy="218.1" r="5.5"/>
</g>
<g fill="none" stroke="#800000" stroke-width=".25">
<circle cx="319.2" cy="60.4" r="2.46"/>
<circle cx="319.2" cy="134.3" r="2.46"/>
<circle cx="319.2" cy="208.3" r="2.46"/>
</g>
<g fill="#000080" stroke="#000080" stroke-width=".74">
<path d="M40.7 53v184.8z"/>
<path d="M38.2 237.8h2.5z"/>
</g>
<g fill="#008000" stroke="#008000" stroke-width=".24">
<path d="M94.9 60.4h2.5z"/>
<path d="M191 57.9v2.5z"/>
<path d="M126.9 60.4h9.9z"/>
<path d="M136.8 60.4h54.2z"/>
<path d="M136.8 50.5v9.9z"/>
<path d="M191 60.4h2.5z"/>
<path d="M193.5 60.4h2.4z"/>
<path d="M195.9 60.4h2.5z"/>
<path d="M198.4 60.4h2.5z"/>
<path d="M200.9 60.4h2.4z"/>
<path d="M203.3 60.4h14.8z"/>
<path d="M218.1 60.4h2.5z"/>
<path d="M220.6 60.4h2.5z"/>
<path d="M223.1 60.4h2.4z"/>
<path d="M225.5 60.4h2.5z"/>
<path d="M228 60.4h2.4z"/>
<path d="M230.4 60.4h14.8z"/>
<path d="M245.2 60.4h2.5z"/>
<path d="M247.7 60.4h2.5z"/>
<path d="M250.2 60.4h2.4z"/>
<path d="M252.6 60.4h2.5z"/>
<path d="M255.1 60.4h2.5z"/>
<path d="M257.6 60.4h14.7z"/>
<path d="M272.3 60.4h2.5z"/>
<path d="M274.8 60.4h2.5z"/>
<path d="M277.3 60.4h2.4z"/>
<path d="M279.7 60.4h2.5z"/>
<path d="M282.2 60.4h2.5z"/>
<path d="M191 60.4v2.5z"/>
<path d="M193.5 60.4v2.5z"/>
<path d="M195.9 60.4v2.5z"/>
<path d="M198.4 60.4v2.5z"/>
<path d="M200.9 60.4v2.5z"/>
<path d="M203.3 60.4v2.5z"/>
<path d="M203.3 57.9v2.5z"/>
<path d="M200.9 57.9v2.5z"/>
<path d="M198.4 57.9v2.5z"/>
<path d="M195.9 57.9v2.5z"/>
<path d="M193.5 57.9v2.5z"/>
<path d="M284.7 57.9v2.5z"/>
<path d="M284.7 60.4v2.5z"/>
<path d="M257.6 57.9v2.5z"/>
<path d="M257.6 60.4v2.5z"/>
<path d="M230.4 57.9v2.5z"/>
<path d="M230.4 60.4v2.5z"/>
<path d="M282.2 57.9v2.5z"/>
<path d="M282.2 60.4v2.5z"/>
<path d="M279.7 60.4v2.5z"/>
<path d="M279.7 57.9v2.5z"/>
<path d="M277.3 57.9v2.5z"/>
<path d="M277.3 60.4v2.5z"/>
<path d="M274.8 60.4v2.5z"/>
<path d="M274.8 57.9v2.5z"/>
<path d="M272.3 57.9v2.5z"/>
<path d="M272.3 60.4v2.5z"/>
<path d="M218.1 60.4v2.5z"/>
<path d="M218.1 57.9v2.5z"/>
<path d="M220.6 57.9v2.5z"/>
<path d="M220.6 60.4v2.5z"/>
<path d="M223.1 57.9v2.5z"/>
<path d="M223.1 60.4v2.5z"/>
<path d="M225.5 57.9v2.5z"/>
<path d="M225.5 60.4v2.5z"/>
<path d="M228 57.9v2.5z"/>
<path d="M228 60.4v2.5z"/>
<path d="M245.2 57.9v2.5z"/>
<path d="M245.2 60.4v2.5z"/>
<path d="M247.7 57.9v2.5z"/>
<path d="M247.7 60.4v2.5z"/>
<path d="M250.2 57.9v2.5z"/>
<path d="M250.2 60.4v2.5z"/>
<path d="M252.6 57.9v2.5z"/>
<path d="M252.6 60.4v2.5z"/>
<path d="M255.1 57.9v2.5z"/>
<path d="M255.1 60.4v2.5z"/>
<path d="M284.7 60.4h27.1z"/>
<path d="M136.8 40.7v2.5z"/>
<path d="M129.4 40.7h7.4z"/>
<path d="M129.4 40.7v9.8z"/>
<path d="M126.9 50.5h2.5z"/>
<path d="M119.5 40.7h9.9z"/>
<path d="M112.1 40.7h2.5z"/>
<path d="M87.5 55.5h9.9z"/>
<path d="M94.9 50.5h2.5z"/>
<path d="M94.9 40.7v9.8z"/>
<path d="M94.9 33.3v7.4z"/>
<path d="M94.9 40.7h7.4z"/>
<path d="M85 33.3v2.4z"/>
<path d="M85 33.3h9.9z"/>
<path d="M94.9 30.8v2.5z"/>
<path d="M94.9 124.5h2.5z"/>
<path d="M94.9 114.6v9.9z"/>
<path d="M94.9 107.2v7.4z"/>
<path d="M94.9 114.6h7.4z"/>
<path d="M85 107.2v2.5z"/>
<path d="M85 107.2h9.9z"/>
<path d="M94.9 104.8v2.4z"/>
<path d="M94.9 198.4h2.5z"/>
<path d="M94.9 188.5v9.9z"/>
<path d="M94.9 181.1v7.4z"/>
<path d="M94.9 188.5h7.4z"/>
<path d="M85 181.1v2.5z"/>
<path d="M85 181.1h9.9z"/>
<path d="M94.9 178.7v2.4z"/>
<path d="M284.7 40.7v2.5z"/>
<path d="M284.7 30.8v9.9z"/>
<path d="M282.2 40.7h2.5z"/>
<path d="M282.2 40.7v2.5z"/>
<path d="M279.7 40.7h2.5z"/>
<path d="M279.7 40.7v2.5z"/>
<path d="M277.3 40.7h2.4z"/>
<path d="M277.3 40.7v2.5z"/>
<path d="M274.8 40.7h2.5z"/>
<path d="M274.8 40.7v2.5z"/>
<path d="M272.3 40.7h2.5z"/>
<path d="M272.3 40.7v2.5z"/>
<path d="M257.6 40.7h14.7z"/>
<path d="M257.6 40.7v2.5z"/>
<path d="M255.1 40.7h2.5z"/>
<path d="M255.1 40.7v2.5z"/>
<path d="M252.6 40.7h2.5z"/>
<path d="M252.6 40.7v2.5z"/>
<path d="M250.2 40.7h2.4z"/>
<path d="M250.2 40.7v2.5z"/>
<path d="M247.7 40.7h2.5z"/>
<path d="M247.7 40.7v2.5z"/>
<path d="M245.2 40.7h2.5z"/>
<path d="M245.2 40.7v2.5z"/>
<path d="M230.4 40.7h14.8z"/>
<path d="M230.4 40.7v2.5z"/>
<path d="M228 40.7h2.4z"/>
<path d="M228 40.7v2.5z"/>
<path d="M225.5 40.7h2.5z"/>
<path d="M225.5 40.7v2.5z"/>
<path d="M223.1 40.7h2.4z"/>
<path d="M223.1 40.7v2.5z"/>
<path d="M220.6 40.7h2.5z"/>
<path d="M220.6 40.7v2.5z"/>
<path d="M218.1 40.7h2.5z"/>
<path d="M218.1 40.7v2.5z"/>
<path d="M203.3 40.7v2.5z"/>
<path d="M203.3 40.7h14.8z"/>
<path d="M200.9 40.7h2.4z"/>
<path d="M200.9 40.7v2.5z"/>
<path d="M198.4 40.7h2.5z"/>
<path d="M198.4 40.7v2.5z"/>
<path d="M195.9 40.7h2.5z"/>
<path d="M195.9 40.7v2.5z"/>
<path d="M193.5 40.7h2.4z"/>
<path d="M193.5 40.7v2.5z"/>
<path d="M191 40.7h2.5z"/>
<path d="M191 40.7v2.5z"/>
<path d="M375.9 48.1v4.9z"/>
<path d="M375.9 122v4.9z"/>
<path d="M284.7 114.6v2.5z"/>
<path d="M284.7 107.2v7.4z"/>
<path d="M282.2 114.6h2.5z"/>
<path d="M282.2 114.6v2.5z"/>
<path d="M279.7 114.6h2.5z"/>
<path d="M279.7 114.6v2.5z"/>
<path d="M277.3 114.6h2.4z"/>
<path d="M277.3 114.6v2.5z"/>
<path d="M274.8 114.6h2.5z"/>
<path d="M274.8 114.6v2.5z"/>
<path d="M272.3 114.6h2.5z"/>
<path d="M272.3 114.6v2.5z"/>
<path d="M257.6 114.6h14.7z"/>
<path d="M257.6 114.6v2.5z"/>
<path d="M255.1 114.6h2.5z"/>
<path d="M255.1 114.6v2.5z"/>
<path d="M252.6 114.6h2.5z"/>
<path d="M252.6 114.6v2.5z"/>
<path d="M250.2 114.6h2.4z"/>
<path d="M250.2 114.6v2.5z"/>
<path d="M247.7 114.6h2.5z"/>
<path d="M247.7 114.6v2.5z"/>
<path d="M245.2 114.6h2.5z"/>
<path d="M245.2 114.6v2.5z"/>
<path d="M230.4 114.6h14.8z"/>
<path d="M230.4 114.6v2.5z"/>
<path d="M228 114.6h2.4z"/>
<path d="M228 114.6v2.5z"/>
<path d="M225.5 114.6h2.5z"/>
<path d="M225.5 114.6v2.5z"/>
<path d="M223.1 114.6h2.4z"/>
<path d="M223.1 114.6v2.5z"/>
<path d="M220.6 114.6h2.5z"/>
<path d="M220.6 114.6v2.5z"/>
<path d="M218.1 114.6h2.5z"/>
<path d="M218.1 114.6v2.5z"/>
<path d="M203.3 114.6v2.5z"/>
<path d="M203.3 114.6h14.8z"/>
<path d="M200.9 114.6h2.4z"/>
<path d="M200.9 114.6v2.5z"/>
<path d="M198.4 114.6h2.5z"/>
<path d="M198.4 114.6v2.5z"/>
<path d="M195.9 114.6h2.5z"/>
<path d="M195.9 114.6v2.5z"/>
<path d="M193.5 114.6h2.4z"/>
<path d="M193.5 114.6v2.5z"/>
<path d="M191 114.6h2.5z"/>
<path d="M191 114.6v2.5z"/>
<path d="M191 188.5v2.5z"/>
<path d="M203.3 188.5v2.5z"/>
<path d="M200.9 188.5h2.4z"/>
<path d="M198.4 188.5h2.5z"/>
<path d="M195.9 188.5h2.5z"/>
<path d="M193.5 188.5h2.4z"/>
<path d="M191 188.5h2.5z"/>
<path d="M193.5 188.5v2.5z"/>
<path d="M195.9 188.5v2.5z"/>
<path d="M198.4 188.5v2.5z"/>
<path d="M200.9 188.5v2.5z"/>
<path d="M203.3 188.5h14.8z"/>
<path d="M218.1 188.5h2.5z"/>
<path d="M220.6 188.5h2.5z"/>
<path d="M223.1 188.5h2.4z"/>
<path d="M225.5 188.5h2.5z"/>
<path d="M228 188.5h2.4z"/>
<path d="M230.4 188.5h14.8z"/>
<path d="M245.2 188.5h2.5z"/>
<path d="M247.7 188.5h2.5z"/>
<path d="M250.2 188.5h2.4z"/>
<path d="M252.6 188.5h2.5z"/>
<path d="M255.1 188.5h2.5z"/>
<path d="M257.6 188.5h14.7z"/>
<path d="M272.3 188.5h2.5z"/>
<path d="M274.8 188.5h2.5z"/>
<path d="M277.3 188.5h2.4z"/>
<path d="M279.7 188.5h2.5z"/>
<path d="M282.2 188.5h2.5z"/>
<path d="M284.7 188.5v2.5z"/>
<path d="M257.6 188.5v2.5z"/>
<path d="M230.4 188.5v2.5z"/>
<path d="M218.1 188.5v2.5z"/>
<path d="M220.6 188.5v2.5z"/>
<path d="M223.1 188.5v2.5z"/>
<path d="M225.5 188.5v2.5z"/>
<path d="M228 188.5v2.5z"/>
<path d="M245.2 188.5v2.5z"/>
<path d="M247.7 188.5v2.5z"/>
<path d="M250.2 188.5v2.5z"/>
<path d="M252.6 188.5v2.5z"/>
<path d="M255.1 188.5v2.5z"/>
<path d="M272.3 188.5v2.5z"/>
<path d="M274.8 188.5v2.5z"/>
<path d="M277.3 188.5v2.5z"/>
<path d="M279.7 188.5v2.5z"/>
<path d="M282.2 188.5v2.5z"/>
<path d="M284.7 178.7v9.8z"/>
<path d="M378.3 195.9v5z"/>
<path d="M85 43.2v2.4z"/>
<path d="M80.1 75.2v7.4z"/>
<path d="M80.1 72.7v2.5z"/>
<path d="M72.7 72.7v2.5z"/>
<path d="M72.7 75.2h7.4z"/>
<path d="M94.9 65.3h2.5z"/>
<path d="M94.9 65.3v9.9z"/>
<path d="M80.1 75.2h14.8z"/>
<path d="M85 117.1v2.4z"/>
<path d="M80.1 149.1v7.4z"/>
<path d="M80.1 146.7v2.4z"/>
<path d="M72.7 146.7v2.4z"/>
<path d="M72.7 149.1h7.4z"/>
<path d="M94.9 139.3h2.5z"/>
<path d="M94.9 139.3v9.8z"/>
<path d="M80.1 149.1h14.8z"/>
<path d="M85 191v2.5z"/>
<path d="M80.1 223.1v7.3z"/>
<path d="M80.1 220.6v2.5z"/>
<path d="M72.7 220.6v2.5z"/>
<path d="M72.7 223.1h7.4z"/>
<path d="M94.9 213.2h2.5z"/>
<path d="M94.9 213.2v9.9z"/>
<path d="M80.1 223.1h14.8z"/>
<path d="M375.9 60.4v4.9z"/>
<path d="M378.3 208.3v4.9z"/>
<path d="M375.9 134.3v5z"/>
<path d="M191 225.5v2.5z"/>
<path d="M191 228h2.5z"/>
<path d="M193.5 228h2.4z"/>
<path d="M195.9 228h2.5z"/>
<path d="M198.4 228h2.5z"/>
<path d="M200.9 228h2.4z"/>
<path d="M193.5 225.5v2.5z"/>
<path d="M195.9 225.5v2.5z"/>
<path d="M198.4 225.5v2.5z"/>
<path d="M200.9 225.5v2.5z"/>
<path d="M203.3 225.5v2.5z"/>
<path d="M203.3 228h14.8z"/>
<path d="M218.1 228h2.5z"/>
<path d="M220.6 228h2.5z"/>
<path d="M223.1 228h2.4z"/>
<path d="M225.5 228h2.5z"/>
<path d="M228 228h2.4z"/>
<path d="M230.4 228h14.8z"/>
<path d="M245.2 228h2.5z"/>
<path d="M247.7 228h2.5z"/>
<path d="M250.2 228h2.4z"/>
<path d="M252.6 228h2.5z"/>
<path d="M255.1 228h2.5z"/>
<path d="M257.6 228h14.7z"/>
<path d="M272.3 228h2.5z"/>
<path d="M274.8 228h2.5z"/>
<path d="M277.3 228h2.4z"/>
<path d="M279.7 228h2.5z"/>
<path d="M282.2 228h2.5z"/>
<path d="M284.7 225.5v2.5z"/>
<path d="M257.6 225.5v2.5z"/>
<path d="M230.4 225.5v2.5z"/>
<path d="M272.3 225.5v2.5z"/>
<path d="M274.8 225.5v2.5z"/>
<path d="M277.3 225.5v2.5z"/>
<path d="M279.7 225.5v2.5z"/>
<path d="M282.2 225.5v2.5z"/>
<path d="M255.1 225.5v2.5z"/>
<path d="M252.6 225.5v2.5z"/>
<path d="M250.2 225.5v2.5z"/>
<path d="M247.7 225.5v2.5z"/>
<path d="M245.2 225.5v2.5z"/>
<path d="M228 225.5v2.5z"/>
<path d="M225.5 225.5v2.5z"/>
<path d="M223.1 225.5v2.5z"/>
<path d="M220.6 225.5v2.5z"/>
<path d="M218.1 225.5v2.5z"/>
<path d="M284.7 228v9.8z"/>
<path d="M191 77.7v2.4z"/>
<path d="M191 80.1h2.5z"/>
<path d="M193.5 80.1h2.4z"/>
<path d="M195.9 80.1h2.5z"/>
<path d="M198.4 80.1h2.5z"/>
<path d="M200.9 80.1h2.4z"/>
<path d="M193.5 77.7v2.4z"/>
<path d="M195.9 77.7v2.4z"/>
<path d="M198.4 77.7v2.4z"/>
<path d="M200.9 77.7v2.4z"/>
<path d="M203.3 77.7v2.4z"/>
<path d="M203.3 80.1h14.8z"/>
<path d="M218.1 80.1h2.5z"/>
<path d="M220.6 80.1h2.5z"/>
<path d="M223.1 80.1h2.4z"/>
<path d="M225.5 80.1h2.5z"/>
<path d="M228 80.1h2.4z"/>
<path d="M230.4 80.1h14.8z"/>
<path d="M245.2 80.1h2.5z"/>
<path d="M247.7 80.1h2.5z"/>
<path d="M250.2 80.1h2.4z"/>
<path d="M252.6 80.1h2.5z"/>
<path d="M255.1 80.1h2.5z"/>
<path d="M257.6 80.1h14.7z"/>
<path d="M272.3 80.1h2.5z"/>
<path d="M274.8 80.1h2.5z"/>
<path d="M277.3 80.1h2.4z"/>
<path d="M279.7 80.1h2.5z"/>
<path d="M282.2 80.1h2.5z"/>
<path d="M284.7 77.7v2.4z"/>
<path d="M257.6 77.7v2.4z"/>
<path d="M230.4 77.7v2.4z"/>
<path d="M272.3 77.7v2.4z"/>
<path d="M274.8 77.7v2.4z"/>
<path d="M277.3 77.7v2.4z"/>
<path d="M279.7 77.7v2.4z"/>
<path d="M282.2 77.7v2.4z"/>
<path d="M255.1 77.7v2.4z"/>
<path d="M252.6 77.7v2.4z"/>
<path d="M250.2 77.7v2.4z"/>
<path d="M247.7 77.7v2.4z"/>
<path d="M245.2 77.7v2.4z"/>
<path d="M228 77.7v2.4z"/>
<path d="M225.5 77.7v2.4z"/>
<path d="M223.1 77.7v2.4z"/>
<path d="M220.6 77.7v2.4z"/>
<path d="M218.1 77.7v2.4z"/>
<path d="M284.7 80.1v7.4z"/>
<path d="M284.7 151.6v2.4z"/>
<path d="M284.7 154v7.4z"/>
<path d="M282.2 154h2.5z"/>
<path d="M282.2 151.6v2.4z"/>
<path d="M279.7 154h2.5z"/>
<path d="M279.7 151.6v2.4z"/>
<path d="M277.3 154h2.4z"/>
<path d="M277.3 151.6v2.4z"/>
<path d="M274.8 154h2.5z"/>
<path d="M274.8 151.6v2.4z"/>
<path d="M272.3 154h2.5z"/>
<path d="M272.3 151.6v2.4z"/>
<path d="M257.6 154h14.7z"/>
<path d="M257.6 151.6v2.4z"/>
<path d="M255.1 154h2.5z"/>
<path d="M255.1 151.6v2.4z"/>
<path d="M252.6 154h2.5z"/>
<path d="M252.6 151.6v2.4z"/>
<path d="M250.2 154h2.4z"/>
<path d="M250.2 151.6v2.4z"/>
<path d="M247.7 154h2.5z"/>
<path d="M247.7 151.6v2.4z"/>
<path d="M245.2 154h2.5z"/>
<path d="M245.2 151.6v2.4z"/>
<path d="M230.4 154h14.8z"/>
<path d="M230.4 151.6v2.4z"/>
<path d="M228 154h2.4z"/>
<path d="M228 151.6v2.4z"/>
<path d="M225.5 154h2.5z"/>
<path d="M225.5 151.6v2.4z"/>
<path d="M223.1 154h2.4z"/>
<path d="M223.1 151.6v2.4z"/>
<path d="M220.6 154h2.5z"/>
<path d="M220.6 151.6v2.4z"/>
<path d="M218.1 154h2.5z"/>
<path d="M218.1 151.6v2.4z"/>
<path d="M203.3 151.6v2.4z"/>
<path d="M203.3 154h14.8z"/>
<path d="M200.9 151.6v2.4z"/>
<path d="M200.9 154h2.4z"/>
<path d="M198.4 151.6v2.4z"/>
<path d="M198.4 154h2.5z"/>
<path d="M195.9 151.6v2.4z"/>
<path d="M195.9 154h2.5z"/>
<path d="M193.5 151.6v2.4z"/>
<path d="M193.5 154h2.4z"/>
<path d="M191 151.6v2.4z"/>
<path d="M191 154h2.5z"/>
<path d="M126.9 65.3h37z"/>
<path d="M163.9 65.3v12.4z"/>
<path d="M163.9 77.7v4.9z"/>
<path d="M163.9 82.6v4.9z"/>
<path d="M163.9 87.5v4.9z"/>
<path d="M163.9 92.4h4.9z"/>
<path d="M163.9 87.5h4.9z"/>
<path d="M163.9 82.6h4.9z"/>
<path d="M163.9 77.7h4.9z"/>
<path d="M72.7 55.5v7.4z"/>
<path d="M72.7 55.5h4.9z"/>
<path d="M40.7 55.5h32z"/>
<path d="M80.1 60.4h4.9z"/>
<path d="M80.1 60.4v2.5z"/>
<path d="M40.7 60.4h39.4z"/>
<path d="M94.9 134.3h2.5z"/>
<path d="M136.8 114.6v2.5z"/>
<path d="M129.4 114.6h7.4z"/>
<path d="M129.4 114.6v9.9z"/>
<path d="M126.9 124.5h2.5z"/>
<path d="M119.5 114.6h9.9z"/>
<path d="M112.1 114.6h2.5z"/>
<path d="M87.5 129.4h9.9z"/>
<path d="M126.9 139.3h37z"/>
<path d="M163.9 139.3v12.3z"/>
<path d="M163.9 151.6v4.9z"/>
<path d="M163.9 156.5v4.9z"/>
<path d="M163.9 161.4v5z"/>
<path d="M163.9 166.4h4.9z"/>
<path d="M163.9 161.4h4.9z"/>
<path d="M163.9 156.5h4.9z"/>
<path d="M163.9 151.6h4.9z"/>
<path d="M94.9 208.3h2.5z"/>
<path d="M136.8 188.5v2.5z"/>
<path d="M129.4 188.5h7.4z"/>
<path d="M129.4 188.5v9.9z"/>
<path d="M126.9 198.4h2.5z"/>
<path d="M119.5 188.5h9.9z"/>
<path d="M126.9 203.3h41.9z"/>
<path d="M168.8 173.8v29.5z"/>
<path d="M168.8 173.8h12.4z"/>
<path d="M181.2 173.8h27.1z"/>
<path d="M208.3 173.8h27.1z"/>
<path d="M235.4 173.8h27.1z"/>
<path d="M262.5 173.8v2.4z"/>
<path d="M235.4 173.8v2.4z"/>
<path d="M208.3 173.8v2.4z"/>
<path d="M181.2 173.8v2.4z"/>
<path d="M112.1 188.5h2.5z"/>
<path d="M87.5 203.3h9.9z"/>
<path d="M163.9 240.3h4.9z"/>
<path d="M163.9 235.4v4.9z"/>
<path d="M163.9 230.4v5z"/>
<path d="M163.9 225.5v4.9z"/>
<path d="M163.9 213.2v12.3z"/>
<path d="M126.9 213.2h37z"/>
<path d="M163.9 235.4h4.9z"/>
<path d="M163.9 230.4h4.9z"/>
<path d="M163.9 225.5h4.9z"/>
<path d="M72.7 129.4v7.4z"/>
<path d="M72.7 129.4h4.9z"/>
<path d="M40.7 129.4h32z"/>
<path d="M80.1 134.3h4.9z"/>
<path d="M80.1 134.3v2.5z"/>
<path d="M40.7 134.3h39.4z"/>
<path d="M72.7 203.3v7.4z"/>
<path d="M72.7 203.3h4.9z"/>
<path d="M40.7 203.3h32z"/>
<path d="M80.1 208.3h4.9z"/>
<path d="M80.1 208.3v2.4z"/>
<path d="M40.7 208.3h39.4z"/>
<path d="M191 131.9v2.4z"/>
<path d="M191 134.3h2.5z"/>
<path d="M193.5 134.3h2.4z"/>
<path d="M195.9 134.3h2.5z"/>
<path d="M198.4 134.3h2.5z"/>
<path d="M200.9 134.3h2.4z"/>
<path d="M203.3 134.3h14.8z"/>
<path d="M218.1 134.3h2.5z"/>
<path d="M220.6 134.3h2.5z"/>
<path d="M223.1 134.3h2.4z"/>
<path d="M225.5 134.3h2.5z"/>
<path d="M228 134.3h2.4z"/>
<path d="M230.4 134.3h14.8z"/>
<path d="M245.2 134.3h2.5z"/>
<path d="M247.7 134.3h2.5z"/>
<path d="M250.2 134.3h2.4z"/>
<path d="M252.6 134.3h2.5z"/>
<path d="M255.1 134.3h2.5z"/>
<path d="M257.6 134.3h14.7z"/>
<path d="M272.3 134.3h2.5z"/>
<path d="M274.8 134.3h2.5z"/>
<path d="M277.3 134.3h2.4z"/>
<path d="M279.7 134.3h2.5z"/>
<path d="M282.2 134.3h2.5z"/>
<path d="M191 134.3v2.5z"/>
<path d="M193.5 134.3v2.5z"/>
<path d="M195.9 134.3v2.5z"/>
<path d="M198.4 134.3v2.5z"/>
<path d="M200.9 134.3v2.5z"/>
<path d="M203.3 134.3v2.5z"/>
<path d="M203.3 131.9v2.4z"/>
<path d="M200.9 131.9v2.4z"/>
<path d="M198.4 131.9v2.4z"/>
<path d="M195.9 131.9v2.4z"/>
<path d="M193.5 131.9v2.4z"/>
<path d="M284.7 131.9v2.4z"/>
<path d="M284.7 134.3v2.5z"/>
<path d="M257.6 131.9v2.4z"/>
<path d="M257.6 134.3v2.5z"/>
<path d="M230.4 131.9v2.4z"/>
<path d="M230.4 134.3v2.5z"/>
<path d="M282.2 131.9v2.4z"/>
<path d="M282.2 134.3v2.5z"/>
<path d="M279.7 134.3v2.5z"/>
<path d="M279.7 131.9v2.4z"/>
<path d="M277.3 131.9v2.4z"/>
<path d="M277.3 134.3v2.5z"/>
<path d="M274.8 134.3v2.5z"/>
<path d="M274.8 131.9v2.4z"/>
<path d="M272.3 131.9v2.4z"/>
<path d="M272.3 134.3v2.5z"/>
<path d="M218.1 134.3v2.5z"/>
<path d="M218.1 131.9v2.4z"/>
<path d="M220.6 131.9v2.4z"/>
<path d="M220.6 134.3v2.5z"/>
<path d="M223.1 131.9v2.4z"/>
<path d="M223.1 134.3v2.5z"/>
<path d="M225.5 131.9v2.4z"/>
<path d="M225.5 134.3v2.5z"/>
<path d="M228 131.9v2.4z"/>
<path d="M228 134.3v2.5z"/>
<path d="M245.2 131.9v2.4z"/>
<path d="M245.2 134.3v2.5z"/>
<path d="M247.7 131.9v2.4z"/>
<path d="M247.7 134.3v2.5z"/>
<path d="M250.2 131.9v2.4z"/>
<path d="M250.2 134.3v2.5z"/>
<path d="M252.6 131.9v2.4z"/>
<path d="M252.6 134.3v2.5z"/>
<path d="M255.1 131.9v2.4z"/>
<path d="M255.1 134.3v2.5z"/>
<path d="M126.9 134.3h9.9z"/>
<path d="M136.8 124.5v9.8z"/>
<path d="M136.8 134.3h54.2z"/>
<path d="M284.7 134.3h27.1z"/>
<path d="M191 205.8v2.5z"/>
<path d="M191 208.3h2.5z"/>
<path d="M193.5 208.3h2.4z"/>
<path d="M195.9 208.3h2.5z"/>
<path d="M198.4 208.3h2.5z"/>
<path d="M200.9 208.3h2.4z"/>
<path d="M203.3 208.3h14.8z"/>
<path d="M218.1 208.3h2.5z"/>
<path d="M220.6 208.3h2.5z"/>
<path d="M223.1 208.3h2.4z"/>
<path d="M225.5 208.3h2.5z"/>
<path d="M228 208.3h2.4z"/>
<path d="M230.4 208.3h14.8z"/>
<path d="M245.2 208.3h2.5z"/>
<path d="M247.7 208.3h2.5z"/>
<path d="M250.2 208.3h2.4z"/>
<path d="M252.6 208.3h2.5z"/>
<path d="M255.1 208.3h2.5z"/>
<path d="M257.6 208.3h14.7z"/>
<path d="M272.3 208.3h2.5z"/>
<path d="M274.8 208.3h2.5z"/>
<path d="M277.3 208.3h2.4z"/>
<path d="M279.7 208.3h2.5z"/>
<path d="M282.2 208.3h2.5z"/>
<path d="M191 208.3v2.4z"/>
<path d="M193.5 208.3v2.4z"/>
<path d="M195.9 208.3v2.4z"/>
<path d="M198.4 208.3v2.4z"/>
<path d="M200.9 208.3v2.4z"/>
<path d="M203.3 208.3v2.4z"/>
<path d="M203.3 205.8v2.5z"/>
<path d="M200.9 205.8v2.5z"/>
<path d="M198.4 205.8v2.5z"/>
<path d="M195.9 205.8v2.5z"/>
<path d="M193.5 205.8v2.5z"/>
<path d="M284.7 205.8v2.5z"/>
<path d="M284.7 208.3v2.4z"/>
<path d="M257.6 205.8v2.5z"/>
<path d="M257.6 208.3v2.4z"/>
<path d="M230.4 205.8v2.5z"/>
<path d="M230.4 208.3v2.4z"/>
<path d="M282.2 205.8v2.5z"/>
<path d="M282.2 208.3v2.4z"/>
<path d="M279.7 208.3v2.4z"/>
<path d="M279.7 205.8v2.5z"/>
<path d="M277.3 205.8v2.5z"/>
<path d="M277.3 208.3v2.4z"/>
<path d="M274.8 208.3v2.4z"/>
<path d="M274.8 205.8v2.5z"/>
<path d="M272.3 205.8v2.5z"/>
<path d="M272.3 208.3v2.4z"/>
<path d="M218.1 208.3v2.4z"/>
<path d="M218.1 205.8v2.5z"/>
<path d="M220.6 205.8v2.5z"/>
<path d="M220.6 208.3v2.4z"/>
<path d="M223.1 205.8v2.5z"/>
<path d="M223.1 208.3v2.4z"/>
<path d="M225.5 205.8v2.5z"/>
<path d="M225.5 208.3v2.4z"/>
<path d="M228 205.8v2.5z"/>
<path d="M228 208.3v2.4z"/>
<path d="M245.2 205.8v2.5z"/>
<path d="M245.2 208.3v2.4z"/>
<path d="M247.7 205.8v2.5z"/>
<path d="M247.7 208.3v2.4z"/>
<path d="M250.2 205.8v2.5z"/>
<path d="M250.2 208.3v2.4z"/>
<path d="M252.6 205.8v2.5z"/>
<path d="M252.6 208.3v2.4z"/>
<path d="M255.1 205.8v2.5z"/>
<path d="M255.1 208.3v2.4z"/>
<path d="M136.8 198.4v9.9z"/>
<path d="M126.9 208.3h9.9z"/>
<path d="M136.8 208.3h54.2z"/>
<path d="M284.7 208.3h27.1z"/>
<path d="M208.3 186.1v14.8z"/>
<path d="M208.3 200.9h2.4z"/>
<path d="M235.4 186.1v14.8z"/>
<path d="M235.4 200.9h2.4z"/>
<path d="M262.5 186.1v14.8z"/>
<path d="M262.5 200.9h2.4z"/>
<path d="M181.2 186.1v14.8z"/>
<path d="M181.2 200.9h2.4z"/>
<path d="M178.7 225.5h2.5z"/>
<path d="M181.2 220.6v4.9z"/>
<path d="M181.2 220.6h2.4z"/>
<path d="M178.7 230.4h29.6z"/>
<path d="M208.3 220.6v9.8z"/>
<path d="M208.3 220.6h2.4z"/>
<path d="M235.4 220.6h2.4z"/>
<path d="M235.4 220.6v14.8z"/>
<path d="M178.7 235.4h56.7z"/>
<path d="M262.5 220.6h2.4z"/>
<path d="M262.5 220.6v19.7z"/>
<path d="M178.7 240.3h83.8z"/>
<path d="M178.7 82.6h29.6z"/>
<path d="M208.3 72.7v9.9z"/>
<path d="M208.3 72.7h2.4z"/>
<path d="M178.7 87.5h56.7z"/>
<path d="M235.4 72.7v14.8z"/>
<path d="M235.4 72.7h2.4z"/>
<path d="M178.7 92.4h83.8z"/>
<path d="M262.5 72.7v19.7z"/>
<path d="M262.5 72.7h2.4z"/>
<path d="M181.2 38.2v14.8z"/>
<path d="M181.2 53h2.4z"/>
<path d="M181.2 112.2v14.7z"/>
<path d="M181.2 126.9h2.4z"/>
<path d="M208.3 112.2v14.7z"/>
<path d="M208.3 126.9h2.4z"/>
<path d="M262.5 112.2v14.7z"/>
<path d="M262.5 126.9h2.4z"/>
<path d="M178.7 161.4h56.7z"/>
<path d="M235.4 146.7v14.7z"/>
<path d="M235.4 146.7h2.4z"/>
<path d="M178.7 166.4h83.8z"/>
<path d="M262.5 146.7v19.7z"/>
<path d="M262.5 146.7h2.4z"/>
<path d="M178.7 156.5h29.6z"/>
<path d="M208.3 146.7v9.8z"/>
<path d="M208.3 146.7h2.4z"/>
<path d="M178.7 151.6h2.5z"/>
<path d="M181.2 146.7v4.9z"/>
<path d="M181.2 146.7h2.4z"/>
<path d="M178.7 77.7h2.5z"/>
<path d="M181.2 72.7v5z"/>
<path d="M181.2 72.7h2.4z"/>
<path d="M208.3 38.2v14.8z"/>
<path d="M208.3 53h2.4z"/>
<path d="M235.4 38.2v14.8z"/>
<path d="M235.4 53h2.4z"/>
<path d="M262.5 38.2v14.8z"/>
<path d="M262.5 53h2.4z"/>
<path d="M235.4 25.9v2.5z"/>
<path d="M208.3 25.9v2.5z"/>
<path d="M181.2 25.9v2.5z"/>
<path d="M168.8 25.9v29.6z"/>
<path d="M126.9 55.5h41.9z"/>
<path d="M262.5 25.9v2.5z"/>
<path d="M168.8 25.9h12.4z"/>
<path d="M181.2 25.9h27.1z"/>
<path d="M208.3 25.9h27.1z"/>
<path d="M235.4 25.9h27.1z"/>
<path d="M208.3 99.8v2.5z"/>
<path d="M181.2 99.8v2.5z"/>
<path d="M126.9 129.4h41.9z"/>
<path d="M168.8 99.8v29.6z"/>
<path d="M262.5 99.8v2.5z"/>
<path d="M168.8 99.8h12.4z"/>
<path d="M181.2 99.8h27.1z"/>
<path d="M208.3 99.8h27.1z"/>
<path d="M235.4 99.8h27.1z"/>
<path d="M235.4 99.8v2.5z"/>
<path d="M235.4 112.2v14.7z"/>
<path d="M235.4 126.9h2.4z"/>
<circle cx="191" cy="60.4" r=".49"/>
<circle cx="136.8" cy="60.4" r=".49"/>
<circle cx="193.5" cy="60.4" r=".49"/>
<circle cx="195.9" cy="60.4" r=".49"/>
<circle cx="198.4" cy="60.4" r=".49"/>
<circle cx="200.9" cy="60.4" r=".49"/>
<circle cx="203.3" cy="60.4" r=".49"/>
<circle cx="284.7" cy="60.4" r=".49"/>
<circle cx="257.6" cy="60.4" r=".49"/>
<circle cx="230.4" cy="60.4" r=".49"/>
<circle cx="282.2" cy="60.4" r=".49"/>
<circle cx="279.7" cy="60.4" r=".49"/>
<circle cx="277.3" cy="60.4" r=".49"/>
<circle cx="274.8" cy="60.4" r=".49"/>
<circle cx="272.3" cy="60.4" r=".49"/>
<circle cx="218.1" cy="60.4" r=".49"/>
<circle cx="220.6" cy="60.4" r=".49"/>
<circle cx="223.1" cy="60.4" r=".49"/>
<circle cx="225.5" cy="60.4" r=".49"/>
<circle cx="228" cy="60.4" r=".49"/>
<circle cx="245.2" cy="60.4" r=".49"/>
<circle cx="247.7" cy="60.4" r=".49"/>
<circle cx="250.2" cy="60.4" r=".49"/>
<circle cx="252.6" cy="60.4" r=".49"/>
<circle cx="255.1" cy="60.4" r=".49"/>
<circle cx="129.4" cy="40.7" r=".49"/>
<circle cx="94.9" cy="40.7" r=".49"/>
<circle cx="94.9" cy="33.3" r=".49"/>
<circle cx="94.9" cy="114.6" r=".49"/>
<circle cx="94.9" cy="107.2" r=".49"/>
<circle cx="94.9" cy="188.5" r=".49"/>
<circle cx="94.9" cy="181.1" r=".49"/>
<circle cx="284.7" cy="40.7" r=".49"/>
<circle cx="282.2" cy="40.7" r=".49"/>
<circle cx="279.7" cy="40.7" r=".49"/>
<circle cx="277.3" cy="40.7" r=".49"/>
<circle cx="274.8" cy="40.7" r=".49"/>
<circle cx="272.3" cy="40.7" r=".49"/>
<circle cx="257.6" cy="40.7" r=".49"/>
<circle cx="255.1" cy="40.7" r=".49"/>
<circle cx="252.6" cy="40.7" r=".49"/>
<circle cx="250.2" cy="40.7" r=".49"/>
<circle cx="247.7" cy="40.7" r=".49"/>
<circle cx="245.2" cy="40.7" r=".49"/>
<circle cx="230.4" cy="40.7" r=".49"/>
<circle cx="228" cy="40.7" r=".49"/>
<circle cx="225.5" cy="40.7" r=".49"/>
<circle cx="223.1" cy="40.7" r=".49"/>
<circle cx="220.6" cy="40.7" r=".49"/>
<circle cx="218.1" cy="40.7" r=".49"/>
<circle cx="203.3" cy="40.7" r=".49"/>
<circle cx="200.9" cy="40.7" r=".49"/>
<circle cx="198.4" cy="40.7" r=".49"/>
<circle cx="195.9" cy="40.7" r=".49"/>
<circle cx="193.5" cy="40.7" r=".49"/>
<circle cx="284.7" cy="114.6" r=".49"/>
<circle cx="282.2" cy="114.6" r=".49"/>
<circle cx="279.7" cy="114.6" r=".49"/>
<circle cx="277.3" cy="114.6" r=".49"/>
<circle cx="274.8" cy="114.6" r=".49"/>
<circle cx="272.3" cy="114.6" r=".49"/>
<circle cx="257.6" cy="114.6" r=".49"/>
<circle cx="255.1" cy="114.6" r=".49"/>
<circle cx="252.6" cy="114.6" r=".49"/>
<circle cx="250.2" cy="114.6" r=".49"/>
<circle cx="247.7" cy="114.6" r=".49"/>
<circle cx="245.2" cy="114.6" r=".49"/>
<circle cx="230.4" cy="114.6" r=".49"/>
<circle cx="228" cy="114.6" r=".49"/>
<circle cx="225.5" cy="114.6" r=".49"/>
<circle cx="223.1" cy="114.6" r=".49"/>
<circle cx="220.6" cy="114.6" r=".49"/>
<circle cx="218.1" cy="114.6" r=".49"/>
<circle cx="203.3" cy="114.6" r=".49"/>
<circle cx="200.9" cy="114.6" r=".49"/>
<circle cx="198.4" cy="114.6" r=".49"/>
<circle cx="195.9" cy="114.6" r=".49"/>
<circle cx="193.5" cy="114.6" r=".49"/>
<circle cx="193.5" cy="188.5" r=".49"/>
<circle cx="195.9" cy="188.5" r=".49"/>
<circle cx="198.4" cy="188.5" r=".49"/>
<circle cx="200.9" cy="188.5" r=".49"/>
<circle cx="203.3" cy="188.5" r=".49"/>
<circle cx="257.6" cy="188.5" r=".49"/>
<circle cx="230.4" cy="188.5" r=".49"/>
<circle cx="218.1" cy="188.5" r=".49"/>
<circle cx="220.6" cy="188.5" r=".49"/>
<circle cx="223.1" cy="188.5" r=".49"/>
<circle cx="225.5" cy="188.5" r=".49"/>
<circle cx="228" cy="188.5" r=".49"/>
<circle cx="245.2" cy="188.5" r=".49"/>
<circle cx="247.7" cy="188.5" r=".49"/>
<circle cx="250.2" cy="188.5" r=".49"/>
<circle cx="252.6" cy="188.5" r=".49"/>
<circle cx="255.1" cy="188.5" r=".49"/>
<circle cx="272.3" cy="188.5" r=".49"/>
<circle cx="274.8" cy="188.5" r=".49"/>
<circle cx="277.3" cy="188.5" r=".49"/>
<circle cx="279.7" cy="188.5" r=".49"/>
<circle cx="282.2" cy="188.5" r=".49"/>
<circle cx="284.7" cy="188.5" r=".49"/>
<circle cx="80.1" cy="75.2" r=".49"/>
<circle cx="80.1" cy="149.1" r=".49"/>
<circle cx="80.1" cy="223.1" r=".49"/>
<circle cx="193.5" cy="228" r=".49"/>
<circle cx="195.9" cy="228" r=".49"/>
<circle cx="198.4" cy="228" r=".49"/>
<circle cx="200.9" cy="228" r=".49"/>
<circle cx="203.3" cy="228" r=".49"/>
<circle cx="257.6" cy="228" r=".49"/>
<circle cx="230.4" cy="228" r=".49"/>
<circle cx="272.3" cy="228" r=".49"/>
<circle cx="274.8" cy="228" r=".49"/>
<circle cx="277.3" cy="228" r=".49"/>
<circle cx="279.7" cy="228" r=".49"/>
<circle cx="282.2" cy="228" r=".49"/>
<circle cx="255.1" cy="228" r=".49"/>
<circle cx="252.6" cy="228" r=".49"/>
<circle cx="250.2" cy="228" r=".49"/>
<circle cx="247.7" cy="228" r=".49"/>
<circle cx="245.2" cy="228" r=".49"/>
<circle cx="228" cy="228" r=".49"/>
<circle cx="225.5" cy="228" r=".49"/>
<circle cx="223.1" cy="228" r=".49"/>
<circle cx="220.6" cy="228" r=".49"/>
<circle cx="218.1" cy="228" r=".49"/>
<circle cx="284.7" cy="228" r=".49"/>
<circle cx="193.5" cy="80.1" r=".49"/>
<circle cx="195.9" cy="80.1" r=".49"/>
<circle cx="198.4" cy="80.1" r=".49"/>
<circle cx="200.9" cy="80.1" r=".49"/>
<circle cx="203.3" cy="80.1" r=".49"/>
<circle cx="257.6" cy="80.1" r=".49"/>
<circle cx="230.4" cy="80.1" r=".49"/>
<circle cx="272.3" cy="80.1" r=".49"/>
<circle cx="274.8" cy="80.1" r=".49"/>
<circle cx="277.3" cy="80.1" r=".49"/>
<circle cx="279.7" cy="80.1" r=".49"/>
<circle cx="282.2" cy="80.1" r=".49"/>
<circle cx="255.1" cy="80.1" r=".49"/>
<circle cx="252.6" cy="80.1" r=".49"/>
<circle cx="250.2" cy="80.1" r=".49"/>
<circle cx="247.7" cy="80.1" r=".49"/>
<circle cx="245.2" cy="80.1" r=".49"/>
<circle cx="228" cy="80.1" r=".49"/>
<circle cx="225.5" cy="80.1" r=".49"/>
<circle cx="223.1" cy="80.1" r=".49"/>
<circle cx="220.6" cy="80.1" r=".49"/>
<circle cx="218.1" cy="80.1" r=".49"/>
<circle cx="284.7" cy="80.1" r=".49"/>
<circle cx="284.7" cy="154" r=".49"/>
<circle cx="282.2" cy="154" r=".49"/>
<circle cx="279.7" cy="154" r=".49"/>
<circle cx="277.3" cy="154" r=".49"/>
<circle cx="274.8" cy="154" r=".49"/>
<circle cx="272.3" cy="154" r=".49"/>
<circle cx="257.6" cy="154" r=".49"/>
<circle cx="255.1" cy="154" r=".49"/>
<circle cx="252.6" cy="154" r=".49"/>
<circle cx="250.2" cy="154" r=".49"/>
<circle cx="247.7" cy="154" r=".49"/>
<circle cx="245.2" cy="154" r=".49"/>
<circle cx="230.4" cy="154" r=".49"/>
<circle cx="228" cy="154" r=".49"/>
<circle cx="225.5" cy="154" r=".49"/>
<circle cx="223.1" cy="154" r=".49"/>
<circle cx="220.6" cy="154" r=".49"/>
<circle cx="218.1" cy="154" r=".49"/>
<circle cx="203.3" cy="154" r=".49"/>
<circle cx="200.9" cy="154" r=".49"/>
<circle cx="198.4" cy="154" r=".49"/>
<circle cx="195.9" cy="154" r=".49"/>
<circle cx="193.5" cy="154" r=".49"/>
<circle cx="163.9" cy="87.5" r=".49"/>
<circle cx="163.9" cy="82.6" r=".49"/>
<circle cx="163.9" cy="77.7" r=".49"/>
<circle cx="72.7" cy="55.5" r=".49"/>
<circle cx="80.1" cy="60.4" r=".49"/>
<circle cx="129.4" cy="114.6" r=".49"/>
<circle cx="163.9" cy="151.6" r=".49"/>
<circle cx="163.9" cy="156.5" r=".49"/>
<circle cx="163.9" cy="161.4" r=".49"/>
<circle cx="129.4" cy="188.5" r=".49"/>
<circle cx="235.4" cy="173.8" r=".49"/>
<circle cx="208.3" cy="173.8" r=".49"/>
<circle cx="181.2" cy="173.8" r=".49"/>
<circle cx="163.9" cy="235.4" r=".49"/>
<circle cx="163.9" cy="230.4" r=".49"/>
<circle cx="163.9" cy="225.5" r=".49"/>
<circle cx="72.7" cy="129.4" r=".49"/>
<circle cx="80.1" cy="134.3" r=".49"/>
<circle cx="72.7" cy="203.3" r=".49"/>
<circle cx="80.1" cy="208.3" r=".49"/>
<circle cx="191" cy="134.3" r=".49"/>
<circle cx="193.5" cy="134.3" r=".49"/>
<circle cx="195.9" cy="134.3" r=".49"/>
<circle cx="198.4" cy="134.3" r=".49"/>
<circle cx="200.9" cy="134.3" r=".49"/>
<circle cx="203.3" cy="134.3" r=".49"/>
<circle cx="284.7" cy="134.3" r=".49"/>
<circle cx="257.6" cy="134.3" r=".49"/>
<circle cx="230.4" cy="134.3" r=".49"/>
<circle cx="282.2" cy="134.3" r=".49"/>
<circle cx="279.7" cy="134.3" r=".49"/>
<circle cx="277.3" cy="134.3" r=".49"/>
<circle cx="274.8" cy="134.3" r=".49"/>
<circle cx="272.3" cy="134.3" r=".49"/>
<circle cx="218.1" cy="134.3" r=".49"/>
<circle cx="220.6" cy="134.3" r=".49"/>
<circle cx="223.1" cy="134.3" r=".49"/>
<circle cx="225.5" cy="134.3" r=".49"/>
<circle cx="228" cy="134.3" r=".49"/>
<circle cx="245.2" cy="134.3" r=".49"/>
<circle cx="247.7" cy="134.3" r=".49"/>
<circle cx="250.2" cy="134.3" r=".49"/>
<circle cx="252.6" cy="134.3" r=".49"/>
<circle cx="255.1" cy="134.3" r=".49"/>
<circle cx="136.8" cy="134.3" r=".49"/>
<circle cx="191" cy="208.3" r=".49"/>
<circle cx="193.5" cy="208.3" r=".49"/>
<circle cx="195.9" cy="208.3" r=".49"/>
<circle cx="198.4" cy="208.3" r=".49"/>
<circle cx="200.9" cy="208.3" r=".49"/>
<circle cx="203.3" cy="208.3" r=".49"/>
<circle cx="284.7" cy="208.3" r=".49"/>
<circle cx="257.6" cy="208.3" r=".49"/>
<circle cx="230.4" cy="208.3" r=".49"/>
<circle cx="282.2" cy="208.3" r=".49"/>
<circle cx="279.7" cy="208.3" r=".49"/>
<circle cx="277.3" cy="208.3" r=".49"/>
<circle cx="274.8" cy="208.3" r=".49"/>
<circle cx="272.3" cy="208.3" r=".49"/>
<circle cx="218.1" cy="208.3" r=".49"/>
<circle cx="220.6" cy="208.3" r=".49"/>
<circle cx="223.1" cy="208.3" r=".49"/>
<circle cx="225.5" cy="208.3" r=".49"/>
<circle cx="228" cy="208.3" r=".49"/>
<circle cx="245.2" cy="208.3" r=".49"/>
<circle cx="247.7" cy="208.3" r=".49"/>
<circle cx="250.2" cy="208.3" r=".49"/>
<circle cx="252.6" cy="208.3" r=".49"/>
<circle cx="255.1" cy="208.3" r=".49"/>
<circle cx="136.8" cy="208.3" r=".49"/>
<circle cx="181.2" cy="25.9" r=".49"/>
<circle cx="208.3" cy="25.9" r=".49"/>
<circle cx="235.4" cy="25.9" r=".49"/>
<circle cx="181.2" cy="99.8" r=".49"/>
<circle cx="208.3" cy="99.8" r=".49"/>
<circle cx="235.4" cy="99.8" r=".49"/>
</g>
<use href="#words"/>
</svg>
